(* Logix 5000 AddOnInstructionDefinition export Ed25519_VERIFY; software revision 30.00; part 2 of 7 *)

ADD_ON_INSTRUCTION POINT_ADD   (* revision 1.0 20170916, vendor Kenneth A. Fischer *)
// Point Add:
// p3 = p1 + p2
// Requires POINT UDT
// Revision note:
// Rev1.0: 20170916 - Initial Release
VAR_IN_OUT
   Temp_C1 : DINT[22]; {required}   // A
   Temp_C2 : DINT[22]; {required}   // B
   Temp_C3 : DINT[22]; {required}   // C
   Temp_C4 : DINT[22]; {required}   // D
   Temp_C5 : DINT[22]; {required}   // E
   Temp_C6 : DINT[22]; {required}   // F
   Temp_C7 : DINT[22]; {required}   // G
   Temp_C8 : DINT[22]; {required}   // H
   Temp_C9 : DINT[22]; {required}   // R
   Temp_C10 : DINT[22]; {required}   // S
   Temp_D : DINT[43]; {required}   // W
   Inp_P1 : POINT; {required}
   Inp_P2 : POINT; {required}
   Out_P3 : POINT; {required}
END_VAR
VAR
   B256_SUB : B256_SUB;
   B256_ADD : B256_ADD;
   B256_MUL : B256_MUL;
   B256_MUL2 : B256_MUL2;
END_VAR

ROUTINE Logic   (* ladder *)
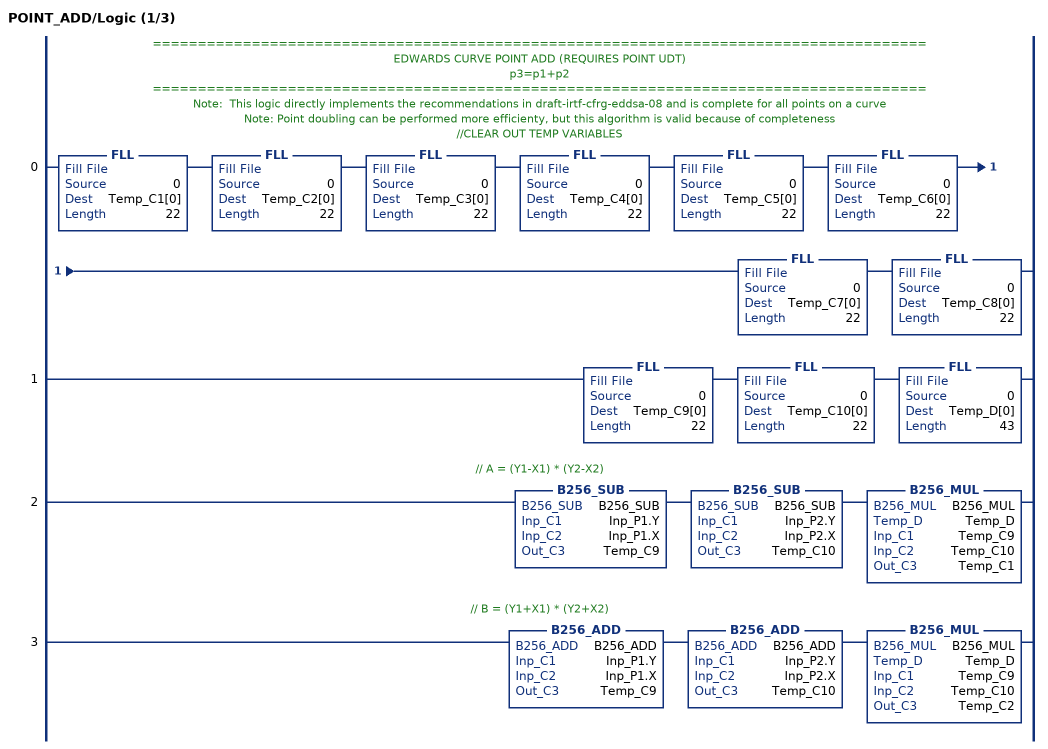
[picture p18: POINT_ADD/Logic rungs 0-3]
   // ======================================================================================
   // EDWARDS CURVE POINT ADD (REQUIRES POINT UDT)
   // p3=p1+p2
   // ======================================================================================
   // Note:  This logic directly implements the recommendations in draft-irtf-cfrg-eddsa-08 and is complete for all points on a curve
   // Note: Point doubling can be performed more efficienty, but this algorithm is valid because of completeness
   // //CLEAR OUT TEMP VARIABLES
   0: FLL(0,Temp_C1[0],22)FLL(0,Temp_C2[0],22)FLL(0,Temp_C3[0],22)FLL(0,Temp_C4[0],22)FLL(0,Temp_C5[0],22)FLL(0,Temp_C6[0],22)FLL(0,Temp_C7[0],22)FLL(0,Temp_C8[0],22);
   1: FLL(0,Temp_C9[0],22)FLL(0,Temp_C10[0],22)FLL(0,Temp_D[0],43);
   // // A = (Y1-X1) * (Y2-X2)
   2: B256_SUB(B256_SUB,Inp_P1.Y,Inp_P1.X,Temp_C9)B256_SUB(B256_SUB,Inp_P2.Y,Inp_P2.X,Temp_C10)B256_MUL(B256_MUL,Temp_D,Temp_C9,Temp_C10,Temp_C1);
   // // B = (Y1+X1) * (Y2+X2)
   3: B256_ADD(B256_ADD,Inp_P1.Y,Inp_P1.X,Temp_C9)B256_ADD(B256_ADD,Inp_P2.Y,Inp_P2.X,Temp_C10)B256_MUL(B256_MUL,Temp_D,Temp_C9,Temp_C10,Temp_C2);
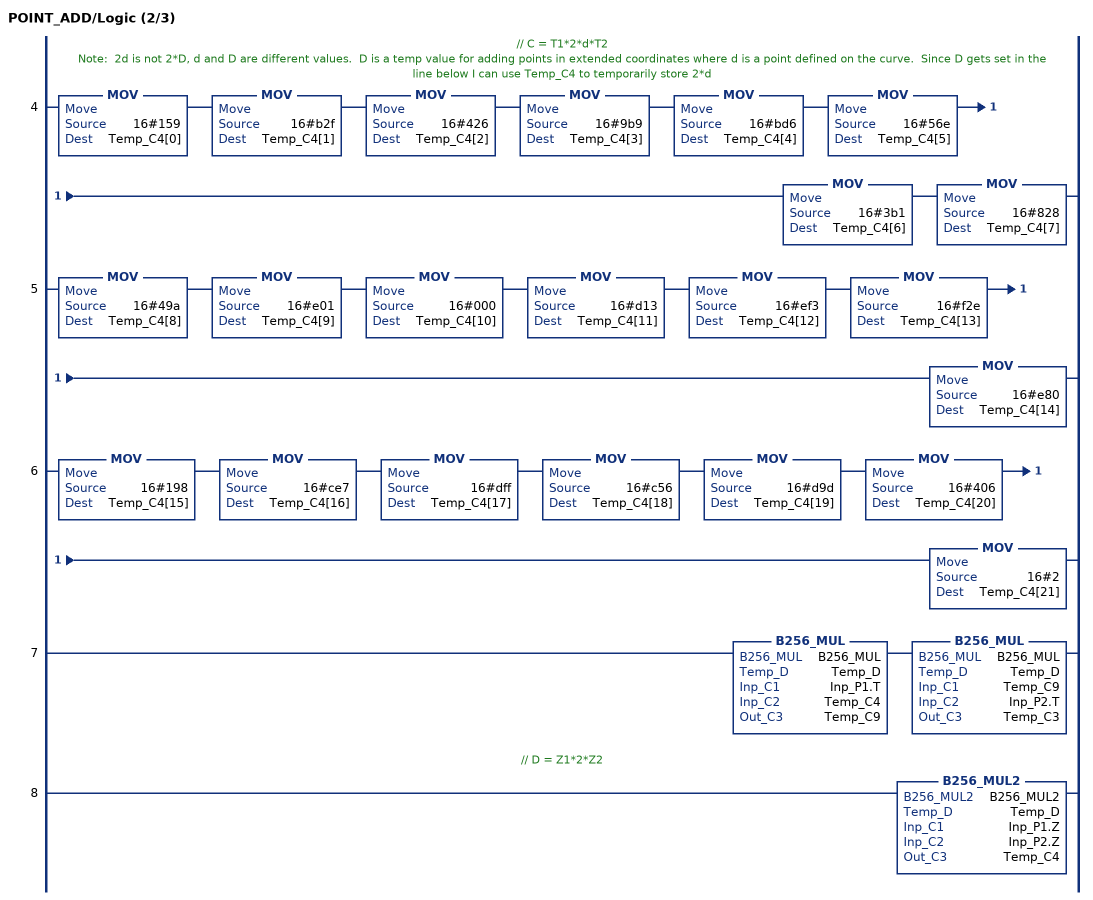
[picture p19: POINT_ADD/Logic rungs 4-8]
   // // C = T1*2*d*T2
   // Note:  2d is not 2*D, d and D are different values.  D is a temp value for adding points in extended coordinates where d is a point defined on the curve.  Since D gets set in the line below I can use Temp_C4 to temporarily store 2*d
   4: MOV(16#159,Temp_C4[0])MOV(16#b2f,Temp_C4[1])MOV(16#426,Temp_C4[2])MOV(16#9b9,Temp_C4[3])MOV(16#bd6,Temp_C4[4])MOV(16#56e,Temp_C4[5])MOV(16#3b1,Temp_C4[6])MOV(16#828,Temp_C4[7]);
   5: MOV(16#49a,Temp_C4[8])MOV(16#e01,Temp_C4[9])MOV(16#000,Temp_C4[10])MOV(16#d13,Temp_C4[11])MOV(16#ef3,Temp_C4[12])MOV(16#f2e,Temp_C4[13])MOV(16#e80,Temp_C4[14]);
   6: MOV(16#198,Temp_C4[15])MOV(16#ce7,Temp_C4[16])MOV(16#dff,Temp_C4[17])MOV(16#c56,Temp_C4[18])MOV(16#d9d,Temp_C4[19])MOV(16#406,Temp_C4[20])MOV(16#2,Temp_C4[21]);
   7: B256_MUL(B256_MUL,Temp_D,Inp_P1.T,Temp_C4,Temp_C9)B256_MUL(B256_MUL,Temp_D,Temp_C9,Inp_P2.T,Temp_C3);
   // // D = Z1*2*Z2
   8: B256_MUL2(B256_MUL2,Temp_D,Inp_P1.Z,Inp_P2.Z,Temp_C4);
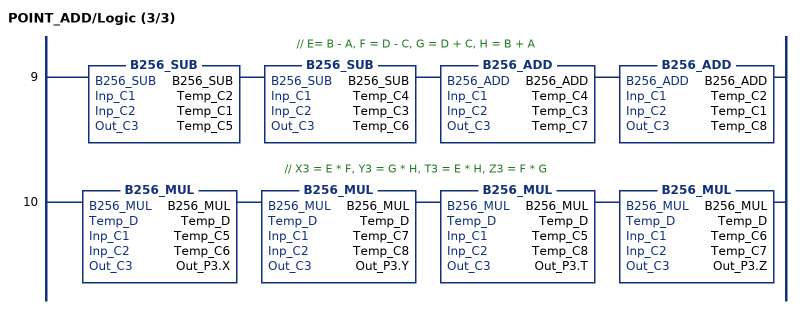
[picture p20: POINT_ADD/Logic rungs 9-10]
   // // E= B - A, F = D - C, G = D + C, H = B + A
   9: B256_SUB(B256_SUB,Temp_C2,Temp_C1,Temp_C5)B256_SUB(B256_SUB,Temp_C4,Temp_C3,Temp_C6)B256_ADD(B256_ADD,Temp_C4,Temp_C3,Temp_C7)B256_ADD(B256_ADD,Temp_C2,Temp_C1,Temp_C8);
   // // X3 = E * F, Y3 = G * H, T3 = E * H, Z3 = F * G
   10: B256_MUL(B256_MUL,Temp_D,Temp_C5,Temp_C6,Out_P3.X)B256_MUL(B256_MUL,Temp_D,Temp_C7,Temp_C8,Out_P3.Y)B256_MUL(B256_MUL,Temp_D,Temp_C5,Temp_C8,Out_P3.T)B256_MUL(B256_MUL,Temp_D,Temp_C6,Temp_C7,Out_P3.Z);
END_ROUTINE
END_ADD_ON_INSTRUCTION

ADD_ON_INSTRUCTION B256_SQU   (* revision 1.0 20170916, vendor Kenneth A. Fischer *)
// c2 = c1*c1 with reduction and mod
// uses about half the number of multiplies compared to B256_MOD
// Revision note:
// Rev1.0: 20170916 - Initial Release
VAR_IN_OUT
   Temp_D : DINT[43]; {required}
   Inp_C1 : DINT[22]; {required}
   Out_C2 : DINT[22]; {required}
END_VAR
VAR
   B256_NNRED : B256_NNRED;
   i : INT;
   j : INT;
   z : INT;
   mul_temp : DINT;
   B256_MOD : B256_MOD;
   B256_NRED : B256_NRED;
   t : DINT;
END_VAR

ROUTINE Logic   (* ladder *)
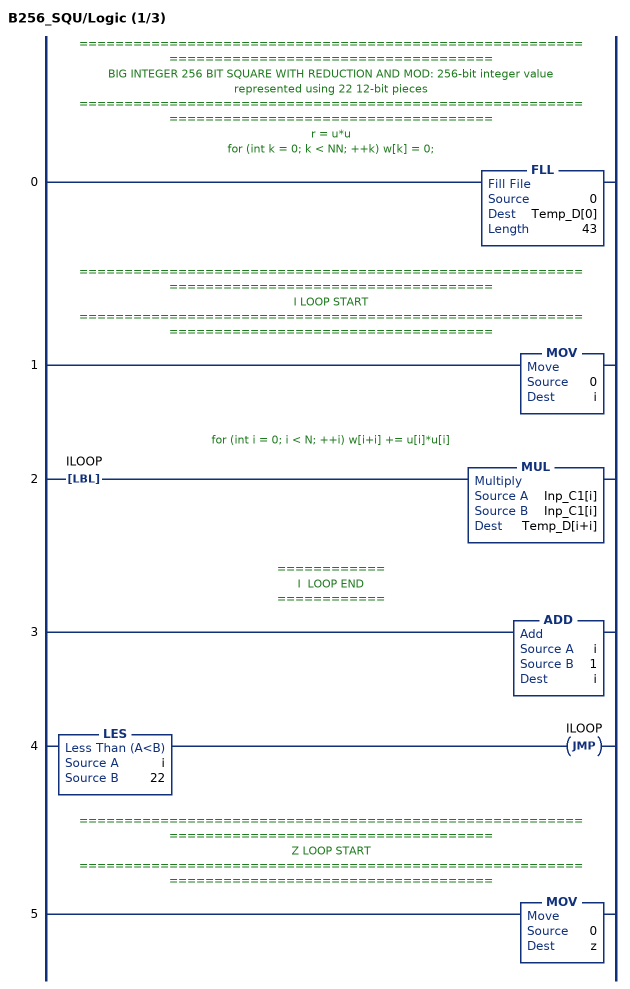
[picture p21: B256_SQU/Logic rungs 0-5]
   // ============================================================================================
   // BIG INTEGER 256 BIT SQUARE WITH REDUCTION AND MOD: 256-bit integer value represented using 22 12-bit pieces
   // ============================================================================================
   // r = u*u
   // for (int k = 0; k < NN; ++k) w[k] = 0;
   0: FLL(0,Temp_D[0],43);
   // ============================================================================================
   // I LOOP START
   // ============================================================================================
   1: MOV(0,i);
   // for (int i = 0; i < N; ++i) w[i+i] += u[i]*u[i]
   2: LBL(ILOOP)MUL(Inp_C1[i],Inp_C1[i],Temp_D[i+i]);
   // ============
   // I  LOOP END
   // ============
   3: ADD(i,1,i);
   4: LES(i,22)JMP(ILOOP);
   // ============================================================================================
   // Z LOOP START
   // ============================================================================================
   5: MOV(0,z);
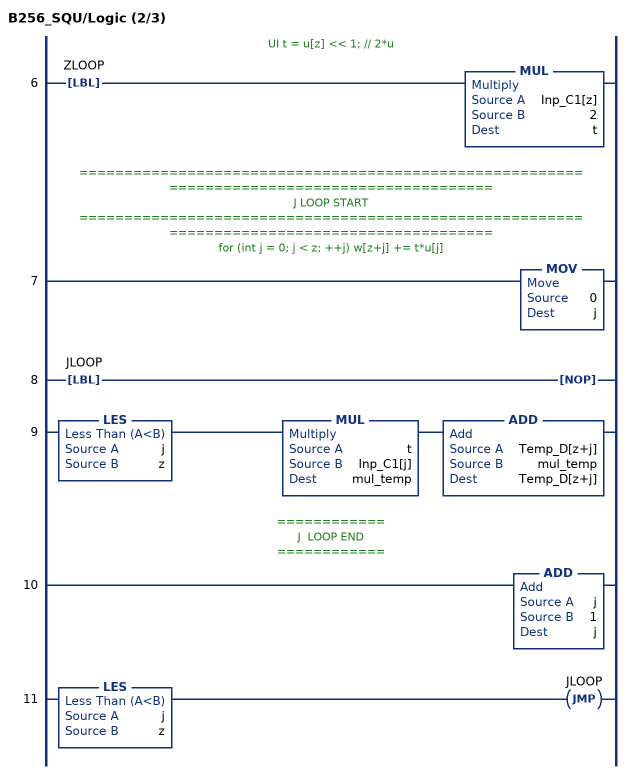
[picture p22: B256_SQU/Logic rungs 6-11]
   // UI t = u[z] << 1; // 2*u
   6: LBL(ZLOOP)MUL(Inp_C1[z],2,t);
   // ============================================================================================
   // J LOOP START
   // ============================================================================================
   // for (int j = 0; j < z; ++j) w[z+j] += t*u[j]
   7: MOV(0,j);
   8: LBL(JLOOP)NOP();
   9: LES(j,z)MUL(t,Inp_C1[j],mul_temp)ADD(Temp_D[z+j],mul_temp,Temp_D[z+j]);
   // ============
   // J  LOOP END
   // ============
   10: ADD(j,1,j);
   11: LES(j,z)JMP(JLOOP);
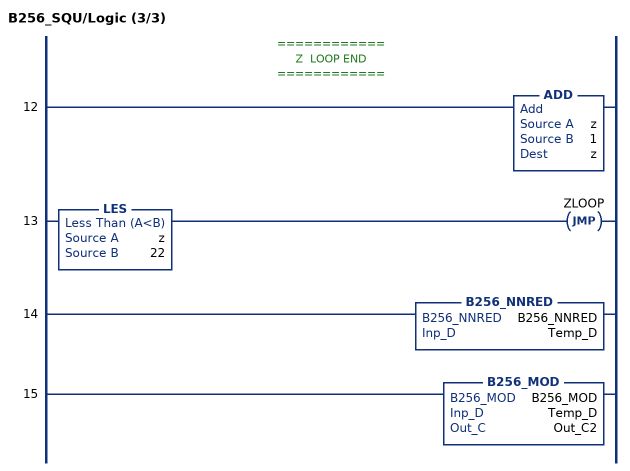
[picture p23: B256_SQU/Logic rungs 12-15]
   // ============
   // Z  LOOP END
   // ============
   12: ADD(z,1,z);
   13: LES(z,22)JMP(ZLOOP);
   14: B256_NNRED(B256_NNRED,Temp_D);
   15: B256_MOD(B256_MOD,Temp_D,Out_C2);
END_ROUTINE
END_ADD_ON_INSTRUCTION

ADD_ON_INSTRUCTION POINT_DBL   (* revision 1.0 20170916, vendor Kenneth A. Fischer *)
// Point Doubling:
// p3 = p1 + p1
// Requires POINT UDT
// Revision note:
// Rev1.0: 20170916 - Initial Release
VAR_IN_OUT
   Temp_C1 : DINT[22]; {required}   // A
   Temp_C2 : DINT[22]; {required}   // B
   Temp_C3 : DINT[22]; {required}   // C
   Temp_C4 : DINT[22]; {required}   // D
   Temp_C5 : DINT[22]; {required}   // F
   Temp_C6 : DINT[22]; {required}   // G
   Temp_C7 : DINT[22]; {required}   // H
   Temp_C8 : DINT[22]; {required}   // R
   Temp_C9 : DINT[22]; {required}   // S
   Temp_D : DINT[43]; {required}   // W
   Inp_P1 : POINT; {required}
   Out_P3 : POINT; {required}
END_VAR
VAR
   B256_ADD : B256_ADD;
   B256_MUL : B256_MUL;
   B256_SUB : B256_SUB;
   B256_MUL2 : B256_MUL2;
   B256_SQR : B256_SQU;
END_VAR

ROUTINE Logic   (* ladder *)
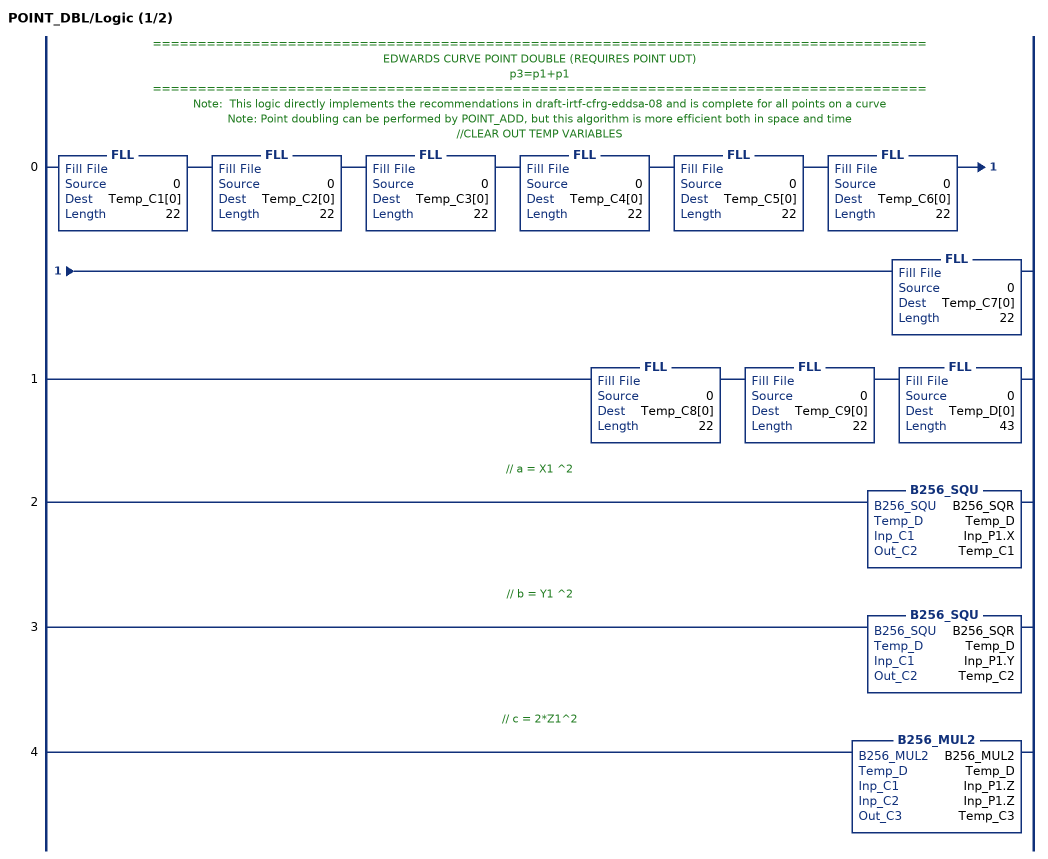
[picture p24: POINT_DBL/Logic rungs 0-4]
   // ======================================================================================
   // EDWARDS CURVE POINT DOUBLE (REQUIRES POINT UDT)
   // p3=p1+p1
   // ======================================================================================
   // Note:  This logic directly implements the recommendations in draft-irtf-cfrg-eddsa-08 and is complete for all points on a curve
   // Note: Point doubling can be performed by POINT_ADD, but this algorithm is more efficient both in space and time
   // //CLEAR OUT TEMP VARIABLES
   0: FLL(0,Temp_C1[0],22)FLL(0,Temp_C2[0],22)FLL(0,Temp_C3[0],22)FLL(0,Temp_C4[0],22)FLL(0,Temp_C5[0],22)FLL(0,Temp_C6[0],22)FLL(0,Temp_C7[0],22);
   1: FLL(0,Temp_C8[0],22)FLL(0,Temp_C9[0],22)FLL(0,Temp_D[0],43);
   // // a = X1 ^2
   2: B256_SQU(B256_SQR,Temp_D,Inp_P1.X,Temp_C1);
   // // b = Y1 ^2
   3: B256_SQU(B256_SQR,Temp_D,Inp_P1.Y,Temp_C2);
   // // c = 2*Z1^2
   4: B256_MUL2(B256_MUL2,Temp_D,Inp_P1.Z,Inp_P1.Z,Temp_C3);
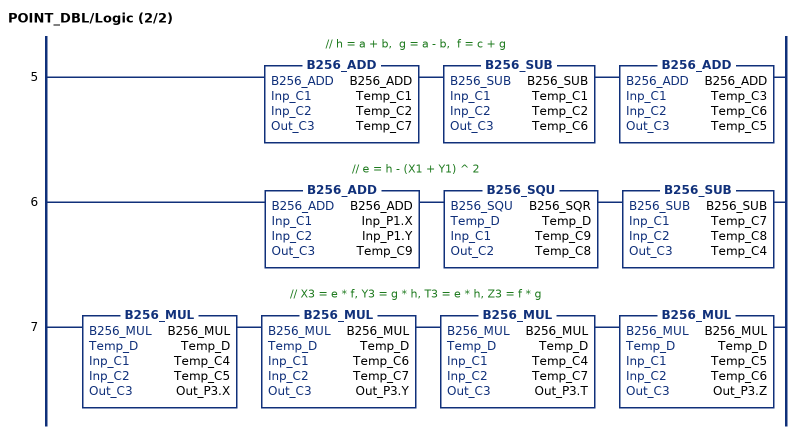
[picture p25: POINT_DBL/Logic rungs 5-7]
   // // h = a + b,  g = a - b,  f = c + g
   5: B256_ADD(B256_ADD,Temp_C1,Temp_C2,Temp_C7)B256_SUB(B256_SUB,Temp_C1,Temp_C2,Temp_C6)B256_ADD(B256_ADD,Temp_C3,Temp_C6,Temp_C5);
   // // e = h - (X1 + Y1) ^ 2
   6: B256_ADD(B256_ADD,Inp_P1.X,Inp_P1.Y,Temp_C9)B256_SQU(B256_SQR,Temp_D,Temp_C9,Temp_C8)B256_SUB(B256_SUB,Temp_C7,Temp_C8,Temp_C4);
   // // X3 = e * f, Y3 = g * h, T3 = e * h, Z3 = f * g
   7: B256_MUL(B256_MUL,Temp_D,Temp_C4,Temp_C5,Out_P3.X)B256_MUL(B256_MUL,Temp_D,Temp_C6,Temp_C7,Out_P3.Y)B256_MUL(B256_MUL,Temp_D,Temp_C4,Temp_C7,Out_P3.T)B256_MUL(B256_MUL,Temp_D,Temp_C5,Temp_C6,Out_P3.Z);
END_ROUTINE
END_ADD_ON_INSTRUCTION

ADD_ON_INSTRUCTION B256_ADJ   (* revision 1.0 20170916, vendor Kenneth A. Fischer *)
// if c >= m then subtract m
// Revision note:
// Rev1.0: 20170916 - Initial Release
VAR_IN_OUT
   Inp_C : DINT[22]; {required}
END_VAR
VAR
   i : INT;
   j : INT;
END_VAR

ROUTINE Logic   (* ladder *)
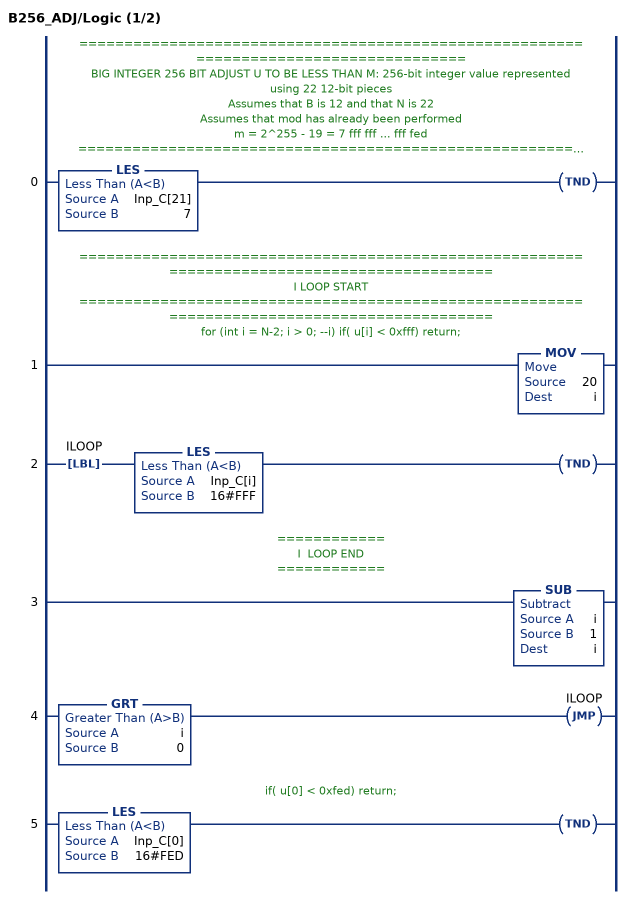
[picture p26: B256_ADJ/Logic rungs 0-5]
   // ======================================================================================
   // BIG INTEGER 256 BIT ADJUST U TO BE LESS THAN M: 256-bit integer value represented using 22 12-bit pieces
   // Assumes that B is 12 and that N is 22
   // Assumes that mod has already been performed
   // m = 2^255 - 19 = 7 fff fff ... fff fed
   // ======================================================================================
   // if (u[n-1] < 7) return;
   0: LES(Inp_C[21],7)TND();
   // ============================================================================================
   // I LOOP START
   // ============================================================================================
   // for (int i = N-2; i > 0; --i) if( u[i] < 0xfff) return;
   1: MOV(20,i);
   2: LBL(ILOOP)LES(Inp_C[i],16#FFF)TND();
   // ============
   // I  LOOP END
   // ============
   3: SUB(i,1,i);
   4: GRT(i,0)JMP(ILOOP);
   // if( u[0] < 0xfed) return;
   5: LES(Inp_C[0],16#FED)TND();
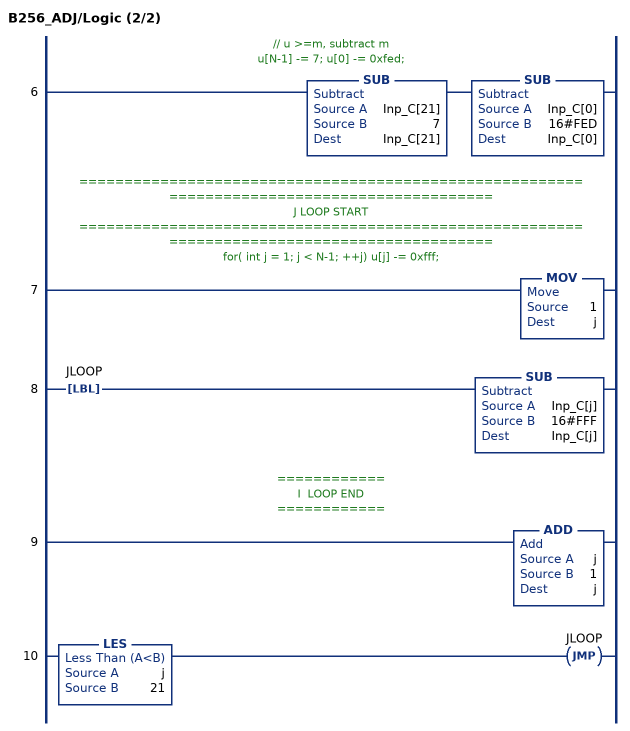
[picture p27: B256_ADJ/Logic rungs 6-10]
   // // u >=m, subtract m
   // u[N-1] -= 7; u[0] -= 0xfed;
   6: SUB(Inp_C[21],7,Inp_C[21])SUB(Inp_C[0],16#FED,Inp_C[0]);
   // ============================================================================================
   // J LOOP START
   // ============================================================================================
   // for( int j = 1; j < N-1; ++j) u[j] -= 0xfff;
   7: MOV(1,j);
   8: LBL(JLOOP)SUB(Inp_C[j],16#FFF,Inp_C[j]);
   // ============
   // I  LOOP END
   // ============
   9: ADD(j,1,j);
   10: LES(j,21)JMP(JLOOP);
END_ROUTINE
END_ADD_ON_INSTRUCTION

ADD_ON_INSTRUCTION POINT_MUL   (* revision 1.0 20170916, vendor Kenneth A. Fischer *)
// Point Multiplication:
// p3 = e*p1
// Requires POINT UDT
// Revision note:
// Rev1.0: 20170916 - Initial Release
VAR_IN_OUT
   Temp_C1 : DINT[22]; {required}
   Temp_C2 : DINT[22]; {required}
   Temp_C3 : DINT[22]; {required}
   Temp_C4 : DINT[22]; {required}   // a
   Temp_C5 : DINT[22]; {required}   // b
   Temp_C6 : DINT[22]; {required}   // c
   Temp_C7 : DINT[22]; {required}   // d
   Temp_C8 : DINT[22]; {required}   // e
   Temp_C9 : DINT[22]; {required}   // f
   Temp_C10 : DINT[22]; {required}   // g
   Temp_D : DINT[43]; {required}
   Temp_P1 : POINT; {required}
   Temp_P2 : POINT; {required}
   Inp_E : DINT[32]; {required}
   Inp_P : POINT; {required}
   Out_P : POINT; {required}
END_VAR
VAR_OUTPUT
   SEQCTRL_DN : BOOL; {access Read Only}   // Point Multiplication Complete
END_VAR
VAR_INPUT
   SEQCTRL_RESET : BOOL;   // Resets Point Multiplication if Toggled True
END_VAR
VAR_OUTPUT
   SEQCTRL_STEP : INT; {access Read Only}
END_VAR
VAR
   POINT_DBL : POINT_DBL;
   b : DINT;   // byte for processing each element in the exponent
   j : INT;
   SEQCTRL_DONE : INT;
   alpha : DINT;
   beta : DINT;
   POINT_ADD : POINT_ADD;
   D_SHR : D_SHR;
   B256_ADJ : B256_ADJ;
   SEQCTRL_CMD : INT;
   TEMP : INT;
   SEQCTRL_NEXT_STEP : INT;
   i : INT;
   SEQCTRL_CMD_TABLE : INT[70];
   i_LOOP_TEMPLATE : INT[33];
   j_LOOP_TEMPLATE : INT[4];
END_VAR

ROUTINE Logic   (* ladder *)
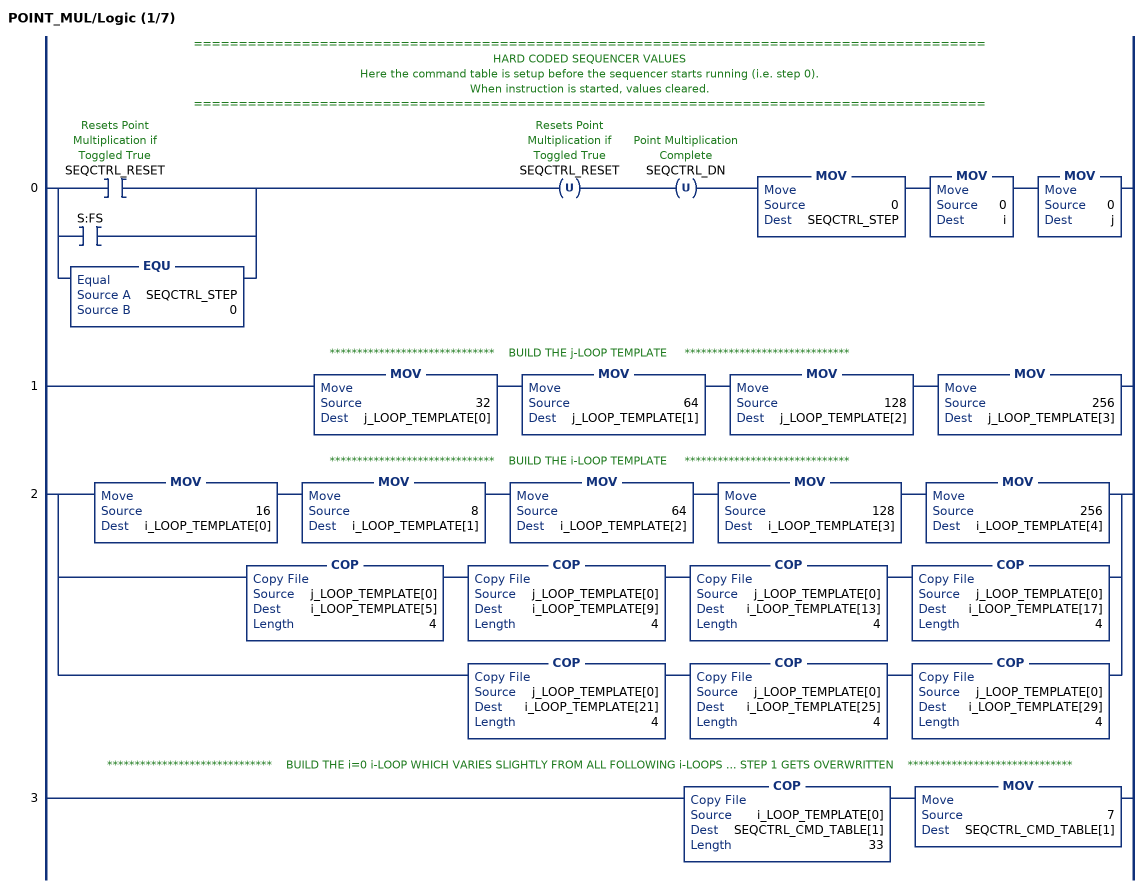
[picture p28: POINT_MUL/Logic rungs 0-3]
   // ========================================================================================
   // HARD CODED SEQUENCER VALUES
   // Here the command table is setup before the sequencer starts running (i.e. step 0).
   // When instruction is started, values cleared.
   // ========================================================================================
   0: [[XIC(SEQCTRL_RESET) ,XIC(S:FS) ] ,EQU(SEQCTRL_STEP,0) ]OTU(SEQCTRL_RESET)OTU(SEQCTRL_DN)MOV(0,SEQCTRL_STEP)MOV(0,i)MOV(0,j);
   // ******************************    BUILD THE j-LOOP TEMPLATE     ******************************
   1: MOV(32,j_LOOP_TEMPLATE[0])MOV(64,j_LOOP_TEMPLATE[1])MOV(128,j_LOOP_TEMPLATE[2])MOV(256,j_LOOP_TEMPLATE[3]);
   // ******************************    BUILD THE i-LOOP TEMPLATE     ******************************
   2: [MOV(16,i_LOOP_TEMPLATE[0]) MOV(8,i_LOOP_TEMPLATE[1]) MOV(64,i_LOOP_TEMPLATE[2]) MOV(128,i_LOOP_TEMPLATE[3]) MOV(256,i_LOOP_TEMPLATE[4]) ,COP(j_LOOP_TEMPLATE[0],i_LOOP_TEMPLATE[5],4) COP(j_LOOP_TEMPLATE[0],i_LOOP_TEMPLATE[9],4) COP(j_LOOP_TEMPLATE[0],i_LOOP_TEMPLATE[13],4) COP(j_LOOP_TEMPLATE[0],i_LOOP_TEMPLATE[17],4) ,COP(j_LOOP_TEMPLATE[0],i_LOOP_TEMPLATE[21],4) COP(j_LOOP_TEMPLATE[0],i_LOOP_TEMPLATE[25],4) COP(j_LOOP_TEMPLATE[0],i_LOOP_TEMPLATE[29],4) ];
   // ******************************    BUILD THE i=0 i-LOOP WHICH VARIES SLIGHTLY FROM ALL FOLLOWING i-LOOPS ... STEP 1 GETS OVERWRITTEN    ******************************
   3: COP(i_LOOP_TEMPLATE[0],SEQCTRL_CMD_TABLE[1],33)MOV(7,SEQCTRL_CMD_TABLE[1]);
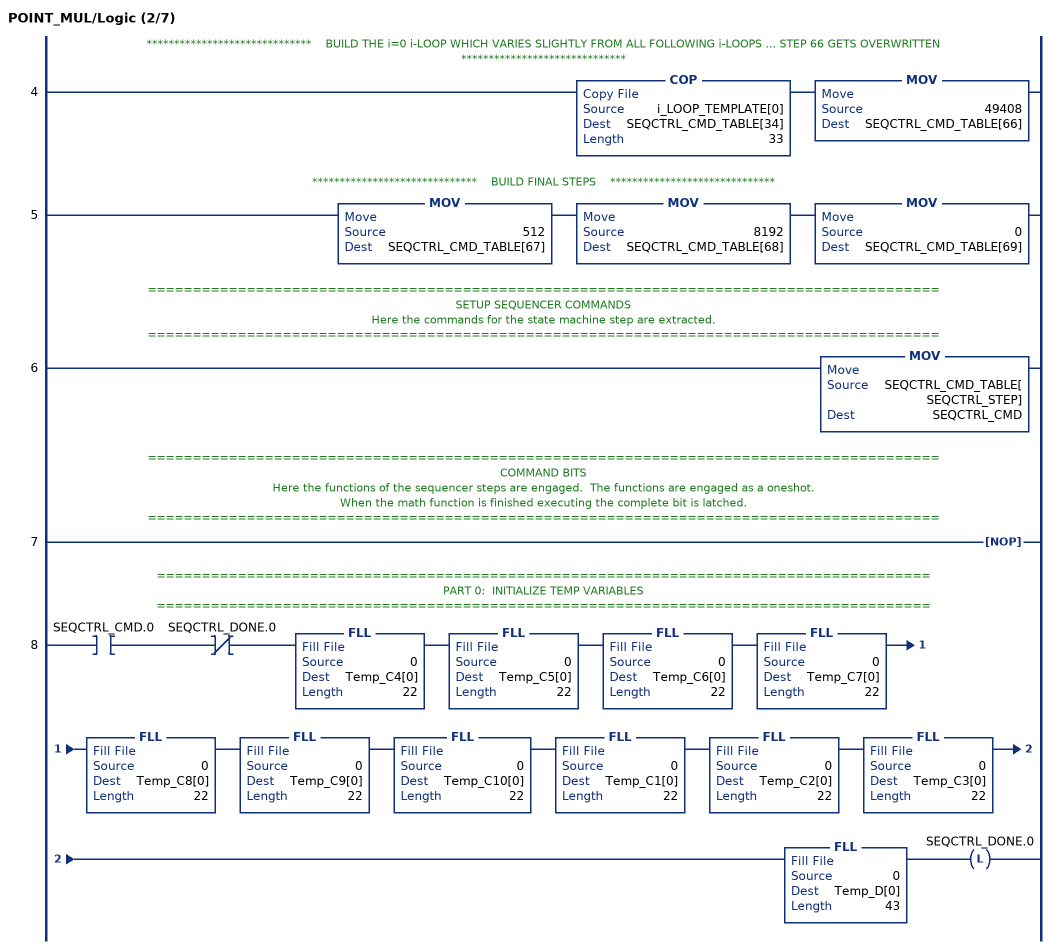
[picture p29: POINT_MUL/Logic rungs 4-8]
   // ******************************    BUILD THE i=0 i-LOOP WHICH VARIES SLIGHTLY FROM ALL FOLLOWING i-LOOPS ... STEP 66 GETS OVERWRITTEN    ******************************
   4: COP(i_LOOP_TEMPLATE[0],SEQCTRL_CMD_TABLE[34],33)MOV(49408,SEQCTRL_CMD_TABLE[66]);
   // ******************************    BUILD FINAL STEPS    ******************************
   5: MOV(512,SEQCTRL_CMD_TABLE[67])MOV(8192,SEQCTRL_CMD_TABLE[68])MOV(0,SEQCTRL_CMD_TABLE[69]);
   // ========================================================================================
   // SETUP SEQUENCER COMMANDS
   // Here the commands for the state machine step are extracted.
   // ========================================================================================
   6: MOV(SEQCTRL_CMD_TABLE[SEQCTRL_STEP],SEQCTRL_CMD);
   // ========================================================================================
   // COMMAND BITS
   // Here the functions of the sequencer steps are engaged.  The functions are engaged as a oneshot.
   // When the math function is finished executing the complete bit is latched.
   // ========================================================================================
   7: NOP();
   // ======================================================================================
   // PART 0:  INITIALIZE TEMP VARIABLES
   // ======================================================================================
   8: XIC(SEQCTRL_CMD.0)XIO(SEQCTRL_DONE.0)FLL(0,Temp_C4[0],22)FLL(0,Temp_C5[0],22)FLL(0,Temp_C6[0],22)FLL(0,Temp_C7[0],22)FLL(0,Temp_C8[0],22)FLL(0,Temp_C9[0],22)FLL(0,Temp_C10[0],22)FLL(0,Temp_C1[0],22)FLL(0,Temp_C2[0],22)FLL(0,Temp_C3[0],22)FLL(0,Temp_D[0],43)OTL(SEQCTRL_DONE.0);
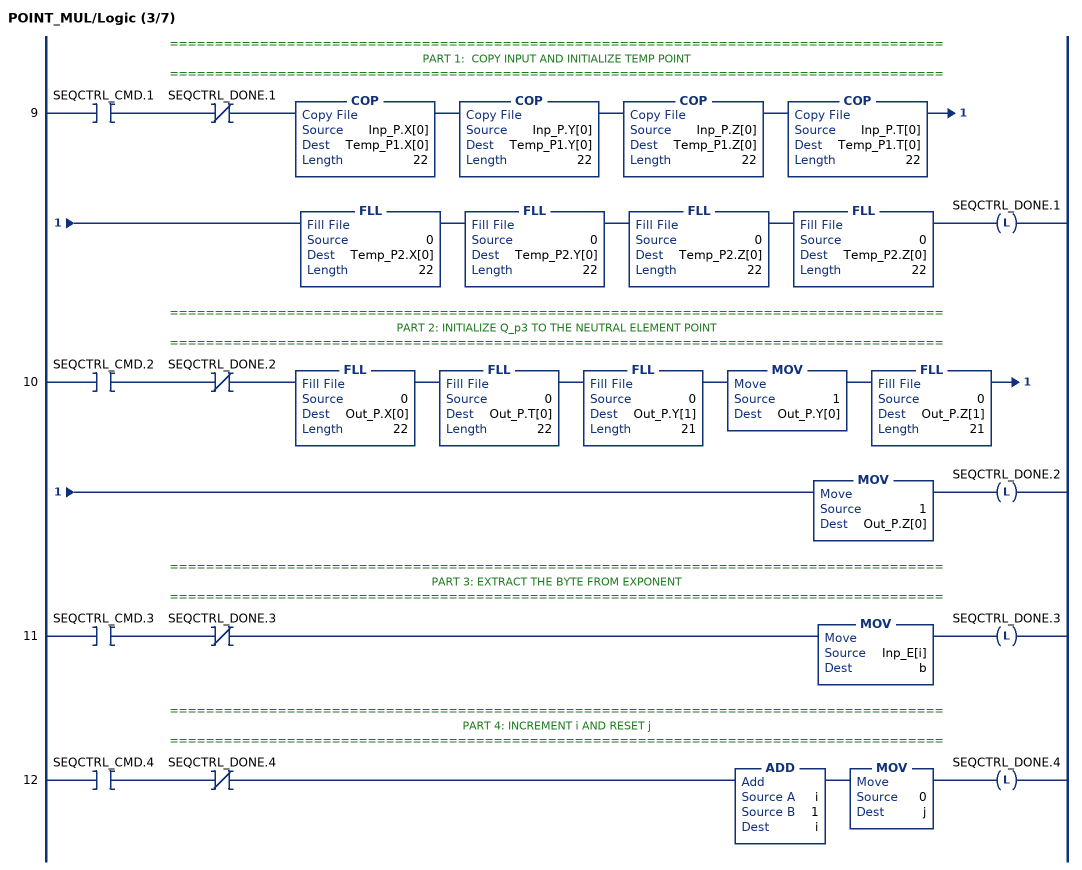
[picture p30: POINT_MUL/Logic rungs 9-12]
   // ======================================================================================
   // PART 1:  COPY INPUT AND INITIALIZE TEMP POINT
   // ======================================================================================
   9: XIC(SEQCTRL_CMD.1)XIO(SEQCTRL_DONE.1)COP(Inp_P.X[0],Temp_P1.X[0],22)COP(Inp_P.Y[0],Temp_P1.Y[0],22)COP(Inp_P.Z[0],Temp_P1.Z[0],22)COP(Inp_P.T[0],Temp_P1.T[0],22)FLL(0,Temp_P2.X[0],22)FLL(0,Temp_P2.Y[0],22)FLL(0,Temp_P2.Z[0],22)FLL(0,Temp_P2.Z[0],22)OTL(SEQCTRL_DONE.1);
   // ======================================================================================
   // PART 2: INITIALIZE Q_p3 TO THE NEUTRAL ELEMENT POINT
   // ======================================================================================
   10: XIC(SEQCTRL_CMD.2)XIO(SEQCTRL_DONE.2)FLL(0,Out_P.X[0],22)FLL(0,Out_P.T[0],22)FLL(0,Out_P.Y[1],21)MOV(1,Out_P.Y[0])FLL(0,Out_P.Z[1],21)MOV(1,Out_P.Z[0])OTL(SEQCTRL_DONE.2);
   // ======================================================================================
   // PART 3: EXTRACT THE BYTE FROM EXPONENT
   // ======================================================================================
   11: XIC(SEQCTRL_CMD.3)XIO(SEQCTRL_DONE.3)MOV(Inp_E[i],b)OTL(SEQCTRL_DONE.3);
   // ======================================================================================
   // PART 4: INCREMENT i AND RESET j
   // ======================================================================================
   12: XIC(SEQCTRL_CMD.4)XIO(SEQCTRL_DONE.4)ADD(i,1,i)MOV(0,j)OTL(SEQCTRL_DONE.4);
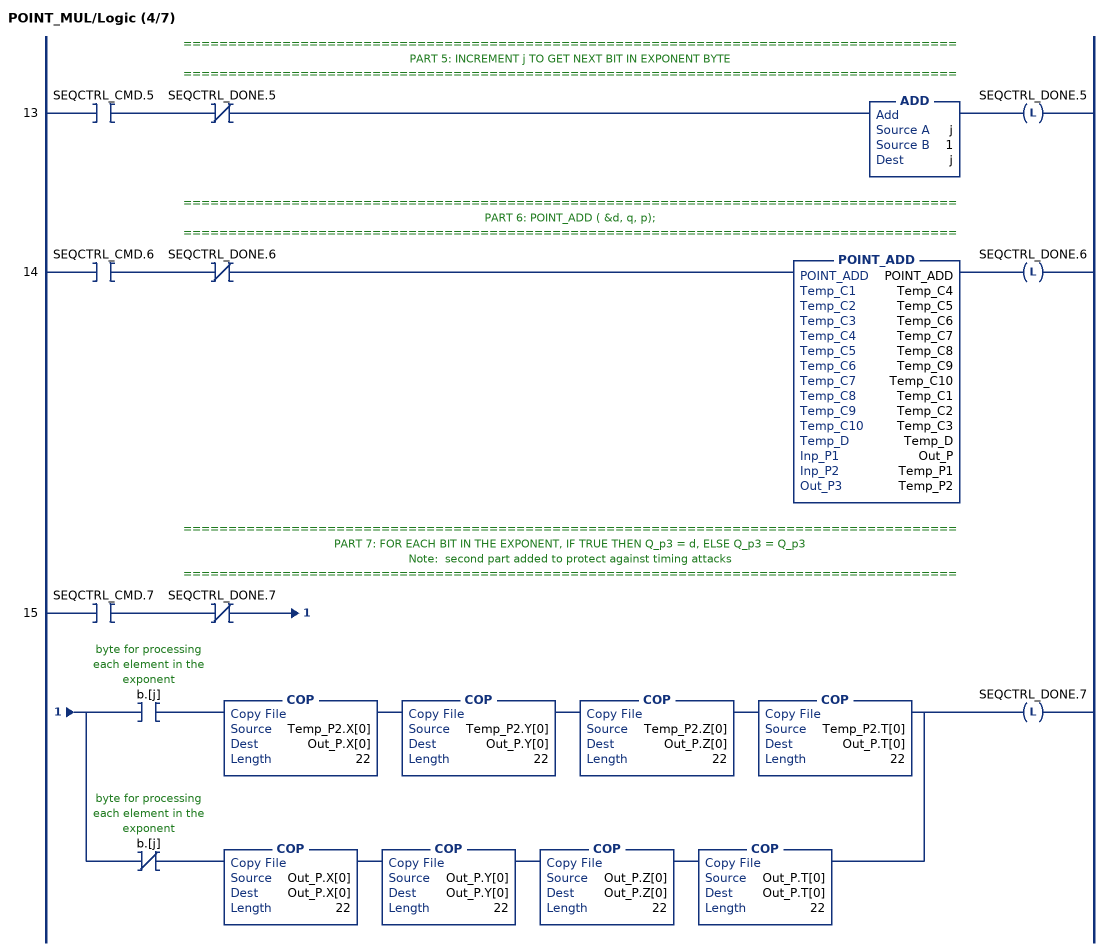
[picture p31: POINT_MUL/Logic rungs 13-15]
   // ======================================================================================
   // PART 5: INCREMENT j TO GET NEXT BIT IN EXPONENT BYTE
   // ======================================================================================
   13: XIC(SEQCTRL_CMD.5)XIO(SEQCTRL_DONE.5)ADD(j,1,j)OTL(SEQCTRL_DONE.5);
   // ======================================================================================
   // PART 6: POINT_ADD ( &d, q, p);
   // ======================================================================================
   14: XIC(SEQCTRL_CMD.6)XIO(SEQCTRL_DONE.6)POINT_ADD(POINT_ADD,Temp_C4,Temp_C5,Temp_C6,Temp_C7,Temp_C8,Temp_C9,Temp_C10,Temp_C1,Temp_C2,Temp_C3,Temp_D,Out_P,Temp_P1,Temp_P2)OTL(SEQCTRL_DONE.6);
   // ======================================================================================
   // PART 7: FOR EACH BIT IN THE EXPONENT, IF TRUE THEN Q_p3 = d, ELSE Q_p3 = Q_p3
   // Note:  second part added to protect against timing attacks
   // ======================================================================================
   15: XIC(SEQCTRL_CMD.7)XIO(SEQCTRL_DONE.7)[XIC(b.[j]) COP(Temp_P2.X[0],Out_P.X[0],22) COP(Temp_P2.Y[0],Out_P.Y[0],22) COP(Temp_P2.Z[0],Out_P.Z[0],22) COP(Temp_P2.T[0],Out_P.T[0],22) ,XIO(b.[j]) COP(Out_P.X[0],Out_P.X[0],22) COP(Out_P.Y[0],Out_P.Y[0],22) COP(Out_P.Z[0],Out_P.Z[0],22) COP(Out_P.T[0],Out_P.T[0],22) ]OTL(SEQCTRL_DONE.7);
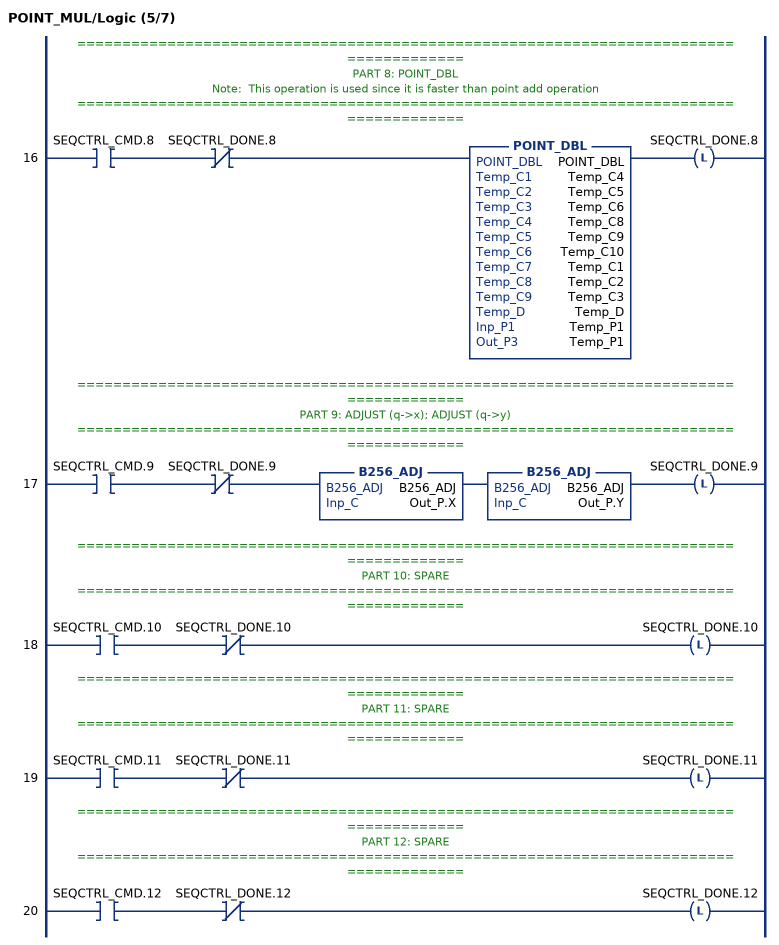
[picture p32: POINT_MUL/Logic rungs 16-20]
   // ======================================================================================
   // PART 8: POINT_DBL
   // Note:  This operation is used since it is faster than point add operation
   // ======================================================================================
   16: XIC(SEQCTRL_CMD.8)XIO(SEQCTRL_DONE.8)POINT_DBL(POINT_DBL,Temp_C4,Temp_C5,Temp_C6,Temp_C8,Temp_C9,Temp_C10,Temp_C1,Temp_C2,Temp_C3,Temp_D,Temp_P1,Temp_P1)OTL(SEQCTRL_DONE.8);
   // ======================================================================================
   // PART 9: ADJUST (q->x); ADJUST (q->y)
   // ======================================================================================
   17: XIC(SEQCTRL_CMD.9)XIO(SEQCTRL_DONE.9)B256_ADJ(B256_ADJ,Out_P.X)B256_ADJ(B256_ADJ,Out_P.Y)OTL(SEQCTRL_DONE.9);
   // ======================================================================================
   // PART 10: SPARE
   // ======================================================================================
   18: XIC(SEQCTRL_CMD.10)XIO(SEQCTRL_DONE.10)OTL(SEQCTRL_DONE.10);
   // ======================================================================================
   // PART 11: SPARE
   // ======================================================================================
   19: XIC(SEQCTRL_CMD.11)XIO(SEQCTRL_DONE.11)OTL(SEQCTRL_DONE.11);
   // ======================================================================================
   // PART 12: SPARE
   // ======================================================================================
   20: XIC(SEQCTRL_CMD.12)XIO(SEQCTRL_DONE.12)OTL(SEQCTRL_DONE.12);
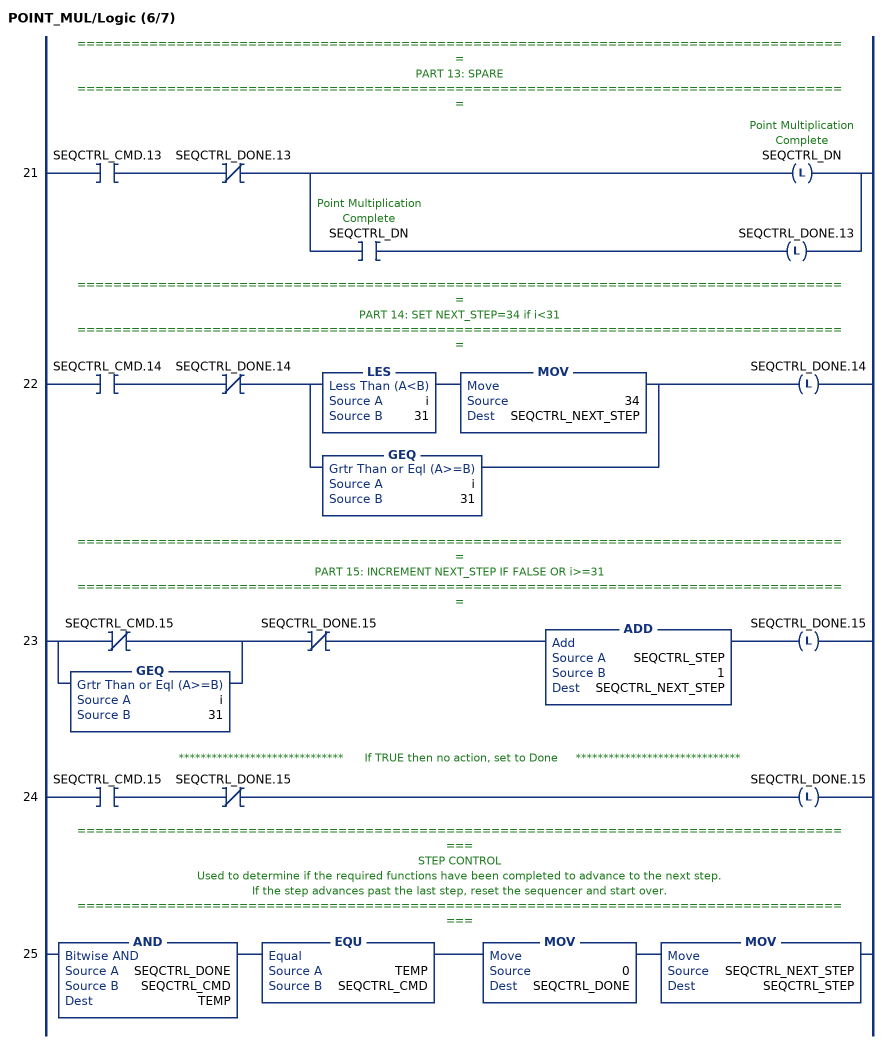
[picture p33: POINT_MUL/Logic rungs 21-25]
   // ======================================================================================
   // PART 13: SPARE
   // ======================================================================================
   21: XIC(SEQCTRL_CMD.13)XIO(SEQCTRL_DONE.13)[OTL(SEQCTRL_DN) ,XIC(SEQCTRL_DN) OTL(SEQCTRL_DONE.13) ];
   // ======================================================================================
   // PART 14: SET NEXT_STEP=34 if i<31
   // ======================================================================================
   22: XIC(SEQCTRL_CMD.14)XIO(SEQCTRL_DONE.14)[LES(i,31) MOV(34,SEQCTRL_NEXT_STEP) ,GEQ(i,31) ]OTL(SEQCTRL_DONE.14);
   // ======================================================================================
   // PART 15: INCREMENT NEXT_STEP IF FALSE OR i>=31
   // ======================================================================================
   23: [XIO(SEQCTRL_CMD.15) ,GEQ(i,31) ]XIO(SEQCTRL_DONE.15)ADD(SEQCTRL_STEP,1,SEQCTRL_NEXT_STEP)OTL(SEQCTRL_DONE.15);
   // ******************************      If TRUE then no action, set to Done     ******************************
   24: XIC(SEQCTRL_CMD.15)XIO(SEQCTRL_DONE.15)OTL(SEQCTRL_DONE.15);
   // ========================================================================================
   // STEP CONTROL
   // Used to determine if the required functions have been completed to advance to the next step.
   // If the step advances past the last step, reset the sequencer and start over.
   // ========================================================================================
   25: AND(SEQCTRL_DONE,SEQCTRL_CMD,TEMP)EQU(TEMP,SEQCTRL_CMD)MOV(0,SEQCTRL_DONE)MOV(SEQCTRL_NEXT_STEP,SEQCTRL_STEP);
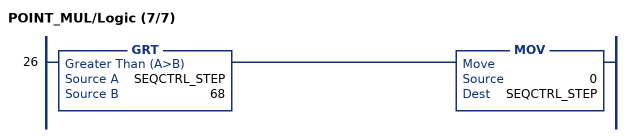
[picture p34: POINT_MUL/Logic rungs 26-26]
   26: GRT(SEQCTRL_STEP,68)MOV(0,SEQCTRL_STEP);
END_ROUTINE
END_ADD_ON_INSTRUCTION

ADD_ON_INSTRUCTION B256_CtoE   (* revision 1.0 20170916, vendor Kenneth A. Fischer *)
// Convert 256-bit value using 22 12-bit pieces into 256-bit value using 32 8-bit pieces
// Revision note:
// Rev1.0: 20170916 - Initial Release
VAR_IN_OUT
   Inp_C : DINT[22]; {required}
   Out_E : DINT[32]; {required}
END_VAR
VAR
   i : INT;
   j : INT;
   TEMP1 : DINT;
   TEMP2 : DINT;
   D_SHL : D_SHL;
   D_SHR : D_SHR;
END_VAR

ROUTINE Logic   (* ladder *)
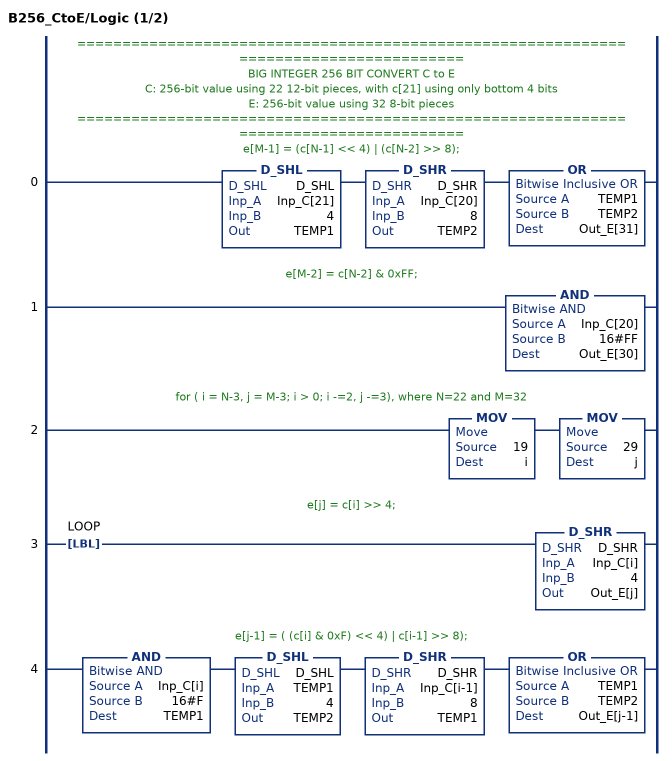
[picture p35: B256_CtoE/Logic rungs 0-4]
   // ======================================================================================
   // BIG INTEGER 256 BIT CONVERT C to E
   // C: 256-bit value using 22 12-bit pieces, with c[21] using only bottom 4 bits
   // E: 256-bit value using 32 8-bit pieces
   // ======================================================================================
   // e[M-1] = (c[N-1] << 4) | (c[N-2] >> 8);
   0: D_SHL(D_SHL,Inp_C[21],4,TEMP1)D_SHR(D_SHR,Inp_C[20],8,TEMP2)OR(TEMP1,TEMP2,Out_E[31]);
   // e[M-2] = c[N-2] & 0xFF;
   1: AND(Inp_C[20],16#FF,Out_E[30]);
   // for ( i = N-3, j = M-3; i > 0; i -=2, j -=3), where N=22 and M=32
   2: MOV(19,i)MOV(29,j);
   // e[j] = c[i] >> 4;
   3: LBL(LOOP)D_SHR(D_SHR,Inp_C[i],4,Out_E[j]);
   // e[j-1] = ( (c[i] & 0xF) << 4) | c[i-1] >> 8);
   4: AND(Inp_C[i],16#F,TEMP1)D_SHL(D_SHL,TEMP1,4,TEMP2)D_SHR(D_SHR,Inp_C[i-1],8,TEMP1)OR(TEMP1,TEMP2,Out_E[j-1]);
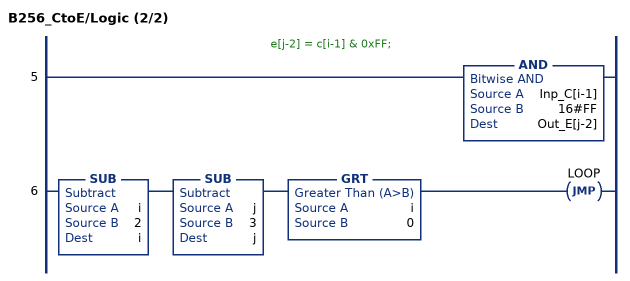
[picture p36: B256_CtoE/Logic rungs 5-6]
   // e[j-2] = c[i-1] & 0xFF;
   5: AND(Inp_C[i-1],16#FF,Out_E[j-2]);
   6: SUB(i,2,i)SUB(j,3,j)GRT(i,0)JMP(LOOP);
END_ROUTINE
END_ADD_ON_INSTRUCTION
(* Logix 5000 AddOnInstructionDefinition export Ed25519_VERIFY; software revision 30.00; part 4 of 7 *)

ADD_ON_INSTRUCTION B512_HtoD   (* revision 1.0 20170916, vendor Kenneth A. Fischer *)
// Takes a 512-bit hash value stored as 8 64-bit pieces and converts it to a 512-bit value stored as 42 12-bit pieces and 1 8-bit piece as the MSB
// Revision note:
// Rev1.0: 20170916 - Initial Release
VAR_IN_OUT
   Inp_H : LINT[8]; {required}
   Out_D : DINT[43]; {required}
END_VAR
VAR
   i : INT := 41;
   j : INT := 62;
   Wrk_InpL : DINT[16];
   D_SHR : D_SHR;
   TEMP1 : DINT;
   D_SHL : D_SHL;
   TEMP2 : DINT;
   EE : DINT[64];
END_VAR

ROUTINE Logic   (* ladder *)
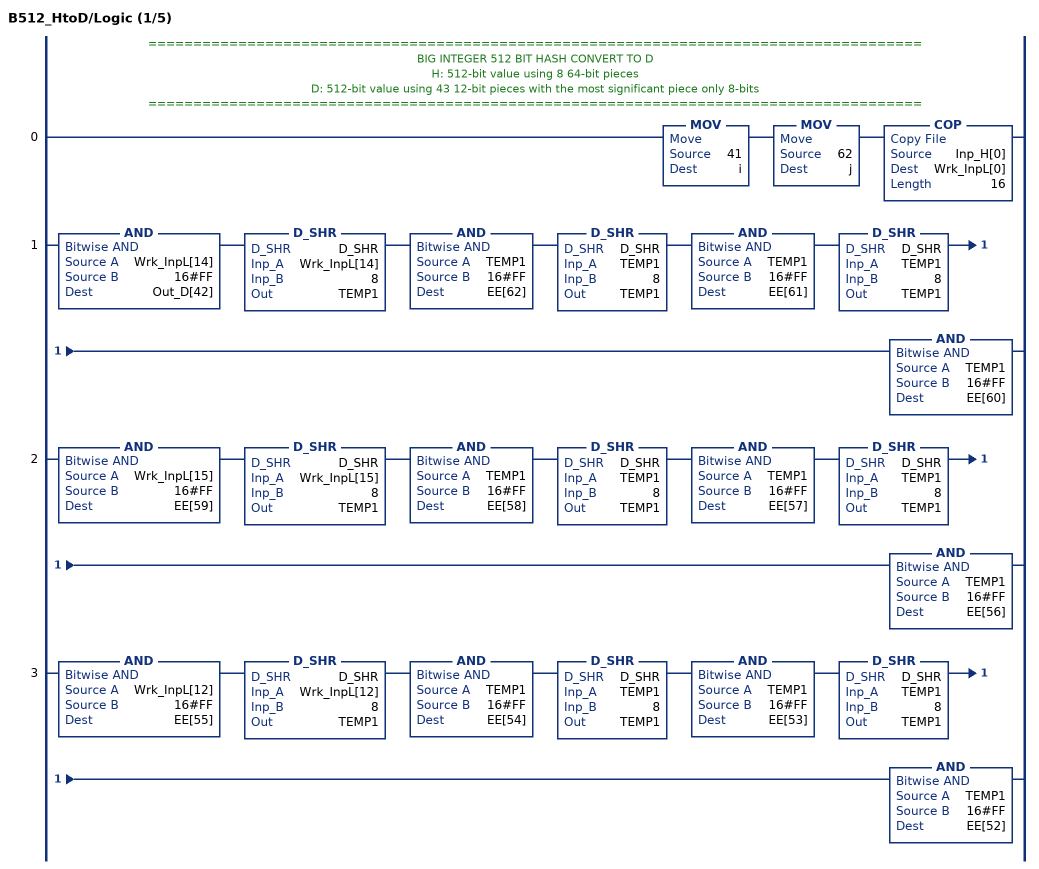
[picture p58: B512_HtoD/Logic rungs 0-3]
   // ======================================================================================
   // BIG INTEGER 512 BIT HASH CONVERT TO D
   // H: 512-bit value using 8 64-bit pieces
   // D: 512-bit value using 43 12-bit pieces with the most significant piece only 8-bits
   // ======================================================================================
   0: MOV(41,i)MOV(62,j)COP(Inp_H[0],Wrk_InpL[0],16);
   1: AND(Wrk_InpL[14],16#FF,Out_D[42])D_SHR(D_SHR,Wrk_InpL[14],8,TEMP1)AND(TEMP1,16#FF,EE[62])D_SHR(D_SHR,TEMP1,8,TEMP1)AND(TEMP1,16#FF,EE[61])D_SHR(D_SHR,TEMP1,8,TEMP1)AND(TEMP1,16#FF,EE[60]);
   2: AND(Wrk_InpL[15],16#FF,EE[59])D_SHR(D_SHR,Wrk_InpL[15],8,TEMP1)AND(TEMP1,16#FF,EE[58])D_SHR(D_SHR,TEMP1,8,TEMP1)AND(TEMP1,16#FF,EE[57])D_SHR(D_SHR,TEMP1,8,TEMP1)AND(TEMP1,16#FF,EE[56]);
   3: AND(Wrk_InpL[12],16#FF,EE[55])D_SHR(D_SHR,Wrk_InpL[12],8,TEMP1)AND(TEMP1,16#FF,EE[54])D_SHR(D_SHR,TEMP1,8,TEMP1)AND(TEMP1,16#FF,EE[53])D_SHR(D_SHR,TEMP1,8,TEMP1)AND(TEMP1,16#FF,EE[52]);
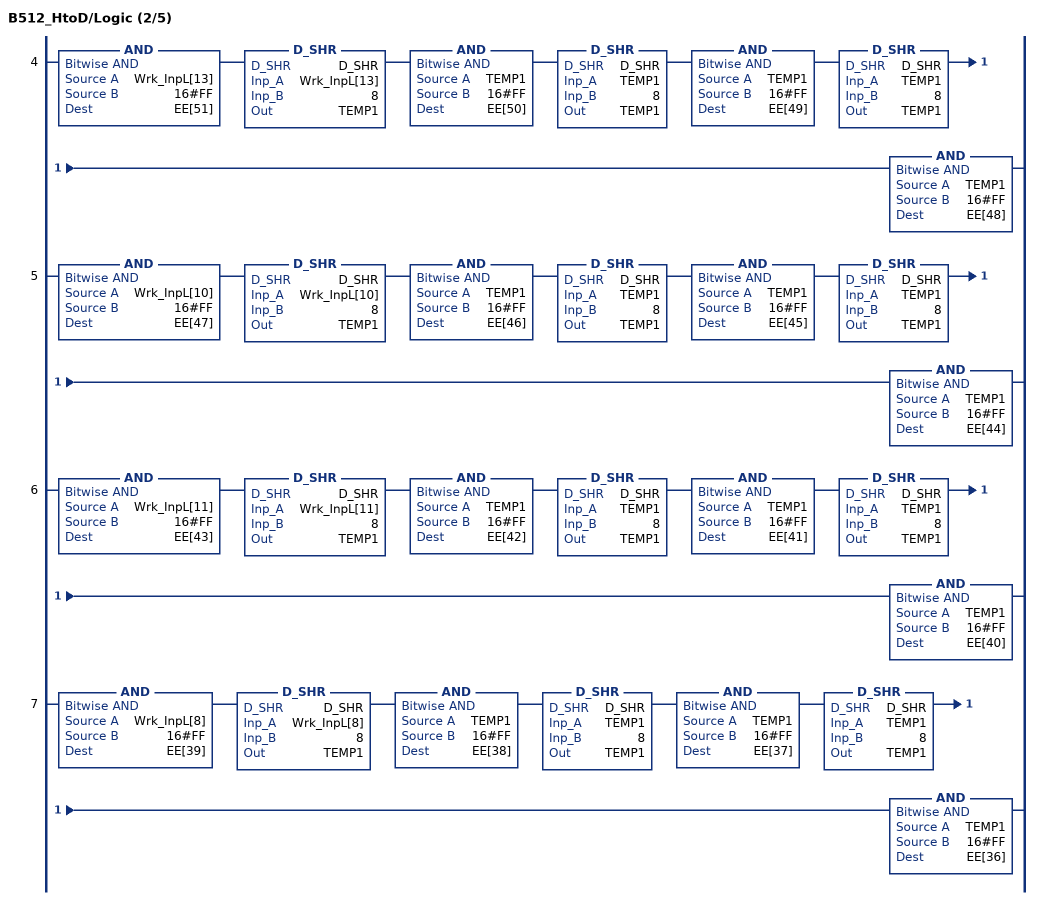
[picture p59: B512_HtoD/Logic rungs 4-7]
   4: AND(Wrk_InpL[13],16#FF,EE[51])D_SHR(D_SHR,Wrk_InpL[13],8,TEMP1)AND(TEMP1,16#FF,EE[50])D_SHR(D_SHR,TEMP1,8,TEMP1)AND(TEMP1,16#FF,EE[49])D_SHR(D_SHR,TEMP1,8,TEMP1)AND(TEMP1,16#FF,EE[48]);
   5: AND(Wrk_InpL[10],16#FF,EE[47])D_SHR(D_SHR,Wrk_InpL[10],8,TEMP1)AND(TEMP1,16#FF,EE[46])D_SHR(D_SHR,TEMP1,8,TEMP1)AND(TEMP1,16#FF,EE[45])D_SHR(D_SHR,TEMP1,8,TEMP1)AND(TEMP1,16#FF,EE[44]);
   6: AND(Wrk_InpL[11],16#FF,EE[43])D_SHR(D_SHR,Wrk_InpL[11],8,TEMP1)AND(TEMP1,16#FF,EE[42])D_SHR(D_SHR,TEMP1,8,TEMP1)AND(TEMP1,16#FF,EE[41])D_SHR(D_SHR,TEMP1,8,TEMP1)AND(TEMP1,16#FF,EE[40]);
   7: AND(Wrk_InpL[8],16#FF,EE[39])D_SHR(D_SHR,Wrk_InpL[8],8,TEMP1)AND(TEMP1,16#FF,EE[38])D_SHR(D_SHR,TEMP1,8,TEMP1)AND(TEMP1,16#FF,EE[37])D_SHR(D_SHR,TEMP1,8,TEMP1)AND(TEMP1,16#FF,EE[36]);
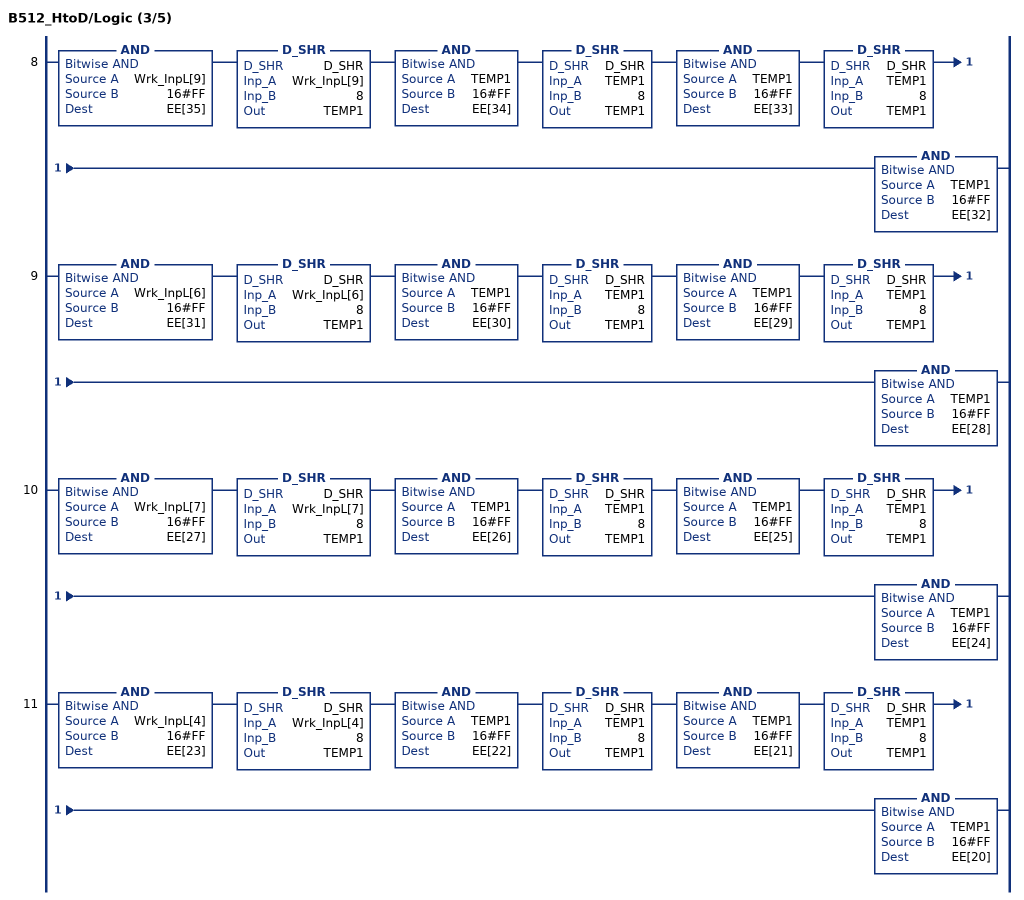
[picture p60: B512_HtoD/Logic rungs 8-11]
   8: AND(Wrk_InpL[9],16#FF,EE[35])D_SHR(D_SHR,Wrk_InpL[9],8,TEMP1)AND(TEMP1,16#FF,EE[34])D_SHR(D_SHR,TEMP1,8,TEMP1)AND(TEMP1,16#FF,EE[33])D_SHR(D_SHR,TEMP1,8,TEMP1)AND(TEMP1,16#FF,EE[32]);
   9: AND(Wrk_InpL[6],16#FF,EE[31])D_SHR(D_SHR,Wrk_InpL[6],8,TEMP1)AND(TEMP1,16#FF,EE[30])D_SHR(D_SHR,TEMP1,8,TEMP1)AND(TEMP1,16#FF,EE[29])D_SHR(D_SHR,TEMP1,8,TEMP1)AND(TEMP1,16#FF,EE[28]);
   10: AND(Wrk_InpL[7],16#FF,EE[27])D_SHR(D_SHR,Wrk_InpL[7],8,TEMP1)AND(TEMP1,16#FF,EE[26])D_SHR(D_SHR,TEMP1,8,TEMP1)AND(TEMP1,16#FF,EE[25])D_SHR(D_SHR,TEMP1,8,TEMP1)AND(TEMP1,16#FF,EE[24]);
   11: AND(Wrk_InpL[4],16#FF,EE[23])D_SHR(D_SHR,Wrk_InpL[4],8,TEMP1)AND(TEMP1,16#FF,EE[22])D_SHR(D_SHR,TEMP1,8,TEMP1)AND(TEMP1,16#FF,EE[21])D_SHR(D_SHR,TEMP1,8,TEMP1)AND(TEMP1,16#FF,EE[20]);
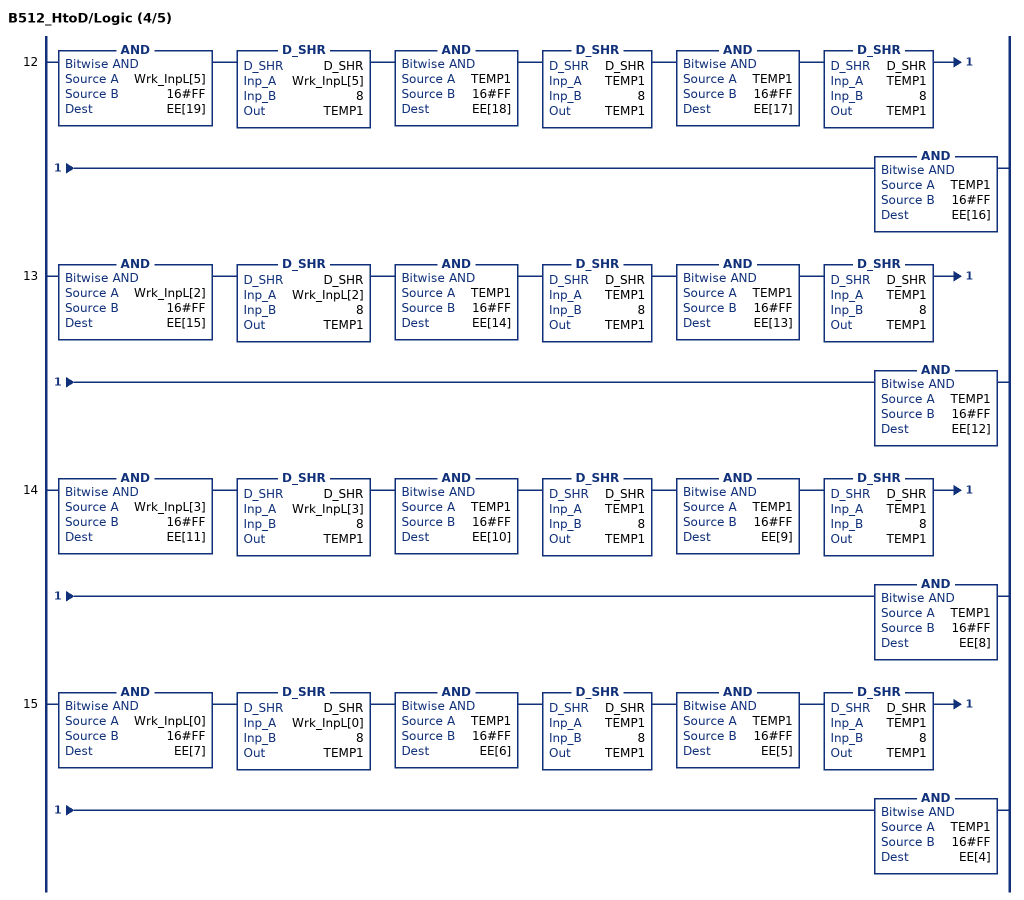
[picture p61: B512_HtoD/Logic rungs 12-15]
   12: AND(Wrk_InpL[5],16#FF,EE[19])D_SHR(D_SHR,Wrk_InpL[5],8,TEMP1)AND(TEMP1,16#FF,EE[18])D_SHR(D_SHR,TEMP1,8,TEMP1)AND(TEMP1,16#FF,EE[17])D_SHR(D_SHR,TEMP1,8,TEMP1)AND(TEMP1,16#FF,EE[16]);
   13: AND(Wrk_InpL[2],16#FF,EE[15])D_SHR(D_SHR,Wrk_InpL[2],8,TEMP1)AND(TEMP1,16#FF,EE[14])D_SHR(D_SHR,TEMP1,8,TEMP1)AND(TEMP1,16#FF,EE[13])D_SHR(D_SHR,TEMP1,8,TEMP1)AND(TEMP1,16#FF,EE[12]);
   14: AND(Wrk_InpL[3],16#FF,EE[11])D_SHR(D_SHR,Wrk_InpL[3],8,TEMP1)AND(TEMP1,16#FF,EE[10])D_SHR(D_SHR,TEMP1,8,TEMP1)AND(TEMP1,16#FF,EE[9])D_SHR(D_SHR,TEMP1,8,TEMP1)AND(TEMP1,16#FF,EE[8]);
   15: AND(Wrk_InpL[0],16#FF,EE[7])D_SHR(D_SHR,Wrk_InpL[0],8,TEMP1)AND(TEMP1,16#FF,EE[6])D_SHR(D_SHR,TEMP1,8,TEMP1)AND(TEMP1,16#FF,EE[5])D_SHR(D_SHR,TEMP1,8,TEMP1)AND(TEMP1,16#FF,EE[4]);
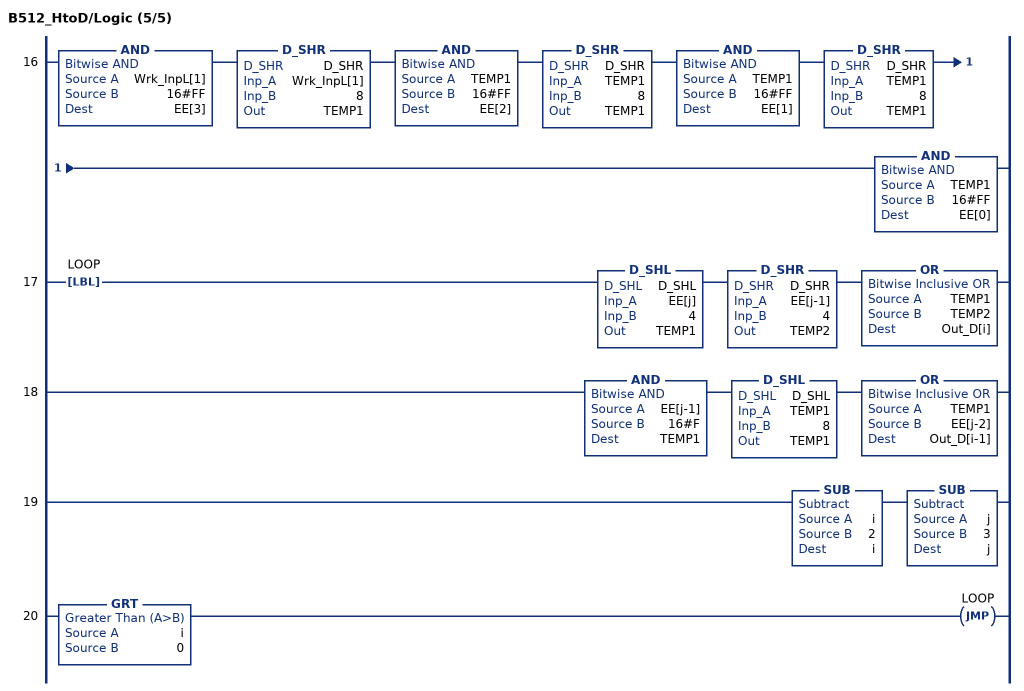
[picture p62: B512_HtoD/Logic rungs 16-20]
   16: AND(Wrk_InpL[1],16#FF,EE[3])D_SHR(D_SHR,Wrk_InpL[1],8,TEMP1)AND(TEMP1,16#FF,EE[2])D_SHR(D_SHR,TEMP1,8,TEMP1)AND(TEMP1,16#FF,EE[1])D_SHR(D_SHR,TEMP1,8,TEMP1)AND(TEMP1,16#FF,EE[0]);
   17: LBL(LOOP)D_SHL(D_SHL,EE[j],4,TEMP1)D_SHR(D_SHR,EE[j-1],4,TEMP2)OR(TEMP1,TEMP2,Out_D[i]);
   18: AND(EE[j-1],16#F,TEMP1)D_SHL(D_SHL,TEMP1,8,TEMP1)OR(TEMP1,EE[j-2],Out_D[i-1]);
   19: SUB(i,2,i)SUB(j,3,j);
   20: GRT(i,0)JMP(LOOP);
END_ROUTINE
END_ADD_ON_INSTRUCTION

ADD_ON_INSTRUCTION L_ADD   (* revision 1.0 00 Release, vendor Rockwell Automation *)
// Add (64-bit)
// Revision note:
// Initial Release
// Help:
// Adds two LINT (signed 64-bit) values and returns a LINT (signed 64-bit) sum.
// Also provides math status bits for Carry, Negative, Overflow and Zero result
// (equivalent to built-in S:C, S:N, S:V, S:Z).
VAR_IN_OUT
   Inp_A : LINT; {required}   // First Addend, 64-bit Integer
   Inp_B : LINT; {required}   // Second Addend, 64-bit Integer
   Out : LINT; {required}   // Sum, 64-bit Integer
END_VAR
VAR_OUTPUT
   Sts_C : BOOL; {access Read Only, visible}   // Carry result
   Sts_N : BOOL; {access Read Only, visible}   // Negative result
   Sts_V : BOOL; {access Read Only, visible}   // Overflow result
   Sts_Z : BOOL; {access Read Only, visible}   // Zero result
END_VAR
VAR
   Wrk_Sum : DINT[3];   // 20- and 24-bit fields of Out (sum)
   Wrk_B : DINT[3];   // 20- and 24-bit fields of Inp_B
   Wrk_A : DINT[3];   // 20- and 24-bit fields of Inp_A
   Wrk_Out : DINT[2];   // Output as two 32-bit DINTs
   Wrk_InpB : DINT[2];   // Input B as two 32-bit DINTs
   Wrk_InpA : DINT[2];   // Input A as two 32-bit DINTs
END_VAR

ROUTINE Logic   (* ladder *)
// Do 64-bit addition
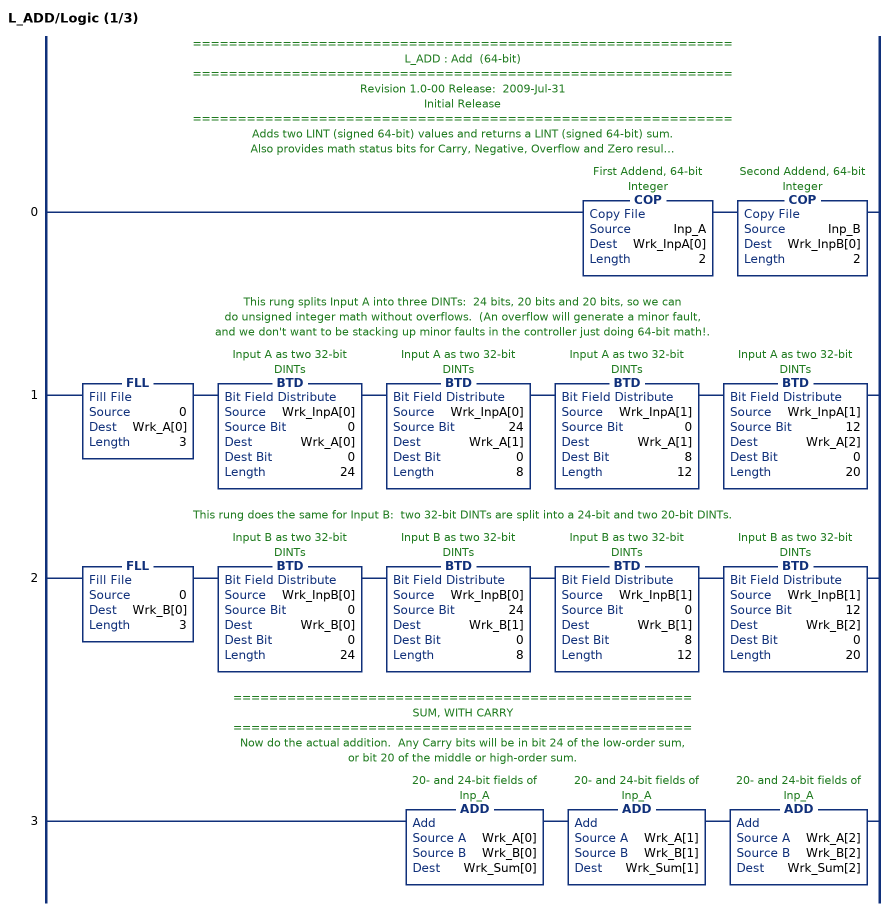
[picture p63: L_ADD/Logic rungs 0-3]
   // ============================================================
   // L_ADD : Add  (64-bit)
   // ============================================================
   // Revision 1.0-00 Release:  2009-Jul-31
   // Initial Release
   // ============================================================
   // Adds two LINT (signed 64-bit) values and returns a LINT (signed 64-bit) sum.
   // Also provides math status bits for Carry, Negative, Overflow and Zero result
   // (equivalent to built-in S:C, S:N, S:V, S:Z).
   // This instruction breaks the LINT addends into three DINTs
   // (24 bits, 20 bits and 20 bits) to do the math in order to
   // avoid generating a Controller MINOR FAULT on overflow.
   // (Sample code provided in RSLogix 5000 Online Help is much
   // smaller and faster, but causes numerous Minor Faults on
   // Overflows -- S:V -- on the low-order sum!  The controller must
   // take time to log the minor faults, and many users do not want to see
   // Minor Faults on normal math operations.  See the RSLogix 5000
   // Help Topic "Arithmetic Status Flags" for more information.)
   // ===================================================
   // CONVERT LINTs TO DINTs
   // ===================================================
   // These COPies take the input LINTs and break them into pairs of DINTs so we can do math on them.
   // Logix V17 has a LINT data type, but math instructions (and AOI Input and Output Parameters) don't support LINT.
   0: COP(Inp_A,Wrk_InpA[0],2)COP(Inp_B,Wrk_InpB[0],2);
   // This rung splits Input A into three DINTs:  24 bits, 20 bits and 20 bits, so we can
   // do unsigned integer math without overflows.  (An overflow will generate a minor fault,
   // and we don't want to be stacking up minor faults in the controller just doing 64-bit math!.
   1: FLL(0,Wrk_A[0],3)BTD(Wrk_InpA[0],0,Wrk_A[0],0,24)BTD(Wrk_InpA[0],24,Wrk_A[1],0,8)BTD(Wrk_InpA[1],0,Wrk_A[1],8,12)BTD(Wrk_InpA[1],12,Wrk_A[2],0,20);
   // This rung does the same for Input B:  two 32-bit DINTs are split into a 24-bit and two 20-bit DINTs.
   2: FLL(0,Wrk_B[0],3)BTD(Wrk_InpB[0],0,Wrk_B[0],0,24)BTD(Wrk_InpB[0],24,Wrk_B[1],0,8)BTD(Wrk_InpB[1],0,Wrk_B[1],8,12)BTD(Wrk_InpB[1],12,Wrk_B[2],0,20);
   // ===================================================
   // SUM, WITH CARRY
   // ===================================================
   // Now do the actual addition.  Any Carry bits will be in bit 24 of the low-order sum,
   // or bit 20 of the middle or high-order sum.
   3: ADD(Wrk_A[0],Wrk_B[0],Wrk_Sum[0])ADD(Wrk_A[1],Wrk_B[1],Wrk_Sum[1])ADD(Wrk_A[2],Wrk_B[2],Wrk_Sum[2]);
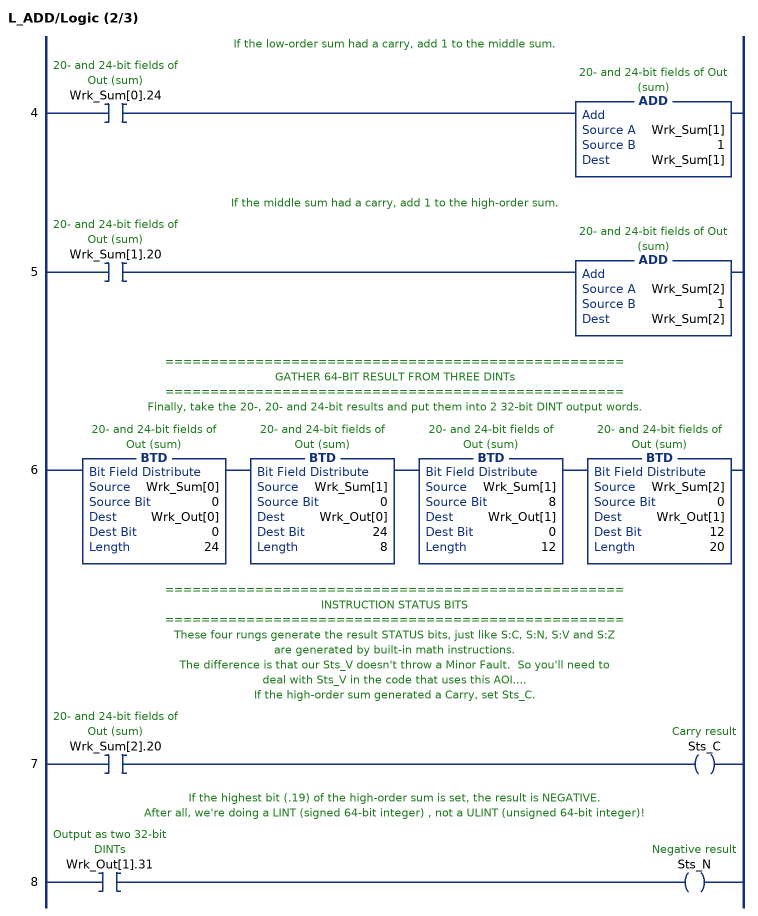
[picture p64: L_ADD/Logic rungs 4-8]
   // If the low-order sum had a carry, add 1 to the middle sum.
   4: XIC(Wrk_Sum[0].24)ADD(Wrk_Sum[1],1,Wrk_Sum[1]);
   // If the middle sum had a carry, add 1 to the high-order sum.
   5: XIC(Wrk_Sum[1].20)ADD(Wrk_Sum[2],1,Wrk_Sum[2]);
   // ===================================================
   // GATHER 64-BIT RESULT FROM THREE DINTs
   // ===================================================
   // Finally, take the 20-, 20- and 24-bit results and put them into 2 32-bit DINT output words.
   6: BTD(Wrk_Sum[0],0,Wrk_Out[0],0,24)BTD(Wrk_Sum[1],0,Wrk_Out[0],24,8)BTD(Wrk_Sum[1],8,Wrk_Out[1],0,12)BTD(Wrk_Sum[2],0,Wrk_Out[1],12,20);
   // ===================================================
   // INSTRUCTION STATUS BITS
   // ===================================================
   // These four rungs generate the result STATUS bits, just like S:C, S:N, S:V and S:Z
   // are generated by built-in math instructions.
   // The difference is that our Sts_V doesn't throw a Minor Fault.  So you'll need to
   // deal with Sts_V in the code that uses this AOI....
   // If the high-order sum generated a Carry, set Sts_C.
   7: XIC(Wrk_Sum[2].20)OTE(Sts_C);
   // If the highest bit (.19) of the high-order sum is set, the result is NEGATIVE.
   // After all, we're doing a LINT (signed 64-bit integer) , not a ULINT (unsigned 64-bit integer)!
   8: XIC(Wrk_Out[1].31)OTE(Sts_N);
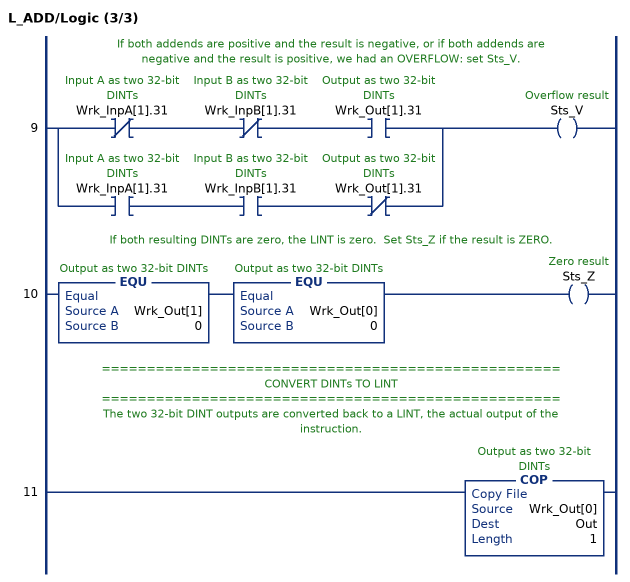
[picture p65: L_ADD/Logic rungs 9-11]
   // If both addends are positive and the result is negative, or if both addends are
   // negative and the result is positive, we had an OVERFLOW: set Sts_V.
   9: [XIO(Wrk_InpA[1].31) XIO(Wrk_InpB[1].31) XIC(Wrk_Out[1].31) ,XIC(Wrk_InpA[1].31) XIC(Wrk_InpB[1].31) XIO(Wrk_Out[1].31) ]OTE(Sts_V);
   // If both resulting DINTs are zero, the LINT is zero.  Set Sts_Z if the result is ZERO.
   10: EQU(Wrk_Out[1],0)EQU(Wrk_Out[0],0)OTE(Sts_Z);
   // ===================================================
   // CONVERT DINTs TO LINT
   // ===================================================
   // The two 32-bit DINT outputs are converted back to a LINT, the actual output of the instruction.
   11: COP(Wrk_Out[0],Out,1);
END_ROUTINE
END_ADD_ON_INSTRUCTION

ADD_ON_INSTRUCTION L_AND   (* revision 1.0 00 Release, vendor Rockwell Automation *)
// Bitwise AND (64-bit)
// Revision note:
// Initial Release
// Help:
// This instruction returns the bitwise Logical AND (output bit true if both corresponding
// input bits true) of two input 64-bit integers (LINTs), into an output 64-bit integer.
VAR_IN_OUT
   Inp_A : LINT; {required}   // Input A
   Inp_B : LINT; {required}   // Input B
   Out : LINT; {required}   // Output = Input A & Input B
END_VAR
VAR
   Wrk_Out : DINT[2];   // Output as two 32-bit DINTs
   Wrk_InpB : DINT[2];   // Input B as two 32-bit DINTs
   Wrk_InpA : DINT[2];   // Input A as two 32-bit DINTs
END_VAR

ROUTINE Logic   (* ladder *)
// Perform 64-bit bitwise logical AND
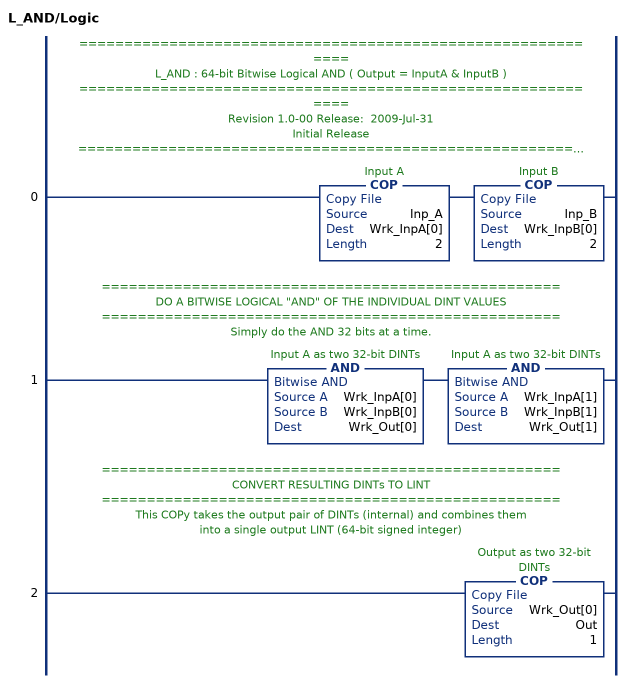
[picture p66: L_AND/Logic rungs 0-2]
   // ============================================================
   // L_AND : 64-bit Bitwise Logical AND ( Output = InputA & InputB )
   // ============================================================
   // Revision 1.0-00 Release:  2009-Jul-31
   // Initial Release
   // ============================================================
   // Returns the bitwise Logical AND of the input 64-bit integer (LINT) values.
   // This rung breaks each LINT input into two DINTs
   // (32-bit signed each) to do the logical AND function.
   // ===================================================
   // CONVERT LINTs TO DINTs
   // ===================================================
   // These COPies take the input LINT values and break them into a pair of DINTs each.
   0: COP(Inp_A,Wrk_InpA[0],2)COP(Inp_B,Wrk_InpB[0],2);
   // ===================================================
   // DO A BITWISE LOGICAL "AND" OF THE INDIVIDUAL DINT VALUES
   // ===================================================
   // Simply do the AND 32 bits at a time.
   1: AND(Wrk_InpA[0],Wrk_InpB[0],Wrk_Out[0])AND(Wrk_InpA[1],Wrk_InpB[1],Wrk_Out[1]);
   // ===================================================
   // CONVERT RESULTING DINTs TO LINT
   // ===================================================
   // This COPy takes the output pair of DINTs (internal) and combines them
   // into a single output LINT (64-bit signed integer)
   2: COP(Wrk_Out[0],Out,1);
END_ROUTINE
END_ADD_ON_INSTRUCTION

ADD_ON_INSTRUCTION L_NOT   (* revision 1.0 00 Release, vendor Rockwell Automation *)
// Bitwise NOT (64-bit)
// Revision note:
// Initial Release
// Help:
// This instruction returns the bitwise Logical NOT (inverse or 1's complement)
// of an input 64-bit integer (LINT) value.  (It flips all the bits.)
VAR_IN_OUT
   Inp : LINT; {required}   // Input
   Out : LINT; {required}   // Output = - Input
END_VAR
VAR
   Wrk : DINT[2];   // 32-bit portions of Input
END_VAR

ROUTINE Logic   (* ladder *)
// Perform a bitwise logical NOT (invert)
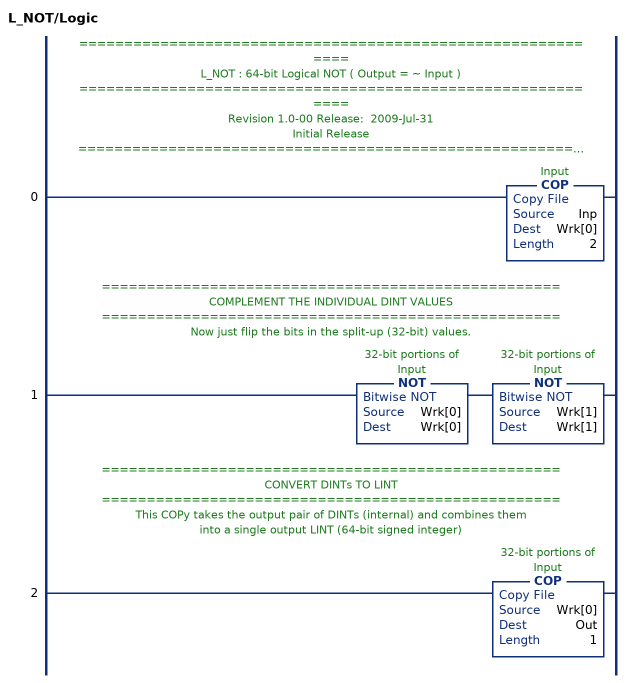
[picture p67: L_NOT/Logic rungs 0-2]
   // ============================================================
   // L_NOT : 64-bit Logical NOT ( Output = ~ Input )
   // ============================================================
   // Revision 1.0-00 Release:  2009-Jul-31
   // Initial Release
   // ============================================================
   // Returns the Logical NOT (1's complement, all bits flipped)
   // of the input 64-bit integer (LINT) value.
   // This instruction breaks the LINT input into two DINTs
   // (32-bit signed each) to do the inverting.
   // ===================================================
   // CONVERT LINT TO DINTs
   // ===================================================
   // This COPy takes the input LINT and breaks it into a pair of DINTs.
   0: COP(Inp,Wrk[0],2);
   // ===================================================
   // COMPLEMENT THE INDIVIDUAL DINT VALUES
   // ===================================================
   // Now just flip the bits in the split-up (32-bit) values.
   1: NOT(Wrk[0],Wrk[0])NOT(Wrk[1],Wrk[1]);
   // ===================================================
   // CONVERT DINTs TO LINT
   // ===================================================
   // This COPy takes the output pair of DINTs (internal) and combines them
   // into a single output LINT (64-bit signed integer)
   2: COP(Wrk[0],Out,1);
END_ROUTINE
END_ADD_ON_INSTRUCTION

ADD_ON_INSTRUCTION L_ROTR   (* revision 1.0, vendor Ken Fischer, NSWC PL, C512 *)
// LINT circular right shift (rotation) of the 64-bit argument Inp_A by Inp_B bits
// Revision note:
// Initial Release
VAR_IN_OUT
   Inp_A : LINT; {required}   // 64-bit Integer to be right circular rotated
END_VAR
VAR_INPUT
   Inp_B : INT; {required}   // Number of Inp_A bit rotations
END_VAR
VAR_IN_OUT
   Out : LINT; {required}   // Result
END_VAR
VAR
   Wrk_InpA : DINT[2];   // Input A as two 32-bit DINTs
   BSR_Cntrl : CONTROL := (LEN := 64);
   Source_Bit : BOOL;
   ONS : BOOL;
END_VAR

ROUTINE Logic   (* ladder *)
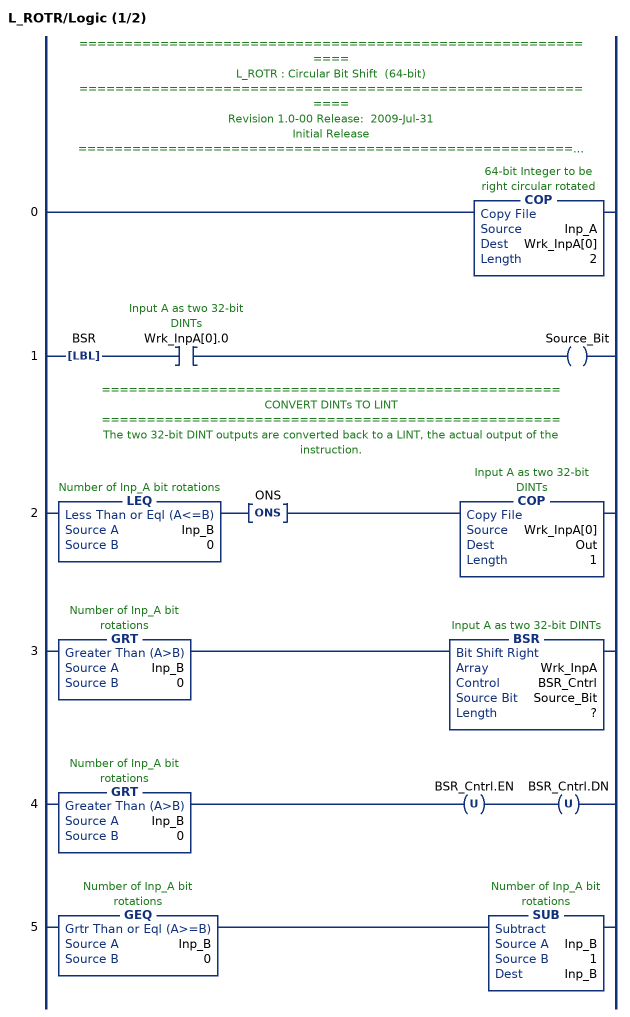
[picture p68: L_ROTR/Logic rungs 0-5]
   // ============================================================
   // L_ROTR : Circular Bit Shift  (64-bit)
   // ============================================================
   // Revision 1.0-00 Release:  2009-Jul-31
   // Initial Release
   // ============================================================
   // Performs a circular right shift rotation of the 64-bit argument Inp_A by the
   // number of bits defined in the 16-bit argument Inp_B.
   // ===================================================
   // CONVERT LINTs TO DINTs
   // ===================================================
   // These COPies take the input LINTs and break them into pairs of DINTs so we can do math on them.
   // Logix V17 has a LINT data type, but math instructions (and AOI Input and Output Parameters) don't support LINT.
   0: COP(Inp_A,Wrk_InpA[0],2);
   1: LBL(BSR)XIC(Wrk_InpA[0].0)OTE(Source_Bit);
   // ===================================================
   // CONVERT DINTs TO LINT
   // ===================================================
   // The two 32-bit DINT outputs are converted back to a LINT, the actual output of the instruction.
   2: LEQ(Inp_B,0)ONS(ONS)COP(Wrk_InpA[0],Out,1);
   3: GRT(Inp_B,0)BSR(Wrk_InpA,BSR_Cntrl,Source_Bit,?);
   4: GRT(Inp_B,0)OTU(BSR_Cntrl.EN)OTU(BSR_Cntrl.DN);
   5: GEQ(Inp_B,0)SUB(Inp_B,1,Inp_B);
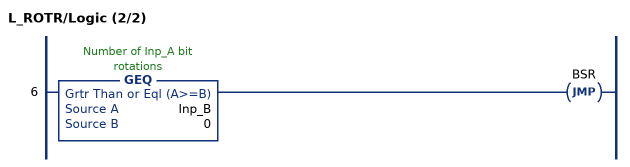
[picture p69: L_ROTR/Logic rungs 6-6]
   6: GEQ(Inp_B,0)JMP(BSR);
END_ROUTINE
END_ADD_ON_INSTRUCTION

ADD_ON_INSTRUCTION L_SHR   (* revision 1.0, vendor Ken Fischer, NSWCPD, C512 *)
// LINT bit shift right of the 64-bit argument Inp_A by Inp_B bits with paddding by zeros on the right
// Revision note:
// Rev1.0: TBD - Initial Release
VAR_IN_OUT
   Inp_A : LINT; {required}   // 64-bit Integer to be right circular rotated
END_VAR
VAR_INPUT
   Inp_B : INT; {required}   // Number of bits to shift
END_VAR
VAR_IN_OUT
   Out : LINT; {required}   // Result
END_VAR
VAR
   BSR_Cntrl : CONTROL := (LEN := 64);
   ONS : BOOL;
   Source_Bit : BOOL;
   Wrk_InpA : DINT[2];   // Input A as two 32-bit DINTs
END_VAR

ROUTINE Logic   (* ladder *)
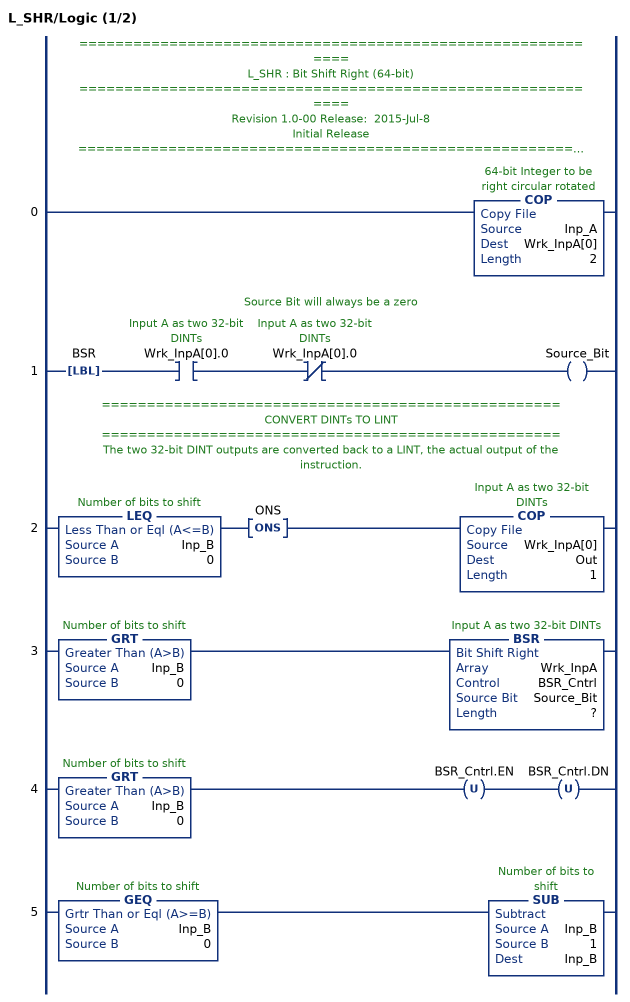
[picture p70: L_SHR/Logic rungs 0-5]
   // ============================================================
   // L_SHR : Bit Shift Right (64-bit)
   // ============================================================
   // Revision 1.0-00 Release:  2015-Jul-8
   // Initial Release
   // ============================================================
   // Performs a right bit shift of the 64-bit argument Inp_A by the
   // number of bits defined in the 16-bit argument Inp_B, with padding by zeros.
   // ===================================================
   // CONVERT LINTs TO DINTs
   // ===================================================
   // These COPies take the input LINTs and break them into pairs of DINTs so we can do math on them.
   // Logix V17 has a LINT data type, but math instructions (and AOI Input and Output Parameters) don't support LINT.
   0: COP(Inp_A,Wrk_InpA[0],2);
   // Source Bit will always be a zero
   1: LBL(BSR)XIC(Wrk_InpA[0].0)XIO(Wrk_InpA[0].0)OTE(Source_Bit);
   // ===================================================
   // CONVERT DINTs TO LINT
   // ===================================================
   // The two 32-bit DINT outputs are converted back to a LINT, the actual output of the instruction.
   2: LEQ(Inp_B,0)ONS(ONS)COP(Wrk_InpA[0],Out,1);
   3: GRT(Inp_B,0)BSR(Wrk_InpA,BSR_Cntrl,Source_Bit,?);
   4: GRT(Inp_B,0)OTU(BSR_Cntrl.EN)OTU(BSR_Cntrl.DN);
   5: GEQ(Inp_B,0)SUB(Inp_B,1,Inp_B);
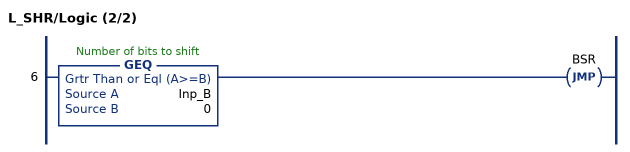
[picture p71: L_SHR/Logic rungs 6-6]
   6: GEQ(Inp_B,0)JMP(BSR);
END_ROUTINE
END_ADD_ON_INSTRUCTION

ADD_ON_INSTRUCTION L_XOR   (* revision 1.0 00 Release, vendor Rockwell Automation *)
// Bitwise XOR (64-bit)
// Revision note:
// Initial Release
// Help:
// This instruction returns the bitwise Logical XOR (exclusive OR, output
// bit true if either but NOT both of the corresponding input bits are true)
// of two input 64-bit integers (LINTs), into an output 64-bit integer.
VAR_IN_OUT
   Inp_A : LINT; {required}   // Input A
   Inp_B : LINT; {required}   // Input B
   Out : LINT; {required}   // Output = Input A | Input B
END_VAR
VAR
   Wrk_Out : DINT[2];   // Output as two 32-bit DINTs
   Wrk_InpB : DINT[2];   // Input B as two 32-bit DINTs
   Wrk_InpA : DINT[2];   // Input A as two 32-bit DINTs
END_VAR

ROUTINE Logic   (* ladder *)
// Perform bitwise logical XOR
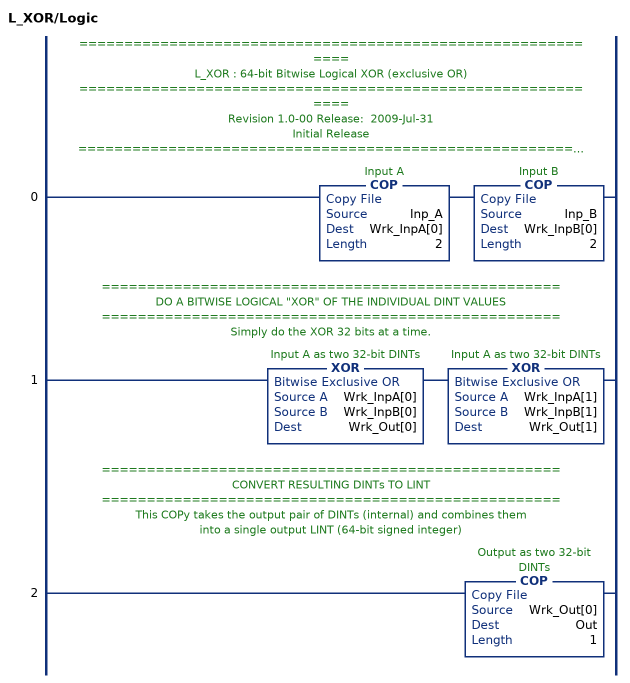
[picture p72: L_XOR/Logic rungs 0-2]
   // ============================================================
   // L_XOR : 64-bit Bitwise Logical XOR (exclusive OR)
   // ============================================================
   // Revision 1.0-00 Release:  2009-Jul-31
   // Initial Release
   // ============================================================
   // Returns the bitwise Logical XOR of the input 64-bit integer (LINT) values.
   // This rung breaks each LINT input into two DINTs
   // (32-bit signed each) to do the logical XOR function.
   // ===================================================
   // CONVERT LINTs TO DINTs
   // ===================================================
   // These COPies take the input LINT values and break them into a pair of DINTs each.
   0: COP(Inp_A,Wrk_InpA[0],2)COP(Inp_B,Wrk_InpB[0],2);
   // ===================================================
   // DO A BITWISE LOGICAL "XOR" OF THE INDIVIDUAL DINT VALUES
   // ===================================================
   // Simply do the XOR 32 bits at a time.
   1: XOR(Wrk_InpA[0],Wrk_InpB[0],Wrk_Out[0])XOR(Wrk_InpA[1],Wrk_InpB[1],Wrk_Out[1]);
   // ===================================================
   // CONVERT RESULTING DINTs TO LINT
   // ===================================================
   // This COPy takes the output pair of DINTs (internal) and combines them
   // into a single output LINT (64-bit signed integer)
   2: COP(Wrk_Out[0],Out,1);
END_ROUTINE
END_ADD_ON_INSTRUCTION

ADD_ON_INSTRUCTION SHA512_SEQ   (* revision 1.0 20170916, vendor Kenneth A. Fischer *)
// Generates SHA 512 hash of data.
// Revision note:
// Rev1.0: 20170916 - Initial Release
VAR_IN_OUT
   Inp_MSG : LINT[1600]; {required}
END_VAR
VAR_INPUT
   Inp_LEN : DINT; {required}   // LENGTH INPUT OF MSG IN NUMBER OF LINTS
END_VAR
VAR_IN_OUT
   Out_HASH : LINT[8]; {required}
        [0]   // HashBuffer_A
        [1]   // HashBuffer_B
        [2]   // HashBuffer_C
        [3]   // HashBuffer_D
        [4]   // HashBuffer_E
        [5]   // HashBuffer_F
        [6]   // HashBuffer_G
        [7]   // HashBuffer_H
END_VAR
VAR_OUTPUT
   SEQCTRL_DN : BOOL; {access Read Only}   // Complete
END_VAR
VAR_INPUT
   SEQCTRL_RESET : BOOL;   // Resets Point Multiplication if Toggled True
END_VAR
VAR_OUTPUT
   SEQCTRL_STEP : INT; {access Read Only}
END_VAR
VAR
   SEQCTRL_CMD : DINT;
   SEQCTRL_CMD_TABLE : DINT[100];
   SEQCTRL_DONE : DINT;
   SEQCTRL_NEXT_STEP : INT;
   i : INT;
   ALWAYS_OFF : BOOL;
   CondFunc : LINT;
   CondFunc_tmp : LINT[3];
   HashBuffer_A : LINT;
   HashBuffer_B : LINT;
   HashBuffer_C : LINT;
   HashBuffer_D : LINT;
   HashBuffer_E : LINT;
   HashBuffer_F : LINT;
   HashBuffer_G : LINT;
   HashBuffer_H : LINT;
   HashBufferInput_A : LINT;
   HashBufferInput_B : LINT;
   HashBufferInput_C : LINT;
   HashBufferInput_D : LINT;
   HashBufferInput_E : LINT;
   HashBufferInput_F : LINT;
   HashBufferInput_G : LINT;
   HashBufferInput_H : LINT;
   M : INT;   // MESSAGE INCREMENTS
   t : INT;
   K : LINT[85];
   L_ADD : L_ADD;
   L_ADD1 : L_ADD;
   L_AND : L_AND;
   L_NOT : L_NOT;
   L_ROTR : L_ROTR;
   L_SHR : L_SHR;
   L_XOR : L_XOR;
   LENGTH_BITS : DINT;   // LENGTH OF MSG IN BITS
   LENGTH_MODULO : DINT;
   MajFunc : LINT;
   NUM_PADDING_BITS : DINT;   // NUMBER OF BITS NEEDED FOR PADDING
   NUM_PADDING_LINTS : DINT;   // NUMBER OF LINTS NEEDED FOR PADDING
   PADDING_COUNTER : DINT;
   Sigma0 : LINT;
   Sigma1 : LINT;
   SigmaA : LINT;
   SigmaE : LINT;
   x : INT;
   j : INT;
   T1 : LINT;
   T2 : LINT;
   tmp : LINT[20];
   tmp1 : DINT;
   tmp2 : DINT;
   TOTAL_MSG_LENGTH_MINUS_16 : DINT;
   W : LINT[85];   // MESSAGE SCHEDULE
   Wrk : DINT[2];
   TEMP : DINT;
END_VAR

ROUTINE Logic   (* ladder *)
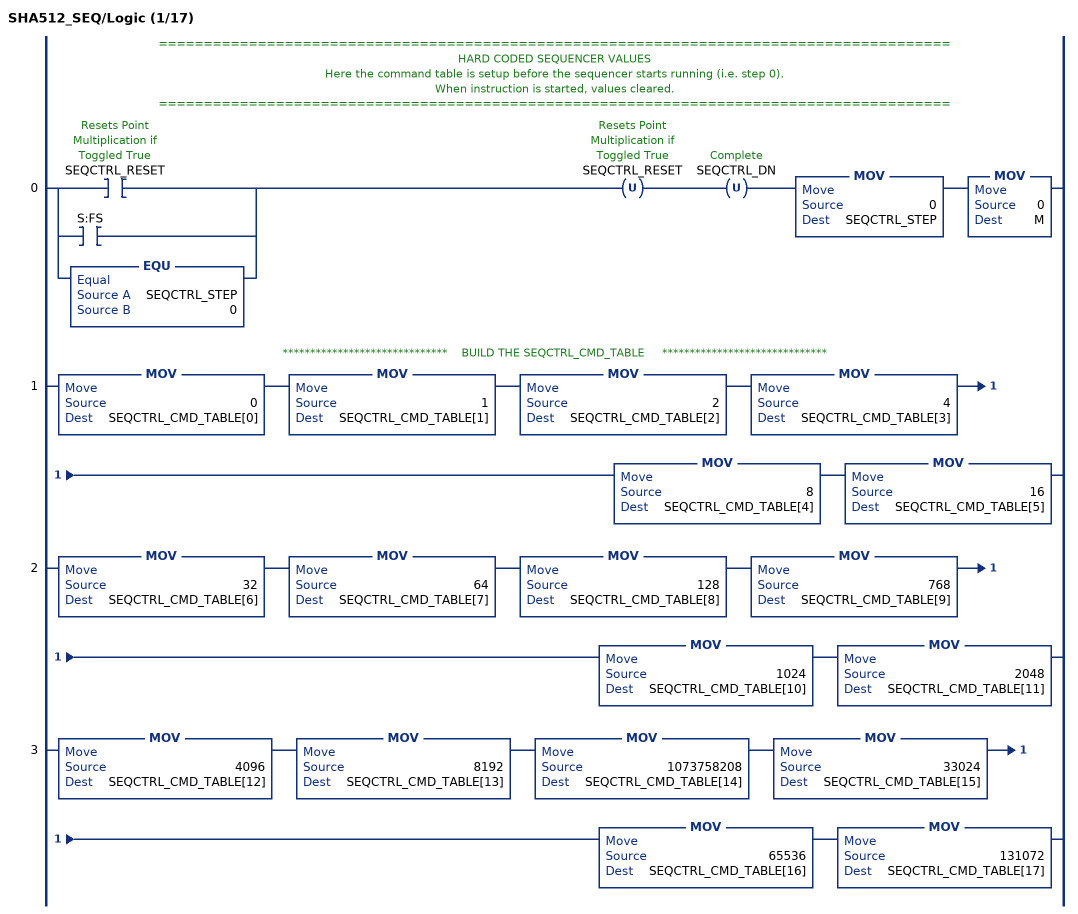
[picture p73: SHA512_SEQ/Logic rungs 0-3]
   // ========================================================================================
   // HARD CODED SEQUENCER VALUES
   // Here the command table is setup before the sequencer starts running (i.e. step 0).
   // When instruction is started, values cleared.
   // ========================================================================================
   0: [[XIC(SEQCTRL_RESET) ,XIC(S:FS) ] ,EQU(SEQCTRL_STEP,0) ]OTU(SEQCTRL_RESET)OTU(SEQCTRL_DN)MOV(0,SEQCTRL_STEP)MOV(0,M);
   // ******************************    BUILD THE SEQCTRL_CMD_TABLE     ******************************
   1: MOV(0,SEQCTRL_CMD_TABLE[0])MOV(1,SEQCTRL_CMD_TABLE[1])MOV(2,SEQCTRL_CMD_TABLE[2])MOV(4,SEQCTRL_CMD_TABLE[3])MOV(8,SEQCTRL_CMD_TABLE[4])MOV(16,SEQCTRL_CMD_TABLE[5]);
   2: MOV(32,SEQCTRL_CMD_TABLE[6])MOV(64,SEQCTRL_CMD_TABLE[7])MOV(128,SEQCTRL_CMD_TABLE[8])MOV(768,SEQCTRL_CMD_TABLE[9])MOV(1024,SEQCTRL_CMD_TABLE[10])MOV(2048,SEQCTRL_CMD_TABLE[11]);
   3: MOV(4096,SEQCTRL_CMD_TABLE[12])MOV(8192,SEQCTRL_CMD_TABLE[13])MOV(1073758208,SEQCTRL_CMD_TABLE[14])MOV(33024,SEQCTRL_CMD_TABLE[15])MOV(65536,SEQCTRL_CMD_TABLE[16])MOV(131072,SEQCTRL_CMD_TABLE[17]);
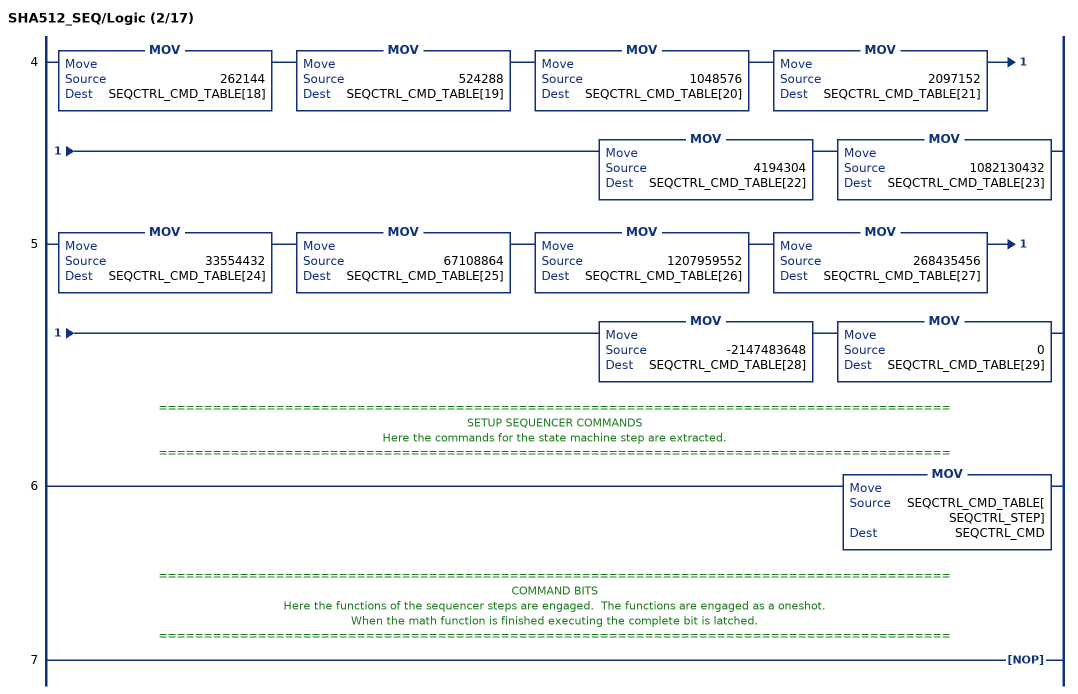
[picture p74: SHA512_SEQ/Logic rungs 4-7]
   4: MOV(262144,SEQCTRL_CMD_TABLE[18])MOV(524288,SEQCTRL_CMD_TABLE[19])MOV(1048576,SEQCTRL_CMD_TABLE[20])MOV(2097152,SEQCTRL_CMD_TABLE[21])MOV(4194304,SEQCTRL_CMD_TABLE[22])MOV(1082130432,SEQCTRL_CMD_TABLE[23]);
   5: MOV(33554432,SEQCTRL_CMD_TABLE[24])MOV(67108864,SEQCTRL_CMD_TABLE[25])MOV(1207959552,SEQCTRL_CMD_TABLE[26])MOV(268435456,SEQCTRL_CMD_TABLE[27])MOV(-2147483648,SEQCTRL_CMD_TABLE[28])MOV(0,SEQCTRL_CMD_TABLE[29]);
   // ========================================================================================
   // SETUP SEQUENCER COMMANDS
   // Here the commands for the state machine step are extracted.
   // ========================================================================================
   6: MOV(SEQCTRL_CMD_TABLE[SEQCTRL_STEP],SEQCTRL_CMD);
   // ========================================================================================
   // COMMAND BITS
   // Here the functions of the sequencer steps are engaged.  The functions are engaged as a oneshot.
   // When the math function is finished executing the complete bit is latched.
   // ========================================================================================
   7: NOP();
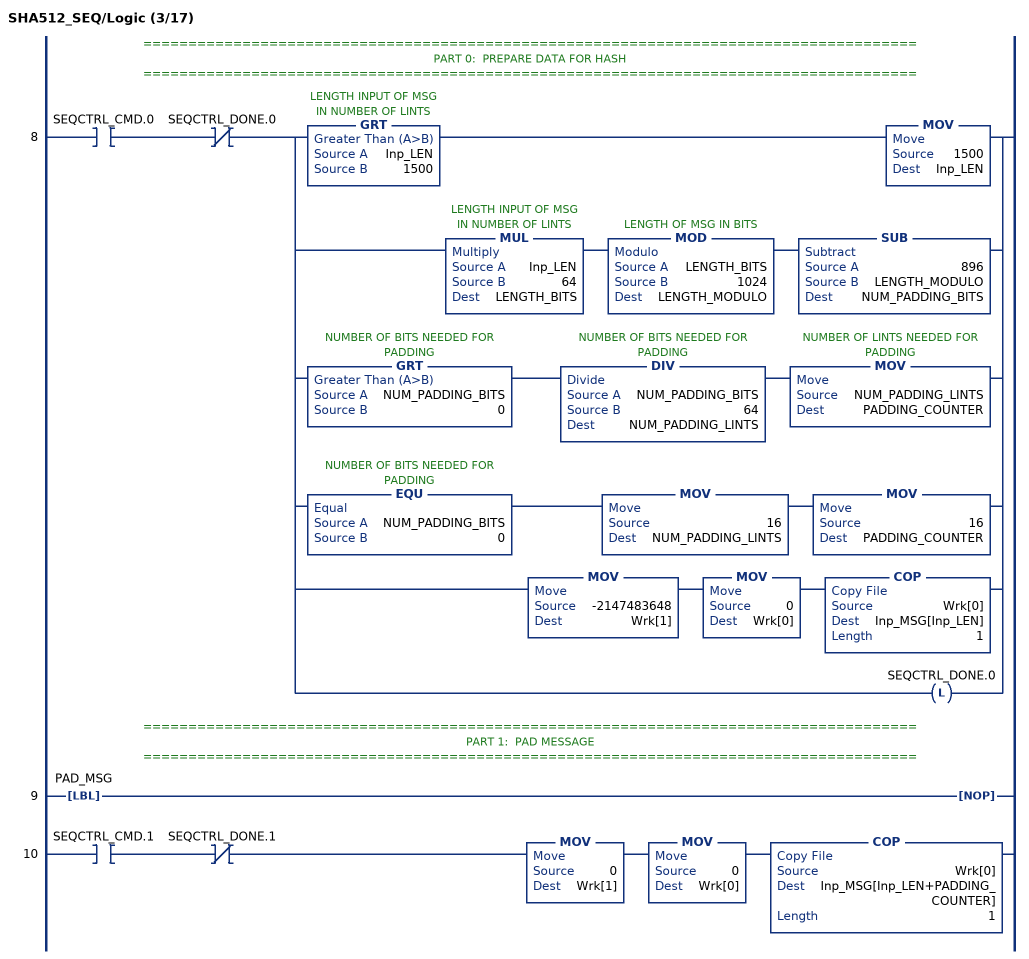
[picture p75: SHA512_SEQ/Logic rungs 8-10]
   // ======================================================================================
   // PART 0:  PREPARE DATA FOR HASH
   // ======================================================================================
   8: XIC(SEQCTRL_CMD.0)XIO(SEQCTRL_DONE.0)[GRT(Inp_LEN,1500) MOV(1500,Inp_LEN) ,MUL(Inp_LEN,64,LENGTH_BITS) MOD(LENGTH_BITS,1024,LENGTH_MODULO) SUB(896,LENGTH_MODULO,NUM_PADDING_BITS) ,GRT(NUM_PADDING_BITS,0) DIV(NUM_PADDING_BITS,64,NUM_PADDING_LINTS) MOV(NUM_PADDING_LINTS,PADDING_COUNTER) ,EQU(NUM_PADDING_BITS,0) MOV(16,NUM_PADDING_LINTS) MOV(16,PADDING_COUNTER) ,MOV(-2147483648,Wrk[1]) MOV(0,Wrk[0]) COP(Wrk[0],Inp_MSG[Inp_LEN],1) ,OTL(SEQCTRL_DONE.0) ];
   // ======================================================================================
   // PART 1:  PAD MESSAGE
   // ======================================================================================
   9: LBL(PAD_MSG)NOP();
   10: XIC(SEQCTRL_CMD.1)XIO(SEQCTRL_DONE.1)MOV(0,Wrk[1])MOV(0,Wrk[0])COP(Wrk[0],Inp_MSG[Inp_LEN+PADDING_COUNTER],1);
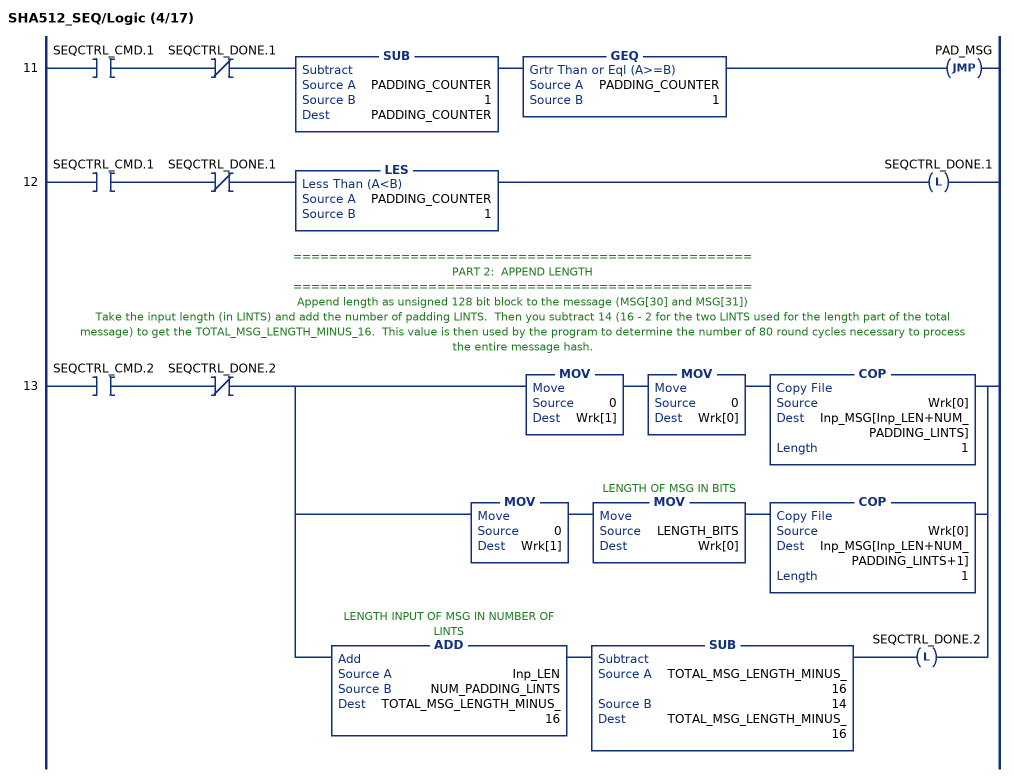
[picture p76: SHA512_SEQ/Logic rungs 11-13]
   11: XIC(SEQCTRL_CMD.1)XIO(SEQCTRL_DONE.1)SUB(PADDING_COUNTER,1,PADDING_COUNTER)GEQ(PADDING_COUNTER,1)JMP(PAD_MSG);
   12: XIC(SEQCTRL_CMD.1)XIO(SEQCTRL_DONE.1)LES(PADDING_COUNTER,1)OTL(SEQCTRL_DONE.1);
   // ===================================================
   // PART 2:  APPEND LENGTH
   // ===================================================
   // Append length as unsigned 128 bit block to the message (MSG[30] and MSG[31])
   // Take the input length (in LINTS) and add the number of padding LINTS.  Then you subtract 14 (16 - 2 for the two LINTS used for the length part of the total message) to get the TOTAL_MSG_LENGTH_MINUS_16.  This value is then used by the program to determine the number of 80 round cycles necessary to process the entire message hash.
   13: XIC(SEQCTRL_CMD.2)XIO(SEQCTRL_DONE.2)[MOV(0,Wrk[1]) MOV(0,Wrk[0]) COP(Wrk[0],Inp_MSG[Inp_LEN+NUM_PADDING_LINTS],1) ,MOV(0,Wrk[1]) MOV(LENGTH_BITS,Wrk[0]) COP(Wrk[0],Inp_MSG[Inp_LEN+NUM_PADDING_LINTS+1],1) ,ADD(Inp_LEN,NUM_PADDING_LINTS,TOTAL_MSG_LENGTH_MINUS_16) SUB(TOTAL_MSG_LENGTH_MINUS_16,14,TOTAL_MSG_LENGTH_MINUS_16) OTL(SEQCTRL_DONE.2) ];
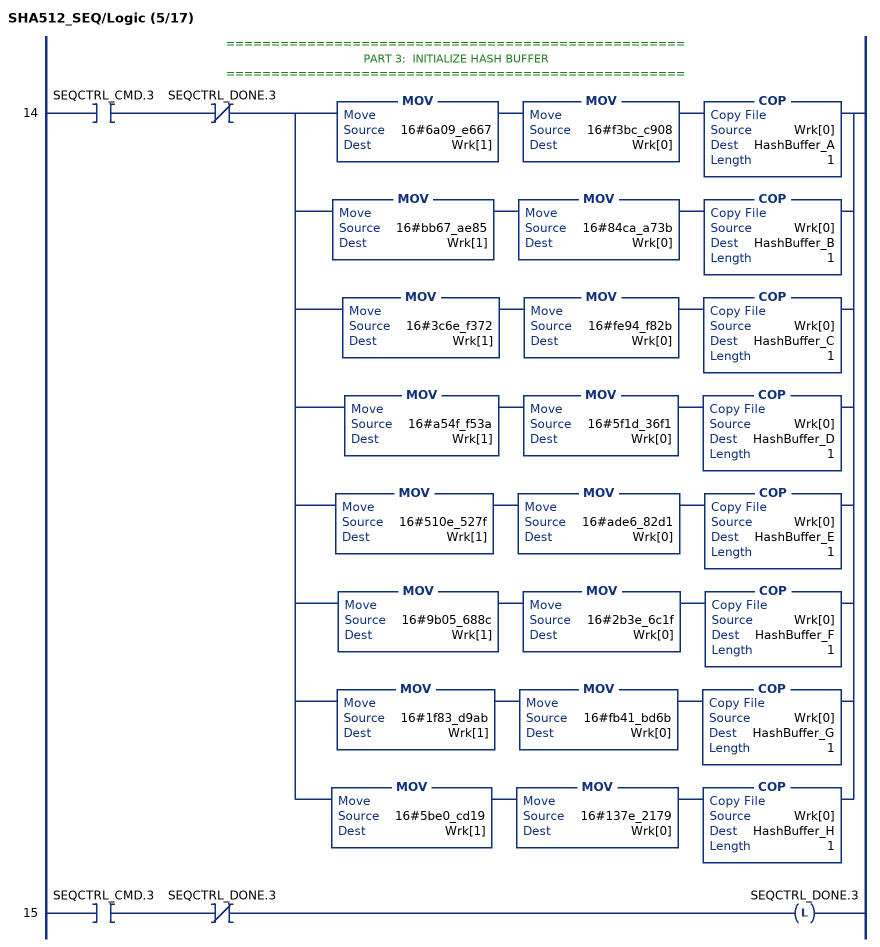
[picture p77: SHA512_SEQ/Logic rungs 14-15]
   // ===================================================
   // PART 3:  INITIALIZE HASH BUFFER
   // ===================================================
   14: XIC(SEQCTRL_CMD.3)XIO(SEQCTRL_DONE.3)[MOV(16#6a09_e667,Wrk[1]) MOV(16#f3bc_c908,Wrk[0]) COP(Wrk[0],HashBuffer_A,1) ,MOV(16#bb67_ae85,Wrk[1]) MOV(16#84ca_a73b,Wrk[0]) COP(Wrk[0],HashBuffer_B,1) ,MOV(16#3c6e_f372,Wrk[1]) MOV(16#fe94_f82b,Wrk[0]) COP(Wrk[0],HashBuffer_C,1) ,MOV(16#a54f_f53a,Wrk[1]) MOV(16#5f1d_36f1,Wrk[0]) COP(Wrk[0],HashBuffer_D,1) ,MOV(16#510e_527f,Wrk[1]) MOV(16#ade6_82d1,Wrk[0]) COP(Wrk[0],HashBuffer_E,1) ,MOV(16#9b05_688c,Wrk[1]) MOV(16#2b3e_6c1f,Wrk[0]) COP(Wrk[0],HashBuffer_F,1) ,MOV(16#1f83_d9ab,Wrk[1]) MOV(16#fb41_bd6b,Wrk[0]) COP(Wrk[0],HashBuffer_G,1) ,MOV(16#5be0_cd19,Wrk[1]) MOV(16#137e_2179,Wrk[0]) COP(Wrk[0],HashBuffer_H,1) ];
   15: XIC(SEQCTRL_CMD.3)XIO(SEQCTRL_DONE.3)OTL(SEQCTRL_DONE.3);
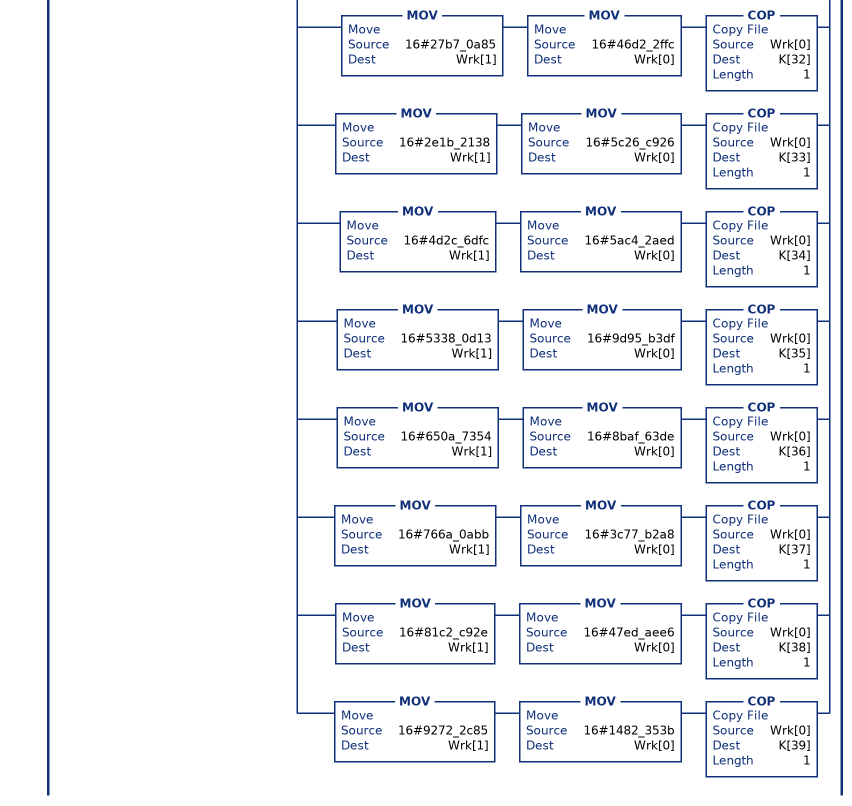
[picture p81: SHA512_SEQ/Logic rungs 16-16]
   // ===================================================
   // PART 4:  INITIALIZE K CONSTANTS - PART 1
   // ===================================================
   16: XIC(SEQCTRL_CMD.4)XIO(SEQCTRL_DONE.4)[MOV(16#428a_2f98,Wrk[1]) MOV(16#d728_ae22,Wrk[0]) COP(Wrk[0],K[0],1) ,MOV(16#7137_4491,Wrk[1]) MOV(16#23ef_65cd,Wrk[0]) COP(Wrk[0],K[1],1) ,MOV(16#b5c0_fbcf,Wrk[1]) MOV(16#ec4d_3b2f,Wrk[0]) COP(Wrk[0],K[2],1) ,MOV(16#e9b5_dba5,Wrk[1]) MOV(16#8189_dbbc,Wrk[0]) COP(Wrk[0],K[3],1) ,MOV(16#3956_c25b,Wrk[1]) MOV(16#f348_b538,Wrk[0]) COP(Wrk[0],K[4],1) ,MOV(16#59f1_11f1,Wrk[1]) MOV(16#b605_d019,Wrk[0]) COP(Wrk[0],K[5],1) ,MOV(16#923f_82a4,Wrk[1]) MOV(16#af19_4f9b,Wrk[0]) COP(Wrk[0],K[6],1) ,MOV(16#ab1c_5ed5,Wrk[1]) MOV(16#da6d_8118,Wrk[0]) COP(Wrk[0],K[7],1) ,MOV(16#d807_aa98,Wrk[1]) MOV(16#a303_0242,Wrk[0]) COP(Wrk[0],K[8],1) ,MOV(16#1283_5b01,Wrk[1]) MOV(16#4570_6fbe,Wrk[0]) COP(Wrk[0],K[9],1) ,MOV(16#2431_85be,Wrk[1]) MOV(16#4ee4_b28c,Wrk[0]) COP(Wrk[0],K[10],1) ,MOV(16#550c_7dc3,Wrk[1]) MOV(16#d5ff_b4e2,Wrk[0]) COP(Wrk[0],K[11],1) ,MOV(16#72be_5d74,Wrk[1]) MOV(16#f27b_896f,Wrk[0]) COP(Wrk[0],K[12],1) ,MOV(16#80de_b1fe,Wrk[1]) MOV(16#3b16_96b1,Wrk[0]) COP(Wrk[0],K[13],1) ,MOV(16#9bdc_06a7,Wrk[1]) MOV(16#25c7_1235,Wrk[0]) COP(Wrk[0],K[14],1) ,MOV(16#c19b_f174,Wrk[1]) MOV(16#cf69_2694,Wrk[0]) COP(Wrk[0],K[15],1) ,MOV(16#e49b_69c1,Wrk[1]) MOV(16#9ef1_4ad2,Wrk[0]) COP(Wrk[0],K[16],1) ,MOV(16#efbe_4786,Wrk[1]) MOV(16#384f_25e3,Wrk[0]) COP(Wrk[0],K[17],1) ,MOV(16#0fc1_9dc6,Wrk[1]) MOV(16#8b8c_d5b5,Wrk[0]) COP(Wrk[0],K[18],1) ,MOV(16#240c_a1cc,Wrk[1]) MOV(16#77ac_9c65,Wrk[0]) COP(Wrk[0],K[19],1) ,MOV(16#2de9_2c6f,Wrk[1]) MOV(16#592b_0275,Wrk[0]) COP(Wrk[0],K[20],1) ,MOV(16#4a74_84aa,Wrk[1]) MOV(16#6ea6_e483,Wrk[0]) COP(Wrk[0],K[21],1) ,MOV(16#5cb0_a9dc,Wrk[1]) MOV(16#bd41_fbd4,Wrk[0]) COP(Wrk[0],K[22],1) ,MOV(16#76f9_88da,Wrk[1]) MOV(16#8311_53b5,Wrk[0]) COP(Wrk[0],K[23],1) ,MOV(16#983e_5152,Wrk[1]) MOV(16#ee66_dfab,Wrk[0]) COP(Wrk[0],K[24],1) ,MOV(16#a831_c66d,Wrk[1]) MOV(16#2db4_3210,Wrk[0]) COP(Wrk[0],K[25],1) ,MOV(16#b003_27c8,Wrk[1]) MOV(16#98fb_213f,Wrk[0]) COP(Wrk[0],K[26],1) ,MOV(16#bf59_7fc7,Wrk[1]) MOV(16#beef_0ee4,Wrk[0]) COP(Wrk[0],K[27],1) ,MOV(16#c6e0_0bf3,Wrk[1]) MOV(16#3da8_8fc2,Wrk[0]) COP(Wrk[0],K[28],1) ,MOV(16#d5a7_9147,Wrk[1]) MOV(16#930a_a725,Wrk[0]) COP(Wrk[0],K[29],1) ,MOV(16#06ca_6351,Wrk[1]) MOV(16#e003_826f,Wrk[0]) COP(Wrk[0],K[30],1) ,MOV(16#1429_2967,Wrk[1]) MOV(16#0a0e_6e70,Wrk[0]) COP(Wrk[0],K[31],1) ,MOV(16#27b7_0a85,Wrk[1]) MOV(16#46d2_2ffc,Wrk[0]) COP(Wrk[0],K[32],1) ,MOV(16#2e1b_2138,Wrk[1]) MOV(16#5c26_c926,Wrk[0]) COP(Wrk[0],K[33],1) ,MOV(16#4d2c_6dfc,Wrk[1]) MOV(16#5ac4_2aed,Wrk[0]) COP(Wrk[0],K[34],1) ,MOV(16#5338_0d13,Wrk[1]) MOV(16#9d95_b3df,Wrk[0]) COP(Wrk[0],K[35],1) ,MOV(16#650a_7354,Wrk[1]) MOV(16#8baf_63de,Wrk[0]) COP(Wrk[0],K[36],1) ,MOV(16#766a_0abb,Wrk[1]) MOV(16#3c77_b2a8,Wrk[0]) COP(Wrk[0],K[37],1) ,MOV(16#81c2_c92e,Wrk[1]) MOV(16#47ed_aee6,Wrk[0]) COP(Wrk[0],K[38],1) ,MOV(16#9272_2c85,Wrk[1]) MOV(16#1482_353b,Wrk[0]) COP(Wrk[0],K[39],1) ];
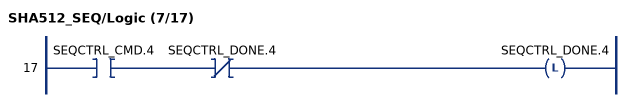
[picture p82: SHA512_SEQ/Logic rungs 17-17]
   17: XIC(SEQCTRL_CMD.4)XIO(SEQCTRL_DONE.4)OTL(SEQCTRL_DONE.4);
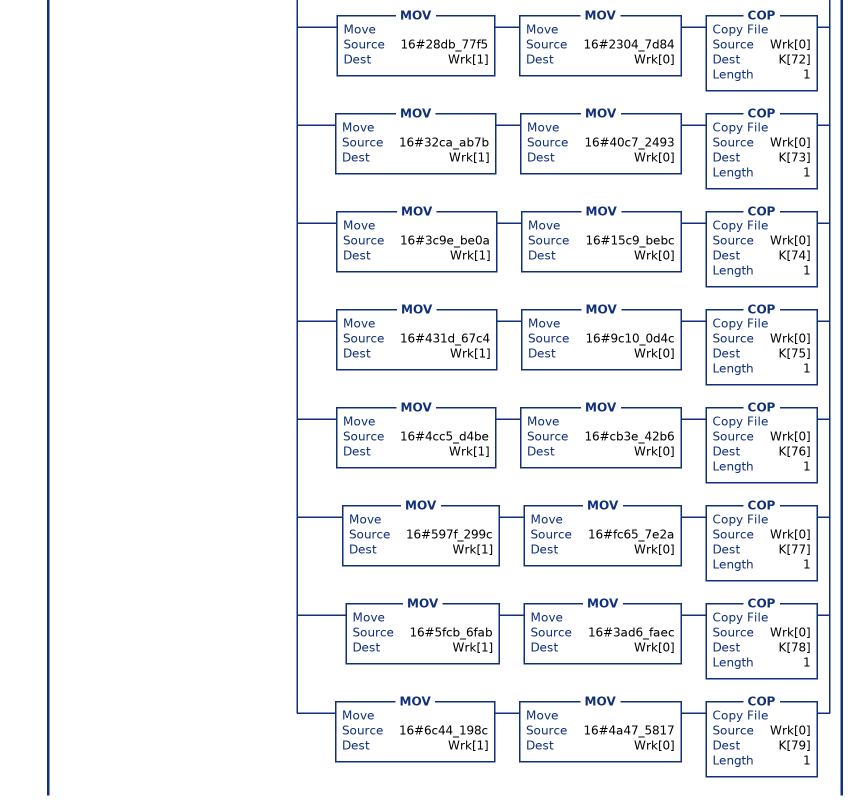
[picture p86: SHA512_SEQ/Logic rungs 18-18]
   // ===================================================
   // PART 5:  INITIALIZE K CONSTANTS - PART 2
   // ===================================================
   18: XIC(SEQCTRL_CMD.5)XIO(SEQCTRL_DONE.5)[MOV(16#a2bf_e8a1,Wrk[1]) MOV(16#4cf1_0364,Wrk[0]) COP(Wrk[0],K[40],1) ,MOV(16#a81a_664b,Wrk[1]) MOV(16#bc42_3001,Wrk[0]) COP(Wrk[0],K[41],1) ,MOV(16#c24b_8b70,Wrk[1]) MOV(16#d0f8_9791,Wrk[0]) COP(Wrk[0],K[42],1) ,MOV(16#c76c_51a3,Wrk[1]) MOV(16#0654_be30,Wrk[0]) COP(Wrk[0],K[43],1) ,MOV(16#d192_e819,Wrk[1]) MOV(16#d6ef_5218,Wrk[0]) COP(Wrk[0],K[44],1) ,MOV(16#d699_0624,Wrk[1]) MOV(16#5565_a910,Wrk[0]) COP(Wrk[0],K[45],1) ,MOV(16#f40e_3585,Wrk[1]) MOV(16#5771_202a,Wrk[0]) COP(Wrk[0],K[46],1) ,MOV(16#106a_a070,Wrk[1]) MOV(16#32bb_d1b8,Wrk[0]) COP(Wrk[0],K[47],1) ,MOV(16#19a4_c116,Wrk[1]) MOV(16#b8d2_d0c8,Wrk[0]) COP(Wrk[0],K[48],1) ,MOV(16#1e37_6c08,Wrk[1]) MOV(16#5141_ab53,Wrk[0]) COP(Wrk[0],K[49],1) ,MOV(16#2748_774c,Wrk[1]) MOV(16#df8e_eb99,Wrk[0]) COP(Wrk[0],K[50],1) ,MOV(16#34b0_bcb5,Wrk[1]) MOV(16#e19b_48a8,Wrk[0]) COP(Wrk[0],K[51],1) ,MOV(16#391c_0cb3,Wrk[1]) MOV(16#c5c9_5a63,Wrk[0]) COP(Wrk[0],K[52],1) ,MOV(16#4ed8_aa4a,Wrk[1]) MOV(16#e341_8acb,Wrk[0]) COP(Wrk[0],K[53],1) ,MOV(16#5b9c_ca4f,Wrk[1]) MOV(16#7763_e373,Wrk[0]) COP(Wrk[0],K[54],1) ,MOV(16#682e_6ff3,Wrk[1]) MOV(16#d6b2_b8a3,Wrk[0]) COP(Wrk[0],K[55],1) ,MOV(16#748f_82ee,Wrk[1]) MOV(16#5def_b2fc,Wrk[0]) COP(Wrk[0],K[56],1) ,MOV(16#78a5_636f,Wrk[1]) MOV(16#4317_2f60,Wrk[0]) COP(Wrk[0],K[57],1) ,MOV(16#84c8_7814,Wrk[1]) MOV(16#a1f0_ab72,Wrk[0]) COP(Wrk[0],K[58],1) ,MOV(16#8cc7_0208,Wrk[1]) MOV(16#1a64_39ec,Wrk[0]) COP(Wrk[0],K[59],1) ,MOV(16#90be_fffa,Wrk[1]) MOV(16#2363_1e28,Wrk[0]) COP(Wrk[0],K[60],1) ,MOV(16#a450_6ceb,Wrk[1]) MOV(16#de82_bde9,Wrk[0]) COP(Wrk[0],K[61],1) ,MOV(16#bef9_a3f7,Wrk[1]) MOV(16#b2c6_7915,Wrk[0]) COP(Wrk[0],K[62],1) ,MOV(16#c671_78f2,Wrk[1]) MOV(16#e372_532b,Wrk[0]) COP(Wrk[0],K[63],1) ,MOV(16#ca27_3ece,Wrk[1]) MOV(16#ea26_619c,Wrk[0]) COP(Wrk[0],K[64],1) ,MOV(16#d186_b8c7,Wrk[1]) MOV(16#21c0_c207,Wrk[0]) COP(Wrk[0],K[65],1) ,MOV(16#eada_7dd6,Wrk[1]) MOV(16#cde0_eb1e,Wrk[0]) COP(Wrk[0],K[66],1) ,MOV(16#f57d_4f7f,Wrk[1]) MOV(16#ee6e_d178,Wrk[0]) COP(Wrk[0],K[67],1) ,MOV(16#06f0_67aa,Wrk[1]) MOV(16#7217_6fba,Wrk[0]) COP(Wrk[0],K[68],1) ,MOV(16#0a63_7dc5,Wrk[1]) MOV(16#a2c8_98a6,Wrk[0]) COP(Wrk[0],K[69],1) ,MOV(16#113f_9804,Wrk[1]) MOV(16#bef9_0dae,Wrk[0]) COP(Wrk[0],K[70],1) ,MOV(16#1b71_0b35,Wrk[1]) MOV(16#131c_471b,Wrk[0]) COP(Wrk[0],K[71],1) ,MOV(16#28db_77f5,Wrk[1]) MOV(16#2304_7d84,Wrk[0]) COP(Wrk[0],K[72],1) ,MOV(16#32ca_ab7b,Wrk[1]) MOV(16#40c7_2493,Wrk[0]) COP(Wrk[0],K[73],1) ,MOV(16#3c9e_be0a,Wrk[1]) MOV(16#15c9_bebc,Wrk[0]) COP(Wrk[0],K[74],1) ,MOV(16#431d_67c4,Wrk[1]) MOV(16#9c10_0d4c,Wrk[0]) COP(Wrk[0],K[75],1) ,MOV(16#4cc5_d4be,Wrk[1]) MOV(16#cb3e_42b6,Wrk[0]) COP(Wrk[0],K[76],1) ,MOV(16#597f_299c,Wrk[1]) MOV(16#fc65_7e2a,Wrk[0]) COP(Wrk[0],K[77],1) ,MOV(16#5fcb_6fab,Wrk[1]) MOV(16#3ad6_faec,Wrk[0]) COP(Wrk[0],K[78],1) ,MOV(16#6c44_198c,Wrk[1]) MOV(16#4a47_5817,Wrk[0]) COP(Wrk[0],K[79],1) ];
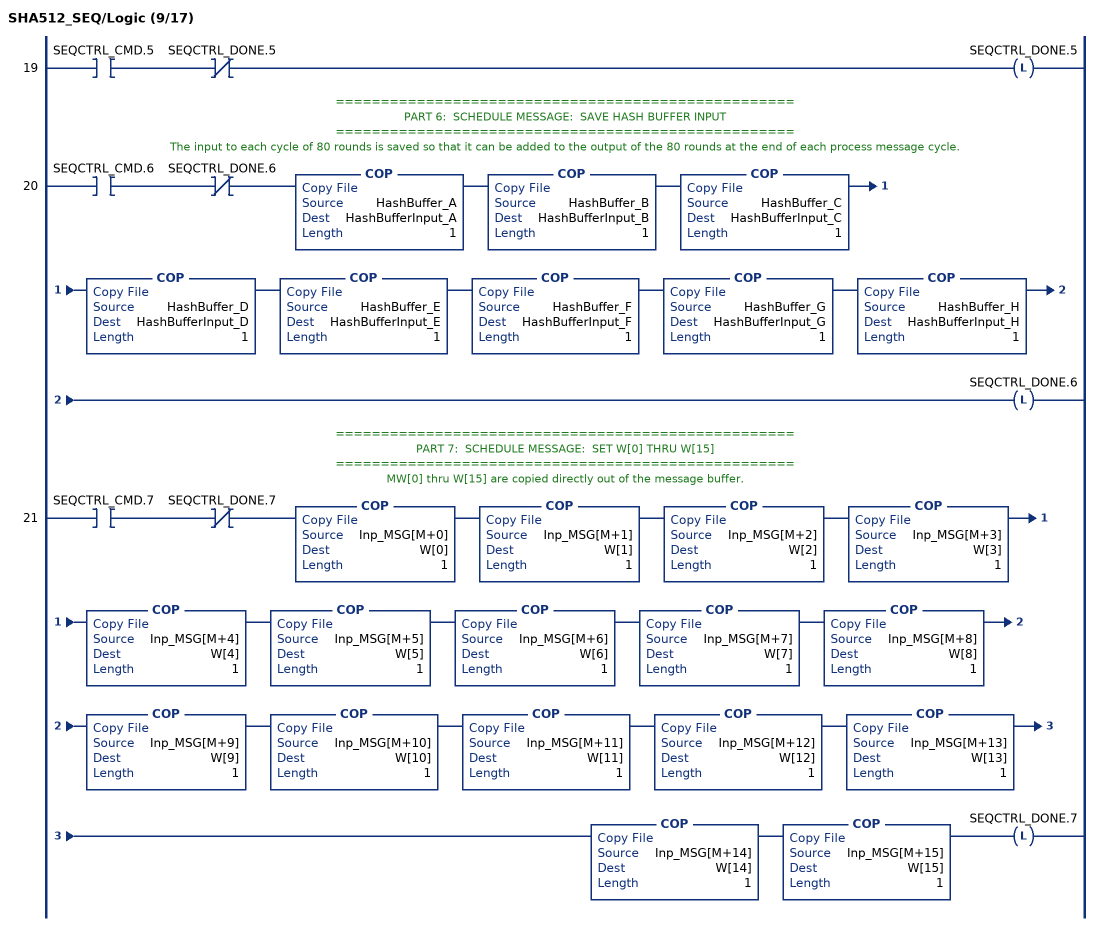
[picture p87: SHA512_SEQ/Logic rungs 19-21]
   19: XIC(SEQCTRL_CMD.5)XIO(SEQCTRL_DONE.5)OTL(SEQCTRL_DONE.5);
   // ===================================================
   // PART 6:  SCHEDULE MESSAGE:  SAVE HASH BUFFER INPUT
   // ===================================================
   // The input to each cycle of 80 rounds is saved so that it can be added to the output of the 80 rounds at the end of each process message cycle.
   20: XIC(SEQCTRL_CMD.6)XIO(SEQCTRL_DONE.6)COP(HashBuffer_A,HashBufferInput_A,1)COP(HashBuffer_B,HashBufferInput_B,1)COP(HashBuffer_C,HashBufferInput_C,1)COP(HashBuffer_D,HashBufferInput_D,1)COP(HashBuffer_E,HashBufferInput_E,1)COP(HashBuffer_F,HashBufferInput_F,1)COP(HashBuffer_G,HashBufferInput_G,1)COP(HashBuffer_H,HashBufferInput_H,1)OTL(SEQCTRL_DONE.6);
   // ===================================================
   // PART 7:  SCHEDULE MESSAGE:  SET W[0] THRU W[15]
   // ===================================================
   // MW[0] thru W[15] are copied directly out of the message buffer.
   21: XIC(SEQCTRL_CMD.7)XIO(SEQCTRL_DONE.7)COP(Inp_MSG[M+0],W[0],1)COP(Inp_MSG[M+1],W[1],1)COP(Inp_MSG[M+2],W[2],1)COP(Inp_MSG[M+3],W[3],1)COP(Inp_MSG[M+4],W[4],1)COP(Inp_MSG[M+5],W[5],1)COP(Inp_MSG[M+6],W[6],1)COP(Inp_MSG[M+7],W[7],1)COP(Inp_MSG[M+8],W[8],1)COP(Inp_MSG[M+9],W[9],1)COP(Inp_MSG[M+10],W[10],1)COP(Inp_MSG[M+11],W[11],1)COP(Inp_MSG[M+12],W[12],1)COP(Inp_MSG[M+13],W[13],1)COP(Inp_MSG[M+14],W[14],1)COP(Inp_MSG[M+15],W[15],1)OTL(SEQCTRL_DONE.7);
(* Logix 5000 AddOnInstructionDefinition export Ed25519_VERIFY; software revision 30.00; part 5 of 7 *)
(* tags used below, declared in another part *)
   Out_HASH : LINT[8];
   CondFunc : LINT;
   CondFunc_tmp : LINT[3];
   HashBuffer_A : LINT;
   HashBuffer_B : LINT;
   HashBuffer_C : LINT;
   HashBuffer_D : LINT;
   HashBuffer_E : LINT;
   HashBuffer_F : LINT;
   HashBuffer_G : LINT;
   HashBuffer_H : LINT;
   HashBufferInput_A : LINT;
   HashBufferInput_B : LINT;
   HashBufferInput_C : LINT;
   HashBufferInput_D : LINT;
   HashBufferInput_E : LINT;
   HashBufferInput_F : LINT;
   HashBufferInput_G : LINT;
   HashBufferInput_H : LINT;
   M : INT;   // MESSAGE INCREMENTS
   t : INT;
   L_ADD : L_ADD;
   L_AND : L_AND;
   L_NOT : L_NOT;
   L_ROTR : L_ROTR;
   L_SHR : L_SHR;
   L_XOR : L_XOR;
   MajFunc : LINT;
   Sigma0 : LINT;
   Sigma1 : LINT;
   SigmaA : LINT;
   SigmaE : LINT;
   x : INT;
   T1 : LINT;
   T2 : LINT;
   tmp : LINT[20];
   TOTAL_MSG_LENGTH_MINUS_16 : DINT;
   W : LINT[85];   // MESSAGE SCHEDULE
   Wrk : DINT[2];
(* SHA512_SEQ, continued *)

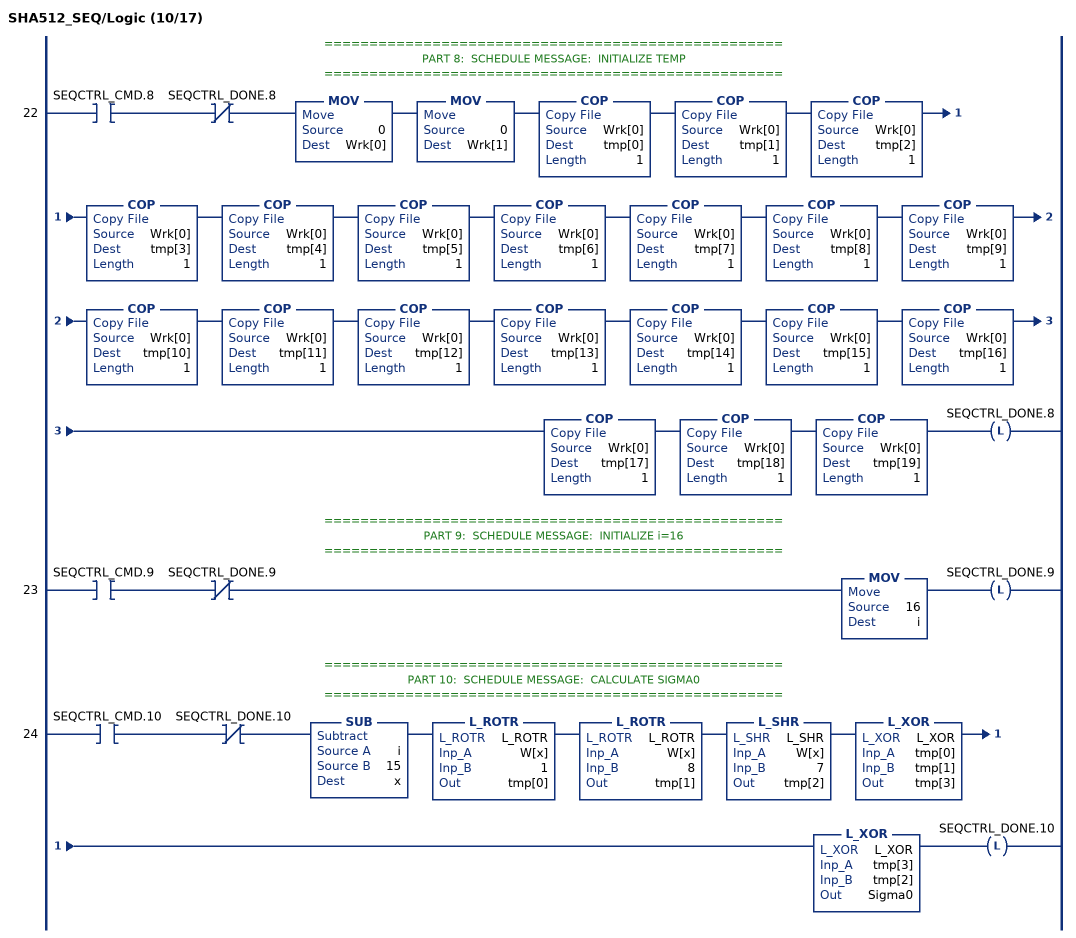
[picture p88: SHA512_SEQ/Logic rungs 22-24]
   // ===================================================
   // PART 8:  SCHEDULE MESSAGE:  INITIALIZE TEMP
   // ===================================================
   22: XIC(SEQCTRL_CMD.8)XIO(SEQCTRL_DONE.8)MOV(0,Wrk[0])MOV(0,Wrk[1])COP(Wrk[0],tmp[0],1)COP(Wrk[0],tmp[1],1)COP(Wrk[0],tmp[2],1)COP(Wrk[0],tmp[3],1)COP(Wrk[0],tmp[4],1)COP(Wrk[0],tmp[5],1)COP(Wrk[0],tmp[6],1)COP(Wrk[0],tmp[7],1)COP(Wrk[0],tmp[8],1)COP(Wrk[0],tmp[9],1)COP(Wrk[0],tmp[10],1)COP(Wrk[0],tmp[11],1)COP(Wrk[0],tmp[12],1)COP(Wrk[0],tmp[13],1)COP(Wrk[0],tmp[14],1)COP(Wrk[0],tmp[15],1)COP(Wrk[0],tmp[16],1)COP(Wrk[0],tmp[17],1)COP(Wrk[0],tmp[18],1)COP(Wrk[0],tmp[19],1)OTL(SEQCTRL_DONE.8);
   // ===================================================
   // PART 9:  SCHEDULE MESSAGE:  INITIALIZE i=16
   // ===================================================
   23: XIC(SEQCTRL_CMD.9)XIO(SEQCTRL_DONE.9)MOV(16,i)OTL(SEQCTRL_DONE.9);
   // ===================================================
   // PART 10:  SCHEDULE MESSAGE:  CALCULATE SIGMA0
   // ===================================================
   24: XIC(SEQCTRL_CMD.10)XIO(SEQCTRL_DONE.10)SUB(i,15,x)L_ROTR(L_ROTR,W[x],1,tmp[0])L_ROTR(L_ROTR,W[x],8,tmp[1])L_SHR(L_SHR,W[x],7,tmp[2])L_XOR(L_XOR,tmp[0],tmp[1],tmp[3])L_XOR(L_XOR,tmp[3],tmp[2],Sigma0)OTL(SEQCTRL_DONE.10);
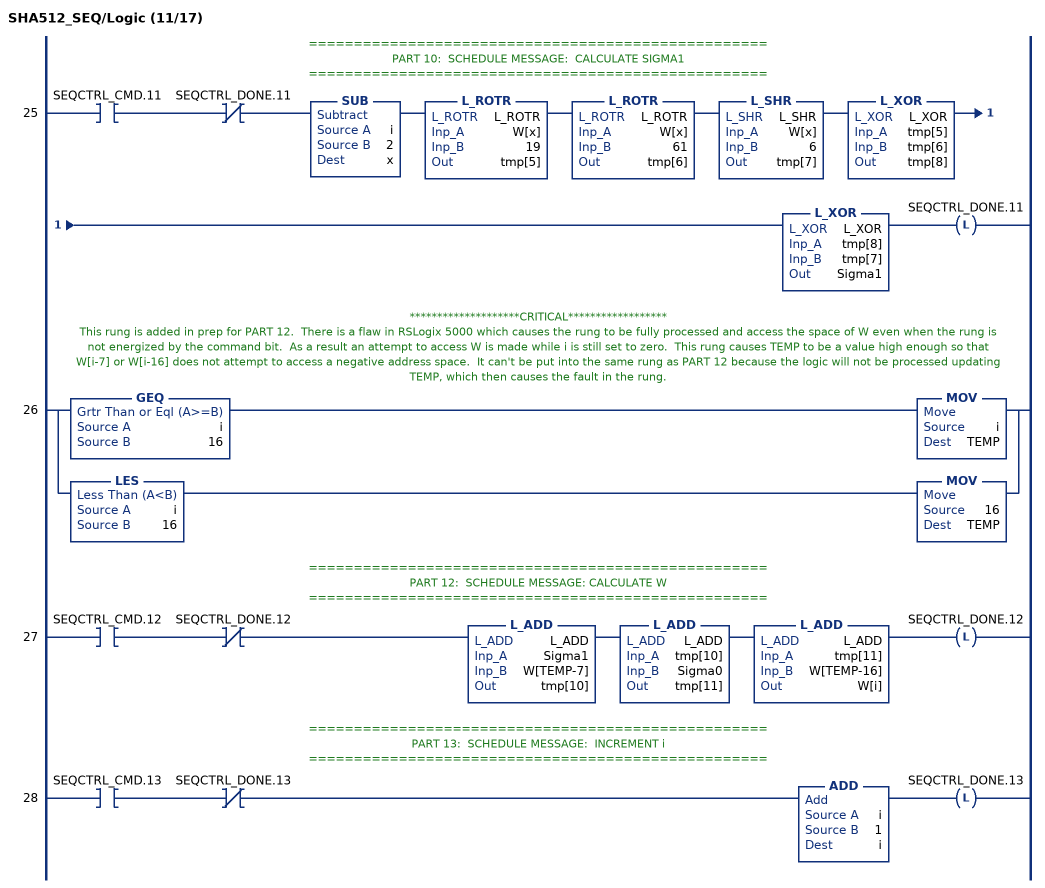
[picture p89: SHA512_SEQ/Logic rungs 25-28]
   // ===================================================
   // PART 10:  SCHEDULE MESSAGE:  CALCULATE SIGMA1
   // ===================================================
   25: XIC(SEQCTRL_CMD.11)XIO(SEQCTRL_DONE.11)SUB(i,2,x)L_ROTR(L_ROTR,W[x],19,tmp[5])L_ROTR(L_ROTR,W[x],61,tmp[6])L_SHR(L_SHR,W[x],6,tmp[7])L_XOR(L_XOR,tmp[5],tmp[6],tmp[8])L_XOR(L_XOR,tmp[8],tmp[7],Sigma1)OTL(SEQCTRL_DONE.11);
   // ********************CRITICAL******************
   // This rung is added in prep for PART 12.  There is a flaw in RSLogix 5000 which causes the rung to be fully processed and access the space of W even when the rung is not energized by the command bit.  As a result an attempt to access W is made while i is still set to zero.  This rung causes TEMP to be a value high enough so that W[i-7] or W[i-16] does not attempt to access a negative address space.  It can't be put into the same rung as PART 12 because the logic will not be processed updating TEMP, which then causes the fault in the rung.
   26: [GEQ(i,16) MOV(i,TEMP) ,LES(i,16) MOV(16,TEMP) ];
   // ===================================================
   // PART 12:  SCHEDULE MESSAGE: CALCULATE W
   // ===================================================
   27: XIC(SEQCTRL_CMD.12)XIO(SEQCTRL_DONE.12)L_ADD(L_ADD,Sigma1,W[TEMP-7],tmp[10])L_ADD(L_ADD,tmp[10],Sigma0,tmp[11])L_ADD(L_ADD,tmp[11],W[TEMP-16],W[i])OTL(SEQCTRL_DONE.12);
   // ===================================================
   // PART 13:  SCHEDULE MESSAGE:  INCREMENT i
   // ===================================================
   28: XIC(SEQCTRL_CMD.13)XIO(SEQCTRL_DONE.13)ADD(i,1,i)OTL(SEQCTRL_DONE.13);
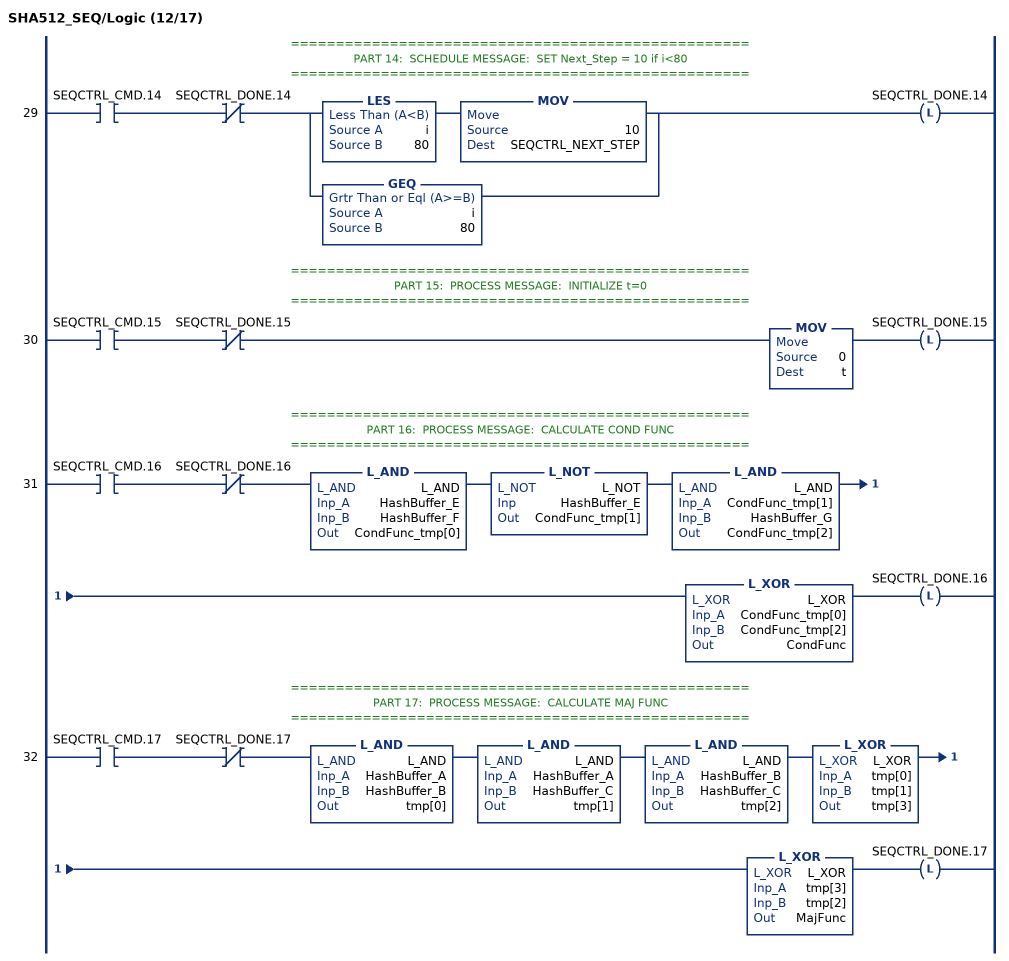
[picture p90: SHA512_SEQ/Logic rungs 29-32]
   // ===================================================
   // PART 14:  SCHEDULE MESSAGE:  SET Next_Step = 10 if i<80
   // ===================================================
   29: XIC(SEQCTRL_CMD.14)XIO(SEQCTRL_DONE.14)[LES(i,80) MOV(10,SEQCTRL_NEXT_STEP) ,GEQ(i,80) ]OTL(SEQCTRL_DONE.14);
   // ===================================================
   // PART 15:  PROCESS MESSAGE:  INITIALIZE t=0
   // ===================================================
   30: XIC(SEQCTRL_CMD.15)XIO(SEQCTRL_DONE.15)MOV(0,t)OTL(SEQCTRL_DONE.15);
   // ===================================================
   // PART 16:  PROCESS MESSAGE:  CALCULATE COND FUNC
   // ===================================================
   31: XIC(SEQCTRL_CMD.16)XIO(SEQCTRL_DONE.16)L_AND(L_AND,HashBuffer_E,HashBuffer_F,CondFunc_tmp[0])L_NOT(L_NOT,HashBuffer_E,CondFunc_tmp[1])L_AND(L_AND,CondFunc_tmp[1],HashBuffer_G,CondFunc_tmp[2])L_XOR(L_XOR,CondFunc_tmp[0],CondFunc_tmp[2],CondFunc)OTL(SEQCTRL_DONE.16);
   // ===================================================
   // PART 17:  PROCESS MESSAGE:  CALCULATE MAJ FUNC
   // ===================================================
   32: XIC(SEQCTRL_CMD.17)XIO(SEQCTRL_DONE.17)L_AND(L_AND,HashBuffer_A,HashBuffer_B,tmp[0])L_AND(L_AND,HashBuffer_A,HashBuffer_C,tmp[1])L_AND(L_AND,HashBuffer_B,HashBuffer_C,tmp[2])L_XOR(L_XOR,tmp[0],tmp[1],tmp[3])L_XOR(L_XOR,tmp[3],tmp[2],MajFunc)OTL(SEQCTRL_DONE.17);
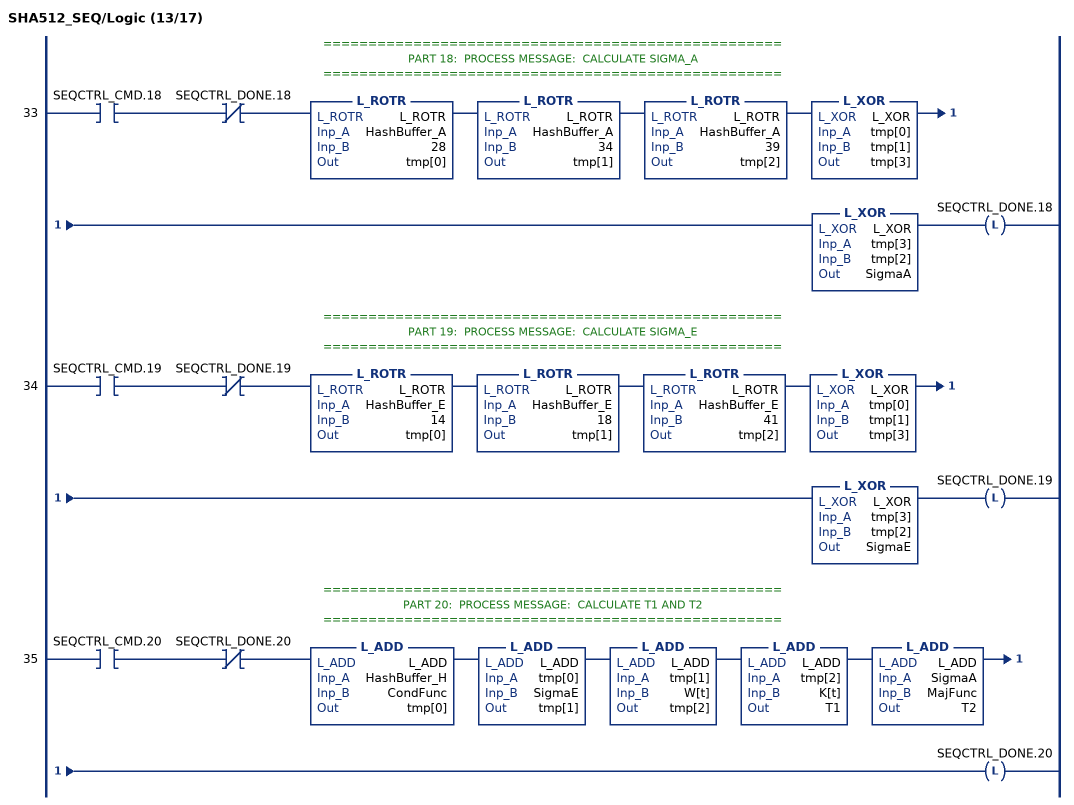
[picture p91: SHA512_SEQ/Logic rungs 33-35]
   // ===================================================
   // PART 18:  PROCESS MESSAGE:  CALCULATE SIGMA_A
   // ===================================================
   33: XIC(SEQCTRL_CMD.18)XIO(SEQCTRL_DONE.18)L_ROTR(L_ROTR,HashBuffer_A,28,tmp[0])L_ROTR(L_ROTR,HashBuffer_A,34,tmp[1])L_ROTR(L_ROTR,HashBuffer_A,39,tmp[2])L_XOR(L_XOR,tmp[0],tmp[1],tmp[3])L_XOR(L_XOR,tmp[3],tmp[2],SigmaA)OTL(SEQCTRL_DONE.18);
   // ===================================================
   // PART 19:  PROCESS MESSAGE:  CALCULATE SIGMA_E
   // ===================================================
   34: XIC(SEQCTRL_CMD.19)XIO(SEQCTRL_DONE.19)L_ROTR(L_ROTR,HashBuffer_E,14,tmp[0])L_ROTR(L_ROTR,HashBuffer_E,18,tmp[1])L_ROTR(L_ROTR,HashBuffer_E,41,tmp[2])L_XOR(L_XOR,tmp[0],tmp[1],tmp[3])L_XOR(L_XOR,tmp[3],tmp[2],SigmaE)OTL(SEQCTRL_DONE.19);
   // ===================================================
   // PART 20:  PROCESS MESSAGE:  CALCULATE T1 AND T2
   // ===================================================
   35: XIC(SEQCTRL_CMD.20)XIO(SEQCTRL_DONE.20)L_ADD(L_ADD,HashBuffer_H,CondFunc,tmp[0])L_ADD(L_ADD,tmp[0],SigmaE,tmp[1])L_ADD(L_ADD,tmp[1],W[t],tmp[2])L_ADD(L_ADD,tmp[2],K[t],T1)L_ADD(L_ADD,SigmaA,MajFunc,T2)OTL(SEQCTRL_DONE.20);
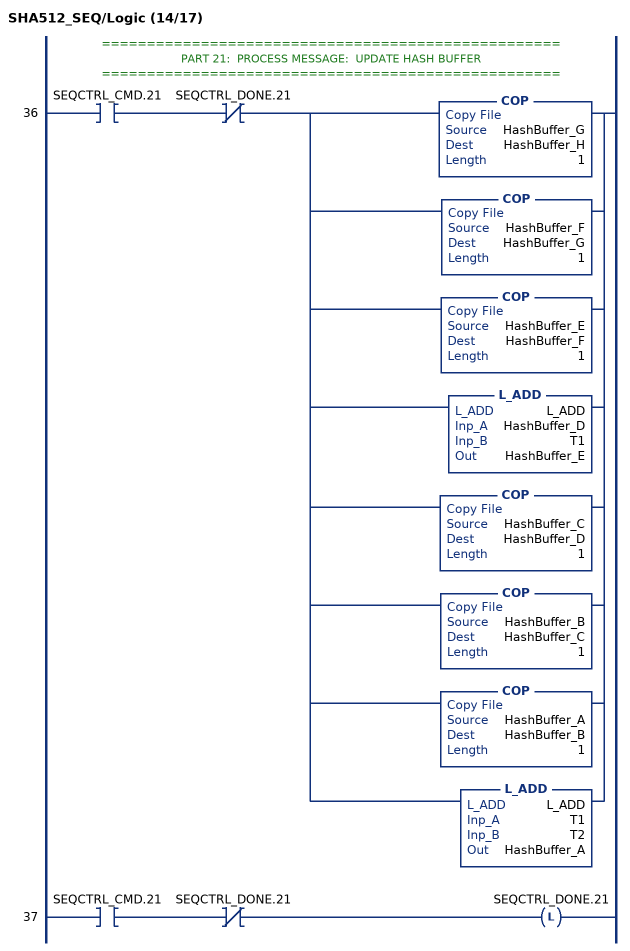
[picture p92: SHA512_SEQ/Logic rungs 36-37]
   // ===================================================
   // PART 21:  PROCESS MESSAGE:  UPDATE HASH BUFFER
   // ===================================================
   36: XIC(SEQCTRL_CMD.21)XIO(SEQCTRL_DONE.21)[COP(HashBuffer_G,HashBuffer_H,1) ,COP(HashBuffer_F,HashBuffer_G,1) ,COP(HashBuffer_E,HashBuffer_F,1) ,L_ADD(L_ADD,HashBuffer_D,T1,HashBuffer_E) ,COP(HashBuffer_C,HashBuffer_D,1) ,COP(HashBuffer_B,HashBuffer_C,1) ,COP(HashBuffer_A,HashBuffer_B,1) ,L_ADD(L_ADD,T1,T2,HashBuffer_A) ];
   37: XIC(SEQCTRL_CMD.21)XIO(SEQCTRL_DONE.21)OTL(SEQCTRL_DONE.21);
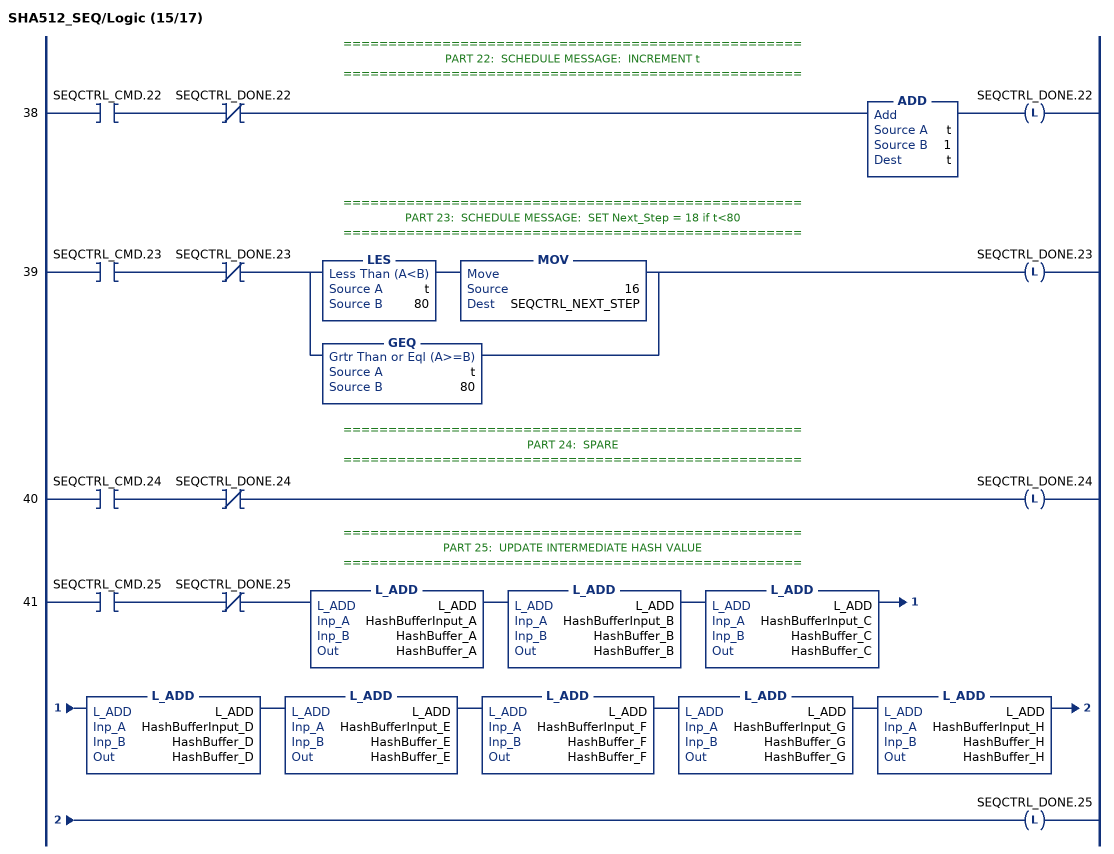
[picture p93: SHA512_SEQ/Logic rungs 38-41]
   // ===================================================
   // PART 22:  SCHEDULE MESSAGE:  INCREMENT t
   // ===================================================
   38: XIC(SEQCTRL_CMD.22)XIO(SEQCTRL_DONE.22)ADD(t,1,t)OTL(SEQCTRL_DONE.22);
   // ===================================================
   // PART 23:  SCHEDULE MESSAGE:  SET Next_Step = 18 if t<80
   // ===================================================
   39: XIC(SEQCTRL_CMD.23)XIO(SEQCTRL_DONE.23)[LES(t,80) MOV(16,SEQCTRL_NEXT_STEP) ,GEQ(t,80) ]OTL(SEQCTRL_DONE.23);
   // ===================================================
   // PART 24:  SPARE
   // ===================================================
   40: XIC(SEQCTRL_CMD.24)XIO(SEQCTRL_DONE.24)OTL(SEQCTRL_DONE.24);
   // ===================================================
   // PART 25:  UPDATE INTERMEDIATE HASH VALUE
   // ===================================================
   41: XIC(SEQCTRL_CMD.25)XIO(SEQCTRL_DONE.25)L_ADD(L_ADD,HashBufferInput_A,HashBuffer_A,HashBuffer_A)L_ADD(L_ADD,HashBufferInput_B,HashBuffer_B,HashBuffer_B)L_ADD(L_ADD,HashBufferInput_C,HashBuffer_C,HashBuffer_C)L_ADD(L_ADD,HashBufferInput_D,HashBuffer_D,HashBuffer_D)L_ADD(L_ADD,HashBufferInput_E,HashBuffer_E,HashBuffer_E)L_ADD(L_ADD,HashBufferInput_F,HashBuffer_F,HashBuffer_F)L_ADD(L_ADD,HashBufferInput_G,HashBuffer_G,HashBuffer_G)L_ADD(L_ADD,HashBufferInput_H,HashBuffer_H,HashBuffer_H)OTL(SEQCTRL_DONE.25);
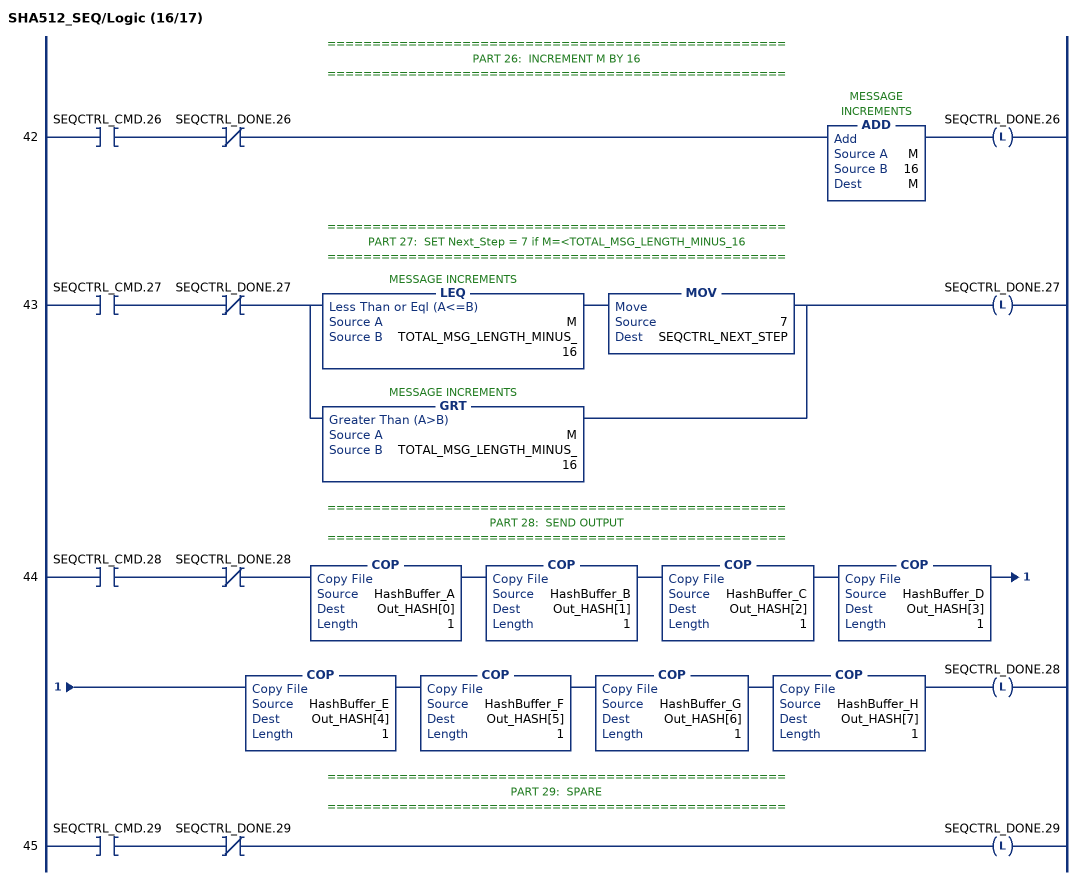
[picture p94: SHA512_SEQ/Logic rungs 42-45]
   // ===================================================
   // PART 26:  INCREMENT M BY 16
   // ===================================================
   42: XIC(SEQCTRL_CMD.26)XIO(SEQCTRL_DONE.26)ADD(M,16,M)OTL(SEQCTRL_DONE.26);
   // ===================================================
   // PART 27:  SET Next_Step = 7 if M=<TOTAL_MSG_LENGTH_MINUS_16
   // ===================================================
   43: XIC(SEQCTRL_CMD.27)XIO(SEQCTRL_DONE.27)[LEQ(M,TOTAL_MSG_LENGTH_MINUS_16) MOV(7,SEQCTRL_NEXT_STEP) ,GRT(M,TOTAL_MSG_LENGTH_MINUS_16) ]OTL(SEQCTRL_DONE.27);
   // ===================================================
   // PART 28:  SEND OUTPUT
   // ===================================================
   44: XIC(SEQCTRL_CMD.28)XIO(SEQCTRL_DONE.28)COP(HashBuffer_A,Out_HASH[0],1)COP(HashBuffer_B,Out_HASH[1],1)COP(HashBuffer_C,Out_HASH[2],1)COP(HashBuffer_D,Out_HASH[3],1)COP(HashBuffer_E,Out_HASH[4],1)COP(HashBuffer_F,Out_HASH[5],1)COP(HashBuffer_G,Out_HASH[6],1)COP(HashBuffer_H,Out_HASH[7],1)OTL(SEQCTRL_DONE.28);
   // ===================================================
   // PART 29:  SPARE
   // ===================================================
   45: XIC(SEQCTRL_CMD.29)XIO(SEQCTRL_DONE.29)OTL(SEQCTRL_DONE.29);
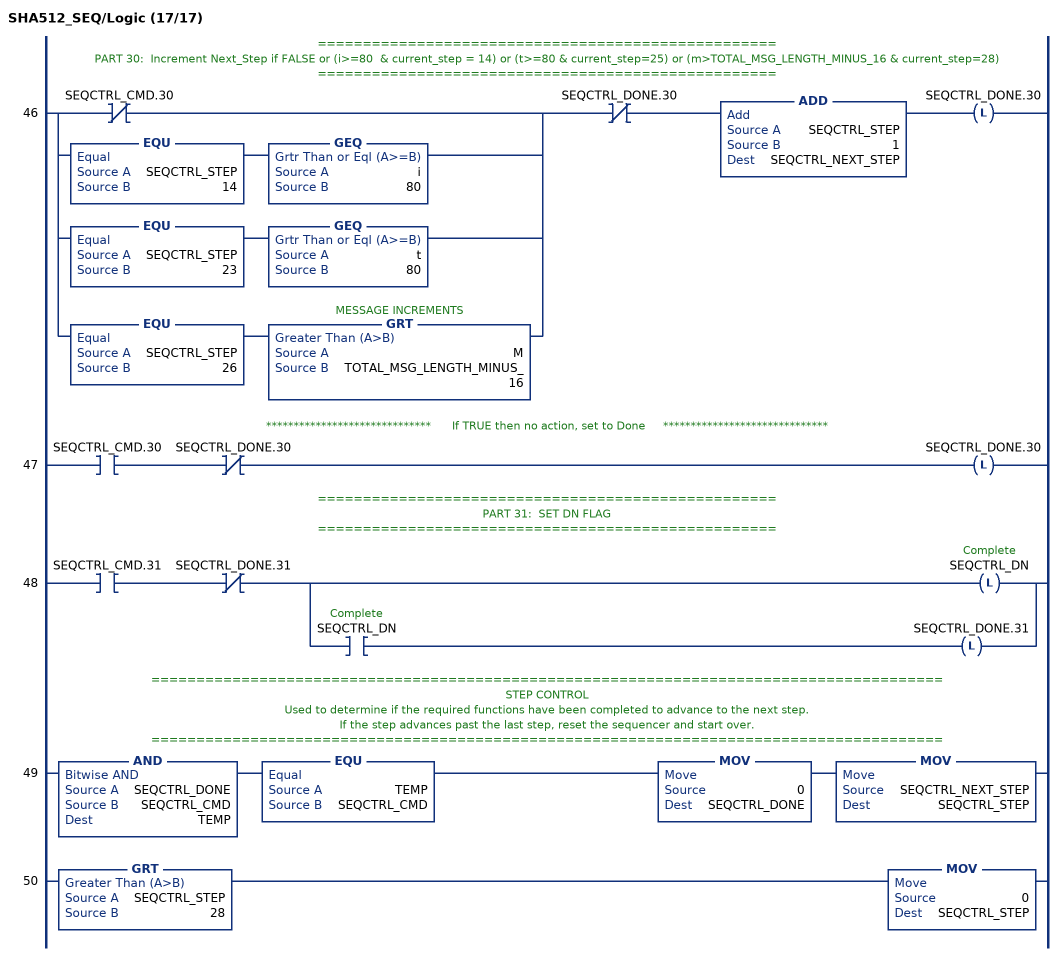
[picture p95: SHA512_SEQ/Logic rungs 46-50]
   // ===================================================
   // PART 30:  Increment Next_Step if FALSE or (i>=80  & current_step = 14) or (t>=80 & current_step=25) or (m>TOTAL_MSG_LENGTH_MINUS_16 & current_step=28)
   // ===================================================
   46: [XIO(SEQCTRL_CMD.30) ,EQU(SEQCTRL_STEP,14) GEQ(i,80) ,EQU(SEQCTRL_STEP,23) GEQ(t,80) ,EQU(SEQCTRL_STEP,26) GRT(M,TOTAL_MSG_LENGTH_MINUS_16) ]XIO(SEQCTRL_DONE.30)ADD(SEQCTRL_STEP,1,SEQCTRL_NEXT_STEP)OTL(SEQCTRL_DONE.30);
   // ******************************      If TRUE then no action, set to Done     ******************************
   47: XIC(SEQCTRL_CMD.30)XIO(SEQCTRL_DONE.30)OTL(SEQCTRL_DONE.30);
   // ===================================================
   // PART 31:  SET DN FLAG
   // ===================================================
   48: XIC(SEQCTRL_CMD.31)XIO(SEQCTRL_DONE.31)[OTL(SEQCTRL_DN) ,XIC(SEQCTRL_DN) OTL(SEQCTRL_DONE.31) ];
   // ========================================================================================
   // STEP CONTROL
   // Used to determine if the required functions have been completed to advance to the next step.
   // If the step advances past the last step, reset the sequencer and start over.
   // ========================================================================================
   49: AND(SEQCTRL_DONE,SEQCTRL_CMD,TEMP)EQU(TEMP,SEQCTRL_CMD)MOV(0,SEQCTRL_DONE)MOV(SEQCTRL_NEXT_STEP,SEQCTRL_STEP);
   50: GRT(SEQCTRL_STEP,28)MOV(0,SEQCTRL_STEP);
END_ROUTINE
END_ADD_ON_INSTRUCTION

ADD_ON_INSTRUCTION B256_COMPARE   (* revision 1.0 20170916, vendor Kenneth A. Fischer *)
// Determines if C1<C2, C1=C2, or C1>C2
// Revision note:
// Rev1.0: 20170916 - Initial Release
VAR_IN_OUT
   Inp_C1 : DINT[22]; {required}
   Inp_C2 : DINT[22]; {required}
END_VAR
VAR_OUTPUT
   EQUAL : BOOL; {access Read Only}
   GREATER : BOOL; {access Read Only}
   LESS : BOOL; {access Read Only}
END_VAR
VAR
   C3 : DINT;
   i : DINT;
END_VAR

ROUTINE Logic   (* ladder *)
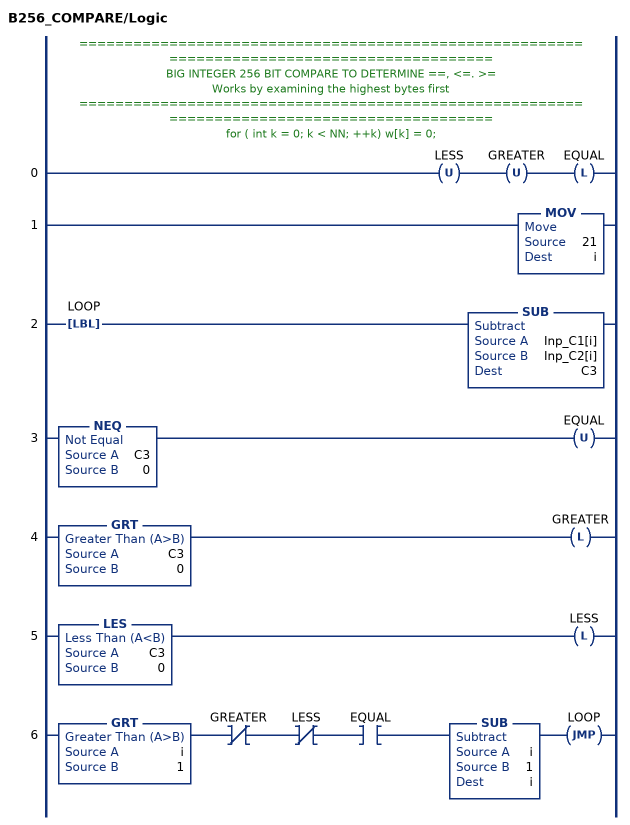
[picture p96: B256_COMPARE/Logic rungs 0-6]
   // ============================================================================================
   // BIG INTEGER 256 BIT COMPARE TO DETERMINE ==, <=. >=
   // Works by examining the highest bytes first
   // ============================================================================================
   // for ( int k = 0; k < NN; ++k) w[k] = 0;
   0: OTU(LESS)OTU(GREATER)OTL(EQUAL);
   1: MOV(21,i);
   2: LBL(LOOP)SUB(Inp_C1[i],Inp_C2[i],C3);
   3: NEQ(C3,0)OTU(EQUAL);
   4: GRT(C3,0)OTL(GREATER);
   5: LES(C3,0)OTL(LESS);
   6: GRT(i,1)XIO(GREATER)XIO(LESS)XIC(EQUAL)SUB(i,1,i)JMP(LOOP);
END_ROUTINE
END_ADD_ON_INSTRUCTION

ADD_ON_INSTRUCTION B256_StoC_LE   (* revision 1.0 20170916, vendor Kenneth A. Fischer *)
// Convert 256-bit value using 64 hex string characters into 256-bit value using 22 12-bit pieces
// Little Endian
// Revision note:
// Rev1.0: 20170916 - Initial Release
VAR_IN_OUT
   Temp_E : DINT[32]; {required}
   Inp_S : STRING; {required}
   Out_C : DINT[22]; {required}
END_VAR
VAR
   byte : DINT[3];
   D_SHL : D_SHL;
   i : INT;
   j : INT;
   k : DINT;
   temp : DINT;
   B256_CtoE : B256_CtoE;
   E : DINT[32];
   B256_EtoC : B256_EtoC;
END_VAR

ROUTINE Logic   (* ladder *)
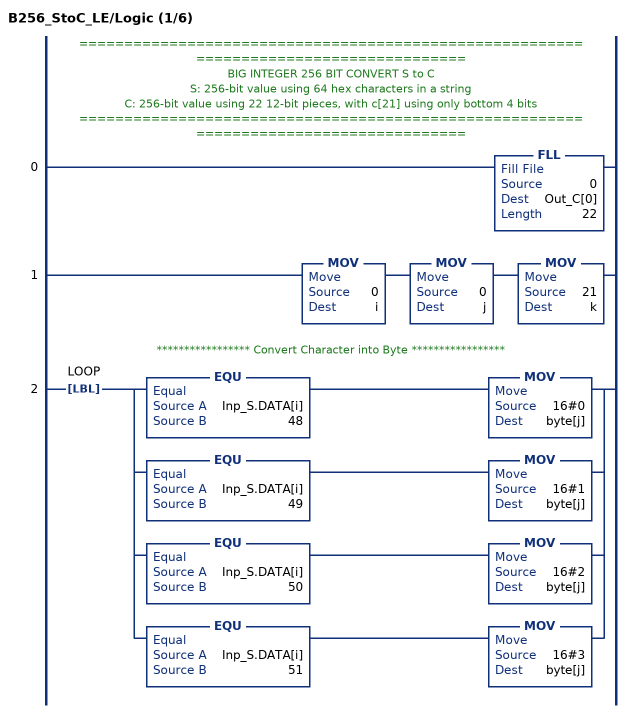
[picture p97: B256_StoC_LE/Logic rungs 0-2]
   // ======================================================================================
   // BIG INTEGER 256 BIT CONVERT S to C
   // S: 256-bit value using 64 hex characters in a string
   // C: 256-bit value using 22 12-bit pieces, with c[21] using only bottom 4 bits
   // ======================================================================================
   0: FLL(0,Out_C[0],22);
   1: MOV(0,i)MOV(0,j)MOV(21,k);
   // ***************** Convert Character into Byte *****************
   2: LBL(LOOP)[EQU(Inp_S.DATA[i],48) MOV(16#0,byte[j]) ,EQU(Inp_S.DATA[i],49) MOV(16#1,byte[j]) ,EQU(Inp_S.DATA[i],50) MOV(16#2,byte[j]) ,EQU(Inp_S.DATA[i],51) MOV(16#3,byte[j]) ];
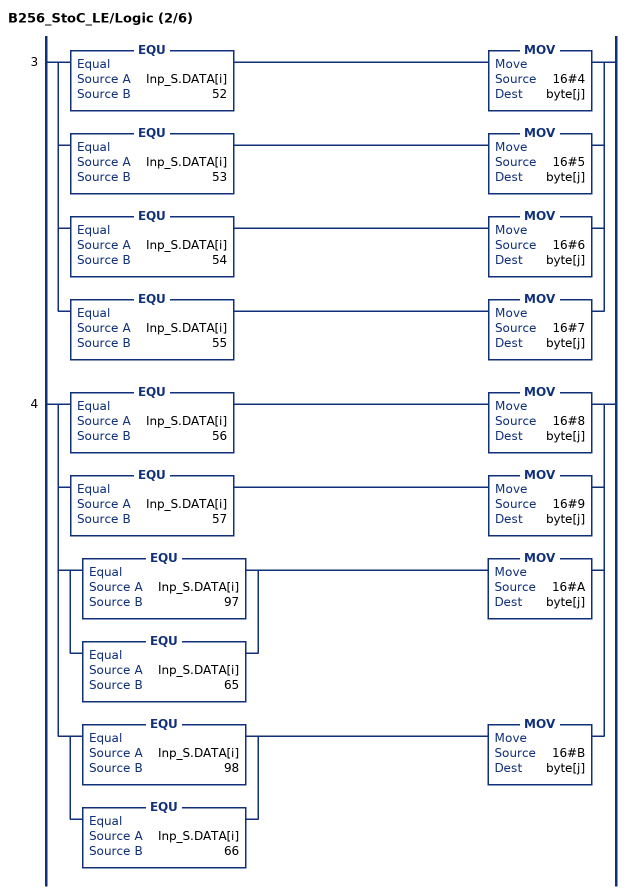
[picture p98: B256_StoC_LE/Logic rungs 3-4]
   3: [EQU(Inp_S.DATA[i],52) MOV(16#4,byte[j]) ,EQU(Inp_S.DATA[i],53) MOV(16#5,byte[j]) ,EQU(Inp_S.DATA[i],54) MOV(16#6,byte[j]) ,EQU(Inp_S.DATA[i],55) MOV(16#7,byte[j]) ];
   4: [EQU(Inp_S.DATA[i],56) MOV(16#8,byte[j]) ,EQU(Inp_S.DATA[i],57) MOV(16#9,byte[j]) ,[EQU(Inp_S.DATA[i],97) ,EQU(Inp_S.DATA[i],65) ] MOV(16#A,byte[j]) ,[EQU(Inp_S.DATA[i],98) ,EQU(Inp_S.DATA[i],66) ] MOV(16#B,byte[j]) ];
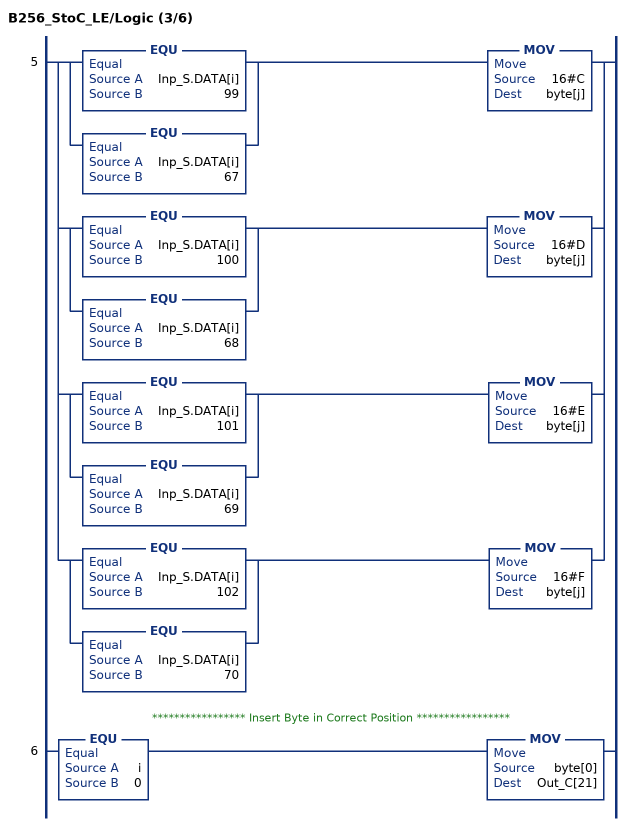
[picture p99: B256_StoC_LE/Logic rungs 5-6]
   5: [[EQU(Inp_S.DATA[i],99) ,EQU(Inp_S.DATA[i],67) ] MOV(16#C,byte[j]) ,[EQU(Inp_S.DATA[i],100) ,EQU(Inp_S.DATA[i],68) ] MOV(16#D,byte[j]) ,[EQU(Inp_S.DATA[i],101) ,EQU(Inp_S.DATA[i],69) ] MOV(16#E,byte[j]) ,[EQU(Inp_S.DATA[i],102) ,EQU(Inp_S.DATA[i],70) ] MOV(16#F,byte[j]) ];
   // ***************** Insert Byte in Correct Position *****************
   6: EQU(i,0)MOV(byte[0],Out_C[21]);
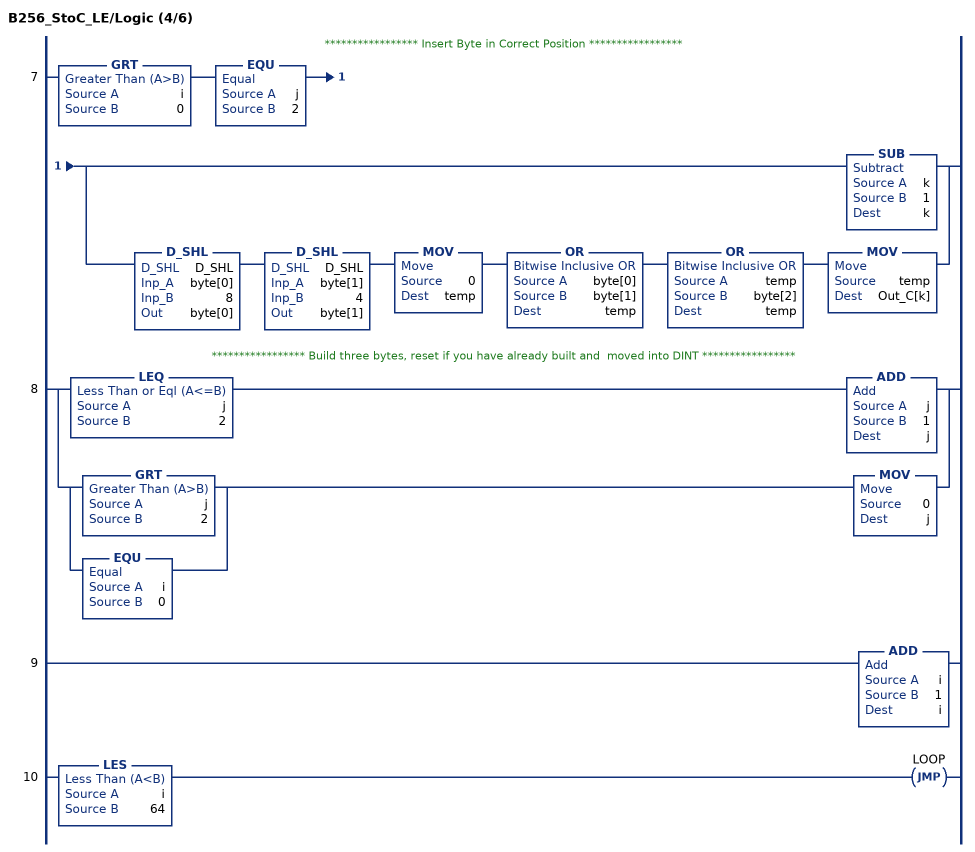
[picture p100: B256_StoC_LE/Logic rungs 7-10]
   // ***************** Insert Byte in Correct Position *****************
   7: GRT(i,0)EQU(j,2)[SUB(k,1,k) ,D_SHL(D_SHL,byte[0],8,byte[0]) D_SHL(D_SHL,byte[1],4,byte[1]) MOV(0,temp) OR(byte[0],byte[1],temp) OR(temp,byte[2],temp) MOV(temp,Out_C[k]) ];
   // ***************** Build three bytes, reset if you have already built and  moved into DINT *****************
   8: [LEQ(j,2) ADD(j,1,j) ,[GRT(j,2) ,EQU(i,0) ] MOV(0,j) ];
   9: ADD(i,1,i);
   10: LES(i,64)JMP(LOOP);
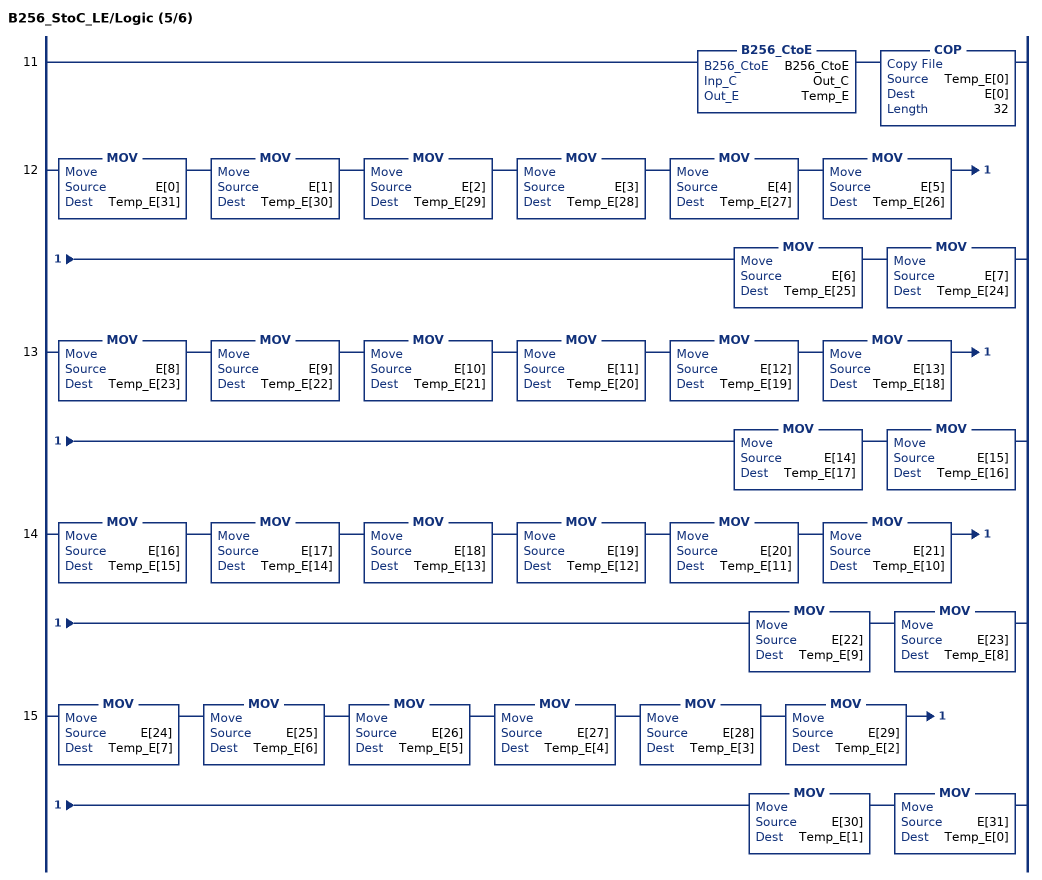
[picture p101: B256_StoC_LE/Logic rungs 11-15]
   11: B256_CtoE(B256_CtoE,Out_C,Temp_E)COP(Temp_E[0],E[0],32);
   12: MOV(E[0],Temp_E[31])MOV(E[1],Temp_E[30])MOV(E[2],Temp_E[29])MOV(E[3],Temp_E[28])MOV(E[4],Temp_E[27])MOV(E[5],Temp_E[26])MOV(E[6],Temp_E[25])MOV(E[7],Temp_E[24]);
   13: MOV(E[8],Temp_E[23])MOV(E[9],Temp_E[22])MOV(E[10],Temp_E[21])MOV(E[11],Temp_E[20])MOV(E[12],Temp_E[19])MOV(E[13],Temp_E[18])MOV(E[14],Temp_E[17])MOV(E[15],Temp_E[16]);
   14: MOV(E[16],Temp_E[15])MOV(E[17],Temp_E[14])MOV(E[18],Temp_E[13])MOV(E[19],Temp_E[12])MOV(E[20],Temp_E[11])MOV(E[21],Temp_E[10])MOV(E[22],Temp_E[9])MOV(E[23],Temp_E[8]);
   15: MOV(E[24],Temp_E[7])MOV(E[25],Temp_E[6])MOV(E[26],Temp_E[5])MOV(E[27],Temp_E[4])MOV(E[28],Temp_E[3])MOV(E[29],Temp_E[2])MOV(E[30],Temp_E[1])MOV(E[31],Temp_E[0]);
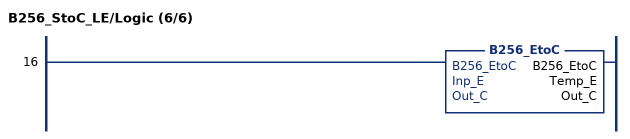
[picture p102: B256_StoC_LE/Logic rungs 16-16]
   16: B256_EtoC(B256_EtoC,Temp_E,Out_C);
END_ROUTINE
END_ADD_ON_INSTRUCTION

ADD_ON_INSTRUCTION B256_DEC   (* revision 1.0 20170916, vendor Kenneth A. Fischer *)
// c1 = --c1
// Revision note:
// Rev1.0: 20170916 - Initial Release
VAR_IN_OUT
   Inp_C : DINT[22]; {required}
END_VAR
VAR
   i : DINT;
END_VAR

ROUTINE Logic   (* ladder *)
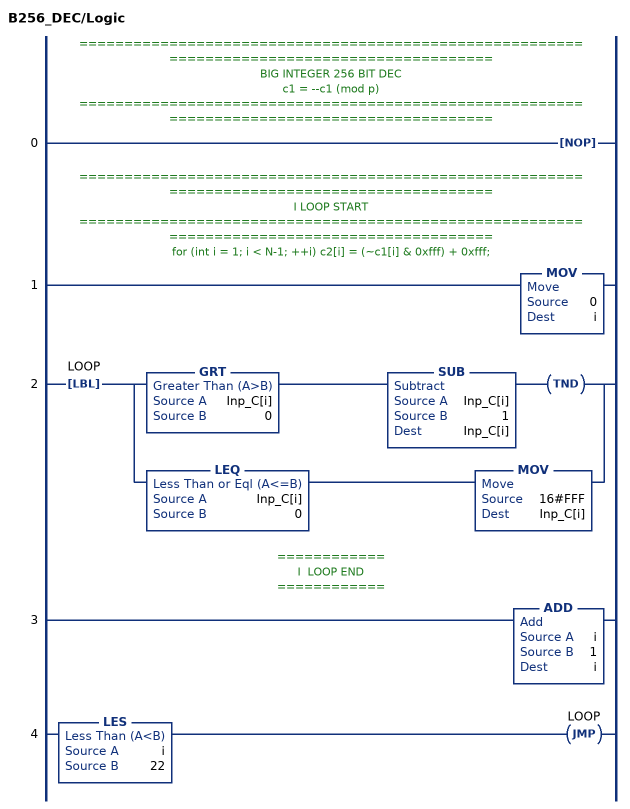
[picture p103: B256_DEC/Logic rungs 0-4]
   // ============================================================================================
   // BIG INTEGER 256 BIT DEC
   // c1 = --c1 (mod p)
   // ============================================================================================
   0: NOP();
   // ============================================================================================
   // I LOOP START
   // ============================================================================================
   // for (int i = 1; i < N-1; ++i) c2[i] = (~c1[i] & 0xfff) + 0xfff;
   1: MOV(0,i);
   2: LBL(LOOP)[GRT(Inp_C[i],0) SUB(Inp_C[i],1,Inp_C[i]) TND() ,LEQ(Inp_C[i],0) MOV(16#FFF,Inp_C[i]) ];
   // ============
   // I  LOOP END
   // ============
   3: ADD(i,1,i);
   4: LES(i,22)JMP(LOOP);
END_ROUTINE
END_ADD_ON_INSTRUCTION

ADD_ON_INSTRUCTION B256_MODPOW   (* revision 1.0 20170916, vendor Kenneth A. Fischer *)
// c2 = c1^e mod (2^255-19)
// Revision note:
// Rev1.0: 20170916 - Initial Release
VAR_IN_OUT
   Temp_C1 : DINT[22]; {required}
   Temp_C2 : DINT[22]; {required}
   Temp_D : DINT[43]; {required}
   Inp_C1 : DINT[22]; {required}   // V
   Inp_E : DINT[32]; {required}
   Out_C2 : DINT[22]; {required}   // U
END_VAR
VAR_OUTPUT
   i : INT; {access Read Only}
END_VAR
VAR_INPUT
   SEQCTRL_RESET : BOOL;   // Resets Point Multiplication if Toggled True
END_VAR
VAR_OUTPUT
   SEQCTRL_DN : BOOL; {access Read Only}   // Complete
   SEQCTRL_STEP : INT; {access Read Only}
END_VAR
VAR
   SEQCTRL_CMD : INT;
   SEQCTRL_DONE : INT;
   SEQCTRL_CMD_TABLE : INT[35];
   SEQCTRL_NEXT_STEP : INT;
   TEMP : INT;
   j : INT;
   b : DINT;
   B256_MUL : B256_MUL;
   B256_SQU : B256_SQU;
END_VAR

ROUTINE Logic   (* ladder *)
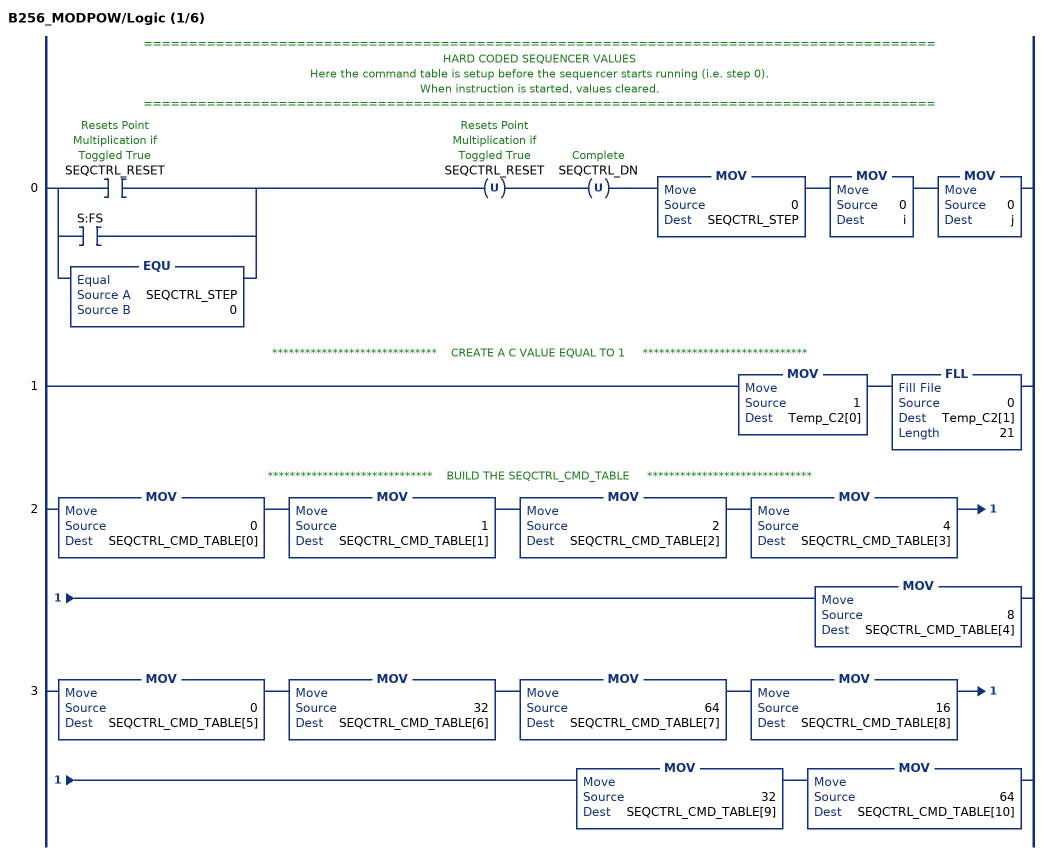
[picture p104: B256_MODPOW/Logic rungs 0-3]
   // ========================================================================================
   // HARD CODED SEQUENCER VALUES
   // Here the command table is setup before the sequencer starts running (i.e. step 0).
   // When instruction is started, values cleared.
   // ========================================================================================
   0: [[XIC(SEQCTRL_RESET) ,XIC(S:FS) ] ,EQU(SEQCTRL_STEP,0) ]OTU(SEQCTRL_RESET)OTU(SEQCTRL_DN)MOV(0,SEQCTRL_STEP)MOV(0,i)MOV(0,j);
   // ******************************    CREATE A C VALUE EQUAL TO 1     ******************************
   1: MOV(1,Temp_C2[0])FLL(0,Temp_C2[1],21);
   // ******************************    BUILD THE SEQCTRL_CMD_TABLE     ******************************
   2: MOV(0,SEQCTRL_CMD_TABLE[0])MOV(1,SEQCTRL_CMD_TABLE[1])MOV(2,SEQCTRL_CMD_TABLE[2])MOV(4,SEQCTRL_CMD_TABLE[3])MOV(8,SEQCTRL_CMD_TABLE[4]);
   3: MOV(0,SEQCTRL_CMD_TABLE[5])MOV(32,SEQCTRL_CMD_TABLE[6])MOV(64,SEQCTRL_CMD_TABLE[7])MOV(16,SEQCTRL_CMD_TABLE[8])MOV(32,SEQCTRL_CMD_TABLE[9])MOV(64,SEQCTRL_CMD_TABLE[10]);
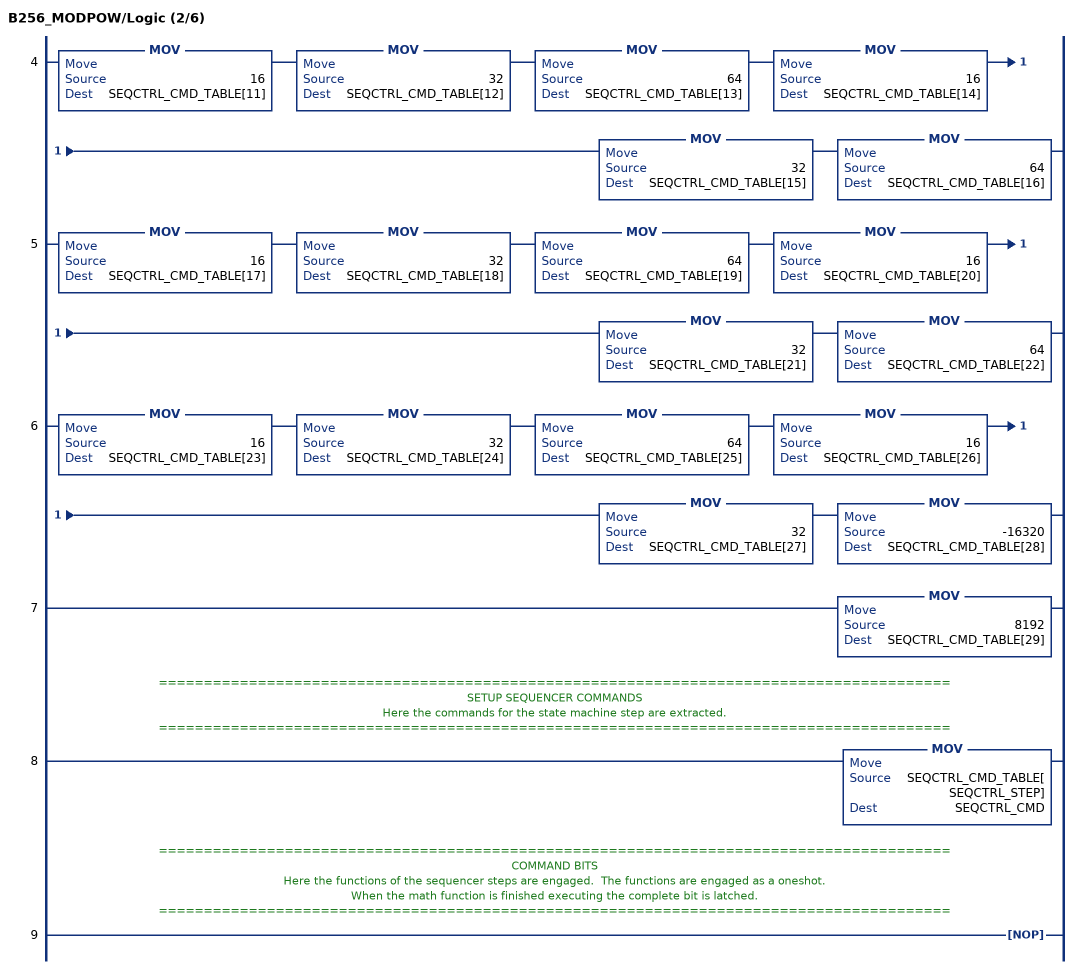
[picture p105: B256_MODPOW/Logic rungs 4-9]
   4: MOV(16,SEQCTRL_CMD_TABLE[11])MOV(32,SEQCTRL_CMD_TABLE[12])MOV(64,SEQCTRL_CMD_TABLE[13])MOV(16,SEQCTRL_CMD_TABLE[14])MOV(32,SEQCTRL_CMD_TABLE[15])MOV(64,SEQCTRL_CMD_TABLE[16]);
   5: MOV(16,SEQCTRL_CMD_TABLE[17])MOV(32,SEQCTRL_CMD_TABLE[18])MOV(64,SEQCTRL_CMD_TABLE[19])MOV(16,SEQCTRL_CMD_TABLE[20])MOV(32,SEQCTRL_CMD_TABLE[21])MOV(64,SEQCTRL_CMD_TABLE[22]);
   6: MOV(16,SEQCTRL_CMD_TABLE[23])MOV(32,SEQCTRL_CMD_TABLE[24])MOV(64,SEQCTRL_CMD_TABLE[25])MOV(16,SEQCTRL_CMD_TABLE[26])MOV(32,SEQCTRL_CMD_TABLE[27])MOV(-16320,SEQCTRL_CMD_TABLE[28]);
   7: MOV(8192,SEQCTRL_CMD_TABLE[29]);
   // ========================================================================================
   // SETUP SEQUENCER COMMANDS
   // Here the commands for the state machine step are extracted.
   // ========================================================================================
   8: MOV(SEQCTRL_CMD_TABLE[SEQCTRL_STEP],SEQCTRL_CMD);
   // ========================================================================================
   // COMMAND BITS
   // Here the functions of the sequencer steps are engaged.  The functions are engaged as a oneshot.
   // When the math function is finished executing the complete bit is latched.
   // ========================================================================================
   9: NOP();
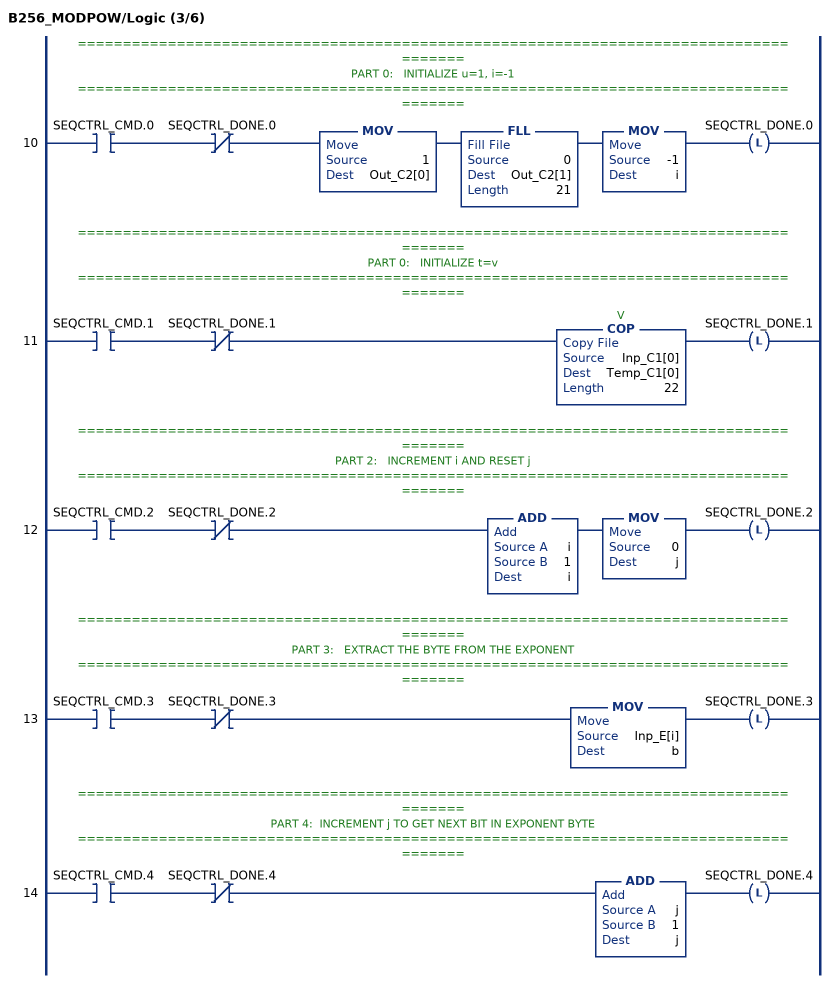
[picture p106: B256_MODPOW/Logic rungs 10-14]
   // ======================================================================================
   // PART 0:   INITIALIZE u=1, i=-1
   // ======================================================================================
   10: XIC(SEQCTRL_CMD.0)XIO(SEQCTRL_DONE.0)MOV(1,Out_C2[0])FLL(0,Out_C2[1],21)MOV(-1,i)OTL(SEQCTRL_DONE.0);
   // ======================================================================================
   // PART 0:   INITIALIZE t=v
   // ======================================================================================
   11: XIC(SEQCTRL_CMD.1)XIO(SEQCTRL_DONE.1)COP(Inp_C1[0],Temp_C1[0],22)OTL(SEQCTRL_DONE.1);
   // ======================================================================================
   // PART 2:   INCREMENT i AND RESET j
   // ======================================================================================
   12: XIC(SEQCTRL_CMD.2)XIO(SEQCTRL_DONE.2)ADD(i,1,i)MOV(0,j)OTL(SEQCTRL_DONE.2);
   // ======================================================================================
   // PART 3:   EXTRACT THE BYTE FROM THE EXPONENT
   // ======================================================================================
   13: XIC(SEQCTRL_CMD.3)XIO(SEQCTRL_DONE.3)MOV(Inp_E[i],b)OTL(SEQCTRL_DONE.3);
   // ======================================================================================
   // PART 4:  INCREMENT j TO GET NEXT BIT IN EXPONENT BYTE
   // ======================================================================================
   14: XIC(SEQCTRL_CMD.4)XIO(SEQCTRL_DONE.4)ADD(j,1,j)OTL(SEQCTRL_DONE.4);
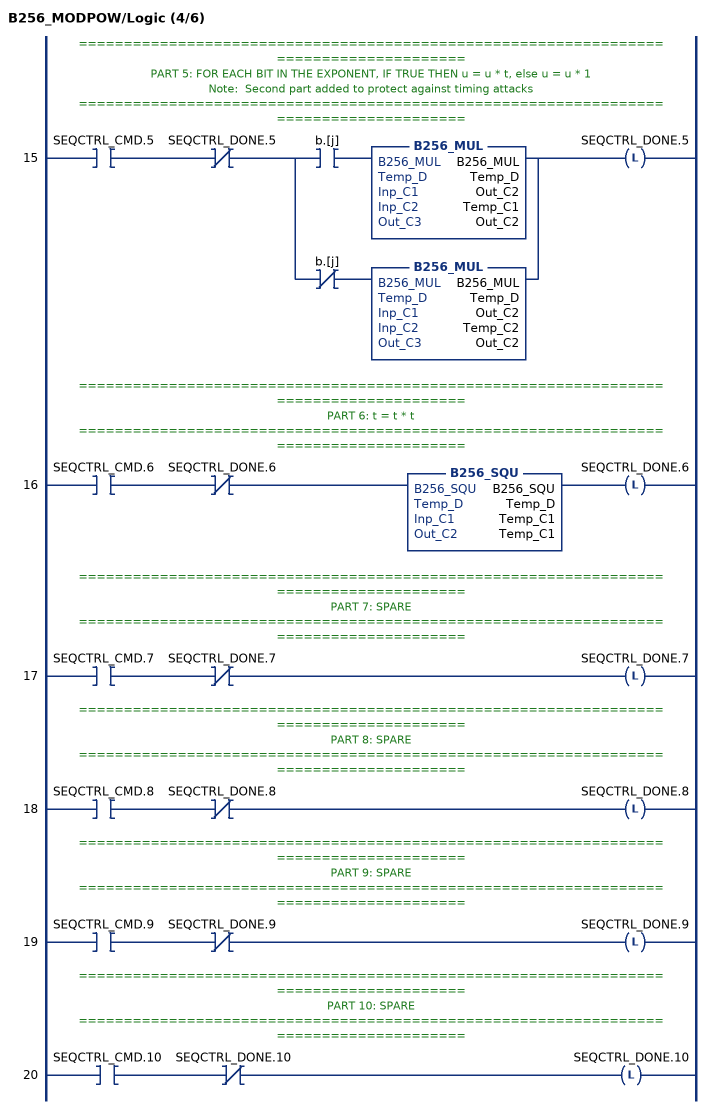
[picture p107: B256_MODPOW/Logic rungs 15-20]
   // ======================================================================================
   // PART 5: FOR EACH BIT IN THE EXPONENT, IF TRUE THEN u = u * t, else u = u * 1
   // Note:  Second part added to protect against timing attacks
   // ======================================================================================
   15: XIC(SEQCTRL_CMD.5)XIO(SEQCTRL_DONE.5)[XIC(b.[j]) B256_MUL(B256_MUL,Temp_D,Out_C2,Temp_C1,Out_C2) ,XIO(b.[j]) B256_MUL(B256_MUL,Temp_D,Out_C2,Temp_C2,Out_C2) ]OTL(SEQCTRL_DONE.5);
   // ======================================================================================
   // PART 6: t = t * t
   // ======================================================================================
   16: XIC(SEQCTRL_CMD.6)XIO(SEQCTRL_DONE.6)B256_SQU(B256_SQU,Temp_D,Temp_C1,Temp_C1)OTL(SEQCTRL_DONE.6);
   // ======================================================================================
   // PART 7: SPARE
   // ======================================================================================
   17: XIC(SEQCTRL_CMD.7)XIO(SEQCTRL_DONE.7)OTL(SEQCTRL_DONE.7);
   // ======================================================================================
   // PART 8: SPARE
   // ======================================================================================
   18: XIC(SEQCTRL_CMD.8)XIO(SEQCTRL_DONE.8)OTL(SEQCTRL_DONE.8);
   // ======================================================================================
   // PART 9: SPARE
   // ======================================================================================
   19: XIC(SEQCTRL_CMD.9)XIO(SEQCTRL_DONE.9)OTL(SEQCTRL_DONE.9);
   // ======================================================================================
   // PART 10: SPARE
   // ======================================================================================
   20: XIC(SEQCTRL_CMD.10)XIO(SEQCTRL_DONE.10)OTL(SEQCTRL_DONE.10);
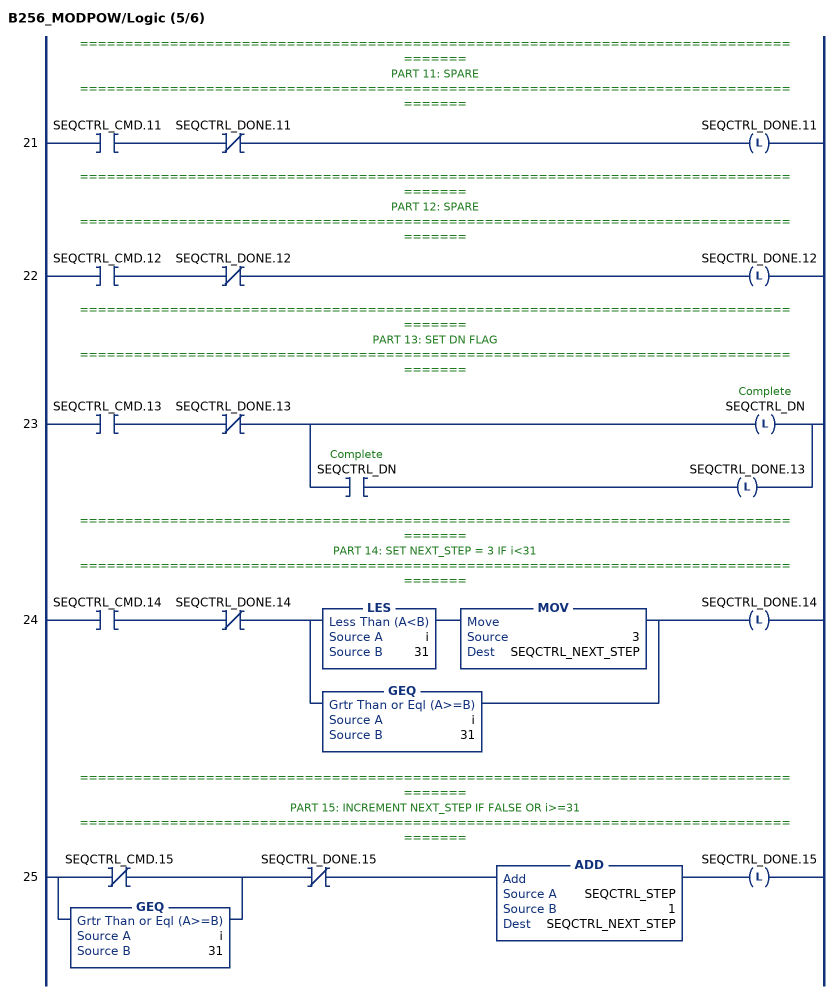
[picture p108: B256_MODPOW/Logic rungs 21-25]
   // ======================================================================================
   // PART 11: SPARE
   // ======================================================================================
   21: XIC(SEQCTRL_CMD.11)XIO(SEQCTRL_DONE.11)OTL(SEQCTRL_DONE.11);
   // ======================================================================================
   // PART 12: SPARE
   // ======================================================================================
   22: XIC(SEQCTRL_CMD.12)XIO(SEQCTRL_DONE.12)OTL(SEQCTRL_DONE.12);
   // ======================================================================================
   // PART 13: SET DN FLAG
   // ======================================================================================
   23: XIC(SEQCTRL_CMD.13)XIO(SEQCTRL_DONE.13)[OTL(SEQCTRL_DN) ,XIC(SEQCTRL_DN) OTL(SEQCTRL_DONE.13) ];
   // ======================================================================================
   // PART 14: SET NEXT_STEP = 3 IF i<31
   // ======================================================================================
   24: XIC(SEQCTRL_CMD.14)XIO(SEQCTRL_DONE.14)[LES(i,31) MOV(3,SEQCTRL_NEXT_STEP) ,GEQ(i,31) ]OTL(SEQCTRL_DONE.14);
   // ======================================================================================
   // PART 15: INCREMENT NEXT_STEP IF FALSE OR i>=31
   // ======================================================================================
   25: [XIO(SEQCTRL_CMD.15) ,GEQ(i,31) ]XIO(SEQCTRL_DONE.15)ADD(SEQCTRL_STEP,1,SEQCTRL_NEXT_STEP)OTL(SEQCTRL_DONE.15);
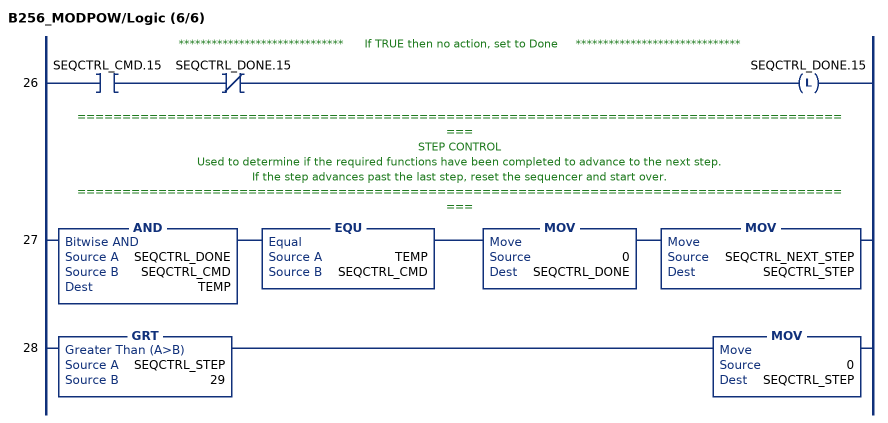
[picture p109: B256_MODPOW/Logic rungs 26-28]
   // ******************************      If TRUE then no action, set to Done     ******************************
   26: XIC(SEQCTRL_CMD.15)XIO(SEQCTRL_DONE.15)OTL(SEQCTRL_DONE.15);
   // ========================================================================================
   // STEP CONTROL
   // Used to determine if the required functions have been completed to advance to the next step.
   // If the step advances past the last step, reset the sequencer and start over.
   // ========================================================================================
   27: AND(SEQCTRL_DONE,SEQCTRL_CMD,TEMP)EQU(TEMP,SEQCTRL_CMD)MOV(0,SEQCTRL_DONE)MOV(SEQCTRL_NEXT_STEP,SEQCTRL_STEP);
   28: GRT(SEQCTRL_STEP,29)MOV(0,SEQCTRL_STEP);
END_ROUTINE
END_ADD_ON_INSTRUCTION
(* Logix 5000 AddOnInstructionDefinition export Ed25519_VERIFY; software revision 30.00; part 6 of 7 *)

ADD_ON_INSTRUCTION B256_NEG   (* revision 1.0 20170916, vendor Kenneth A. Fischer *)
// c2 = -c1 (mod p)
// Revision note:
// Rev1.0: 20170916 - Initial Release
VAR_OUTPUT
   FAIL : BOOL; {access Read Only}   // Indicates negative overflow which should not happen
END_VAR
VAR_IN_OUT
   Inp_C1 : DINT[22]; {required}
   Out_C2 : DINT[22]; {required}
END_VAR
VAR
   s : DINT;
   b : DINT;
   i : DINT;
END_VAR

ROUTINE Logic   (* ladder *)
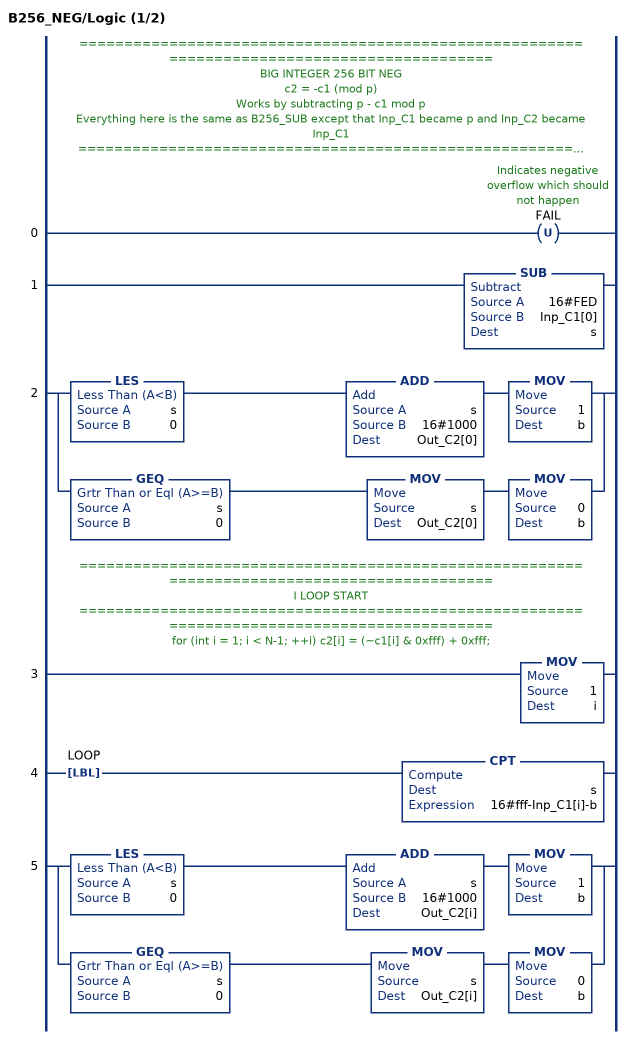
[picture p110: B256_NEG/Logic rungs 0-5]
   // ============================================================================================
   // BIG INTEGER 256 BIT NEG
   // c2 = -c1 (mod p)
   // Works by subtracting p - c1 mod p
   // Everything here is the same as B256_SUB except that Inp_C1 became p and Inp_C2 became Inp_C1
   // ============================================================================================
   0: OTU(FAIL);
   1: SUB(16#FED,Inp_C1[0],s);
   2: [LES(s,0) ADD(s,16#1000,Out_C2[0]) MOV(1,b) ,GEQ(s,0) MOV(s,Out_C2[0]) MOV(0,b) ];
   // ============================================================================================
   // I LOOP START
   // ============================================================================================
   // for (int i = 1; i < N-1; ++i) c2[i] = (~c1[i] & 0xfff) + 0xfff;
   3: MOV(1,i);
   4: LBL(LOOP)CPT(s,16#fff-Inp_C1[i]-b);
   5: [LES(s,0) ADD(s,16#1000,Out_C2[i]) MOV(1,b) ,GEQ(s,0) MOV(s,Out_C2[i]) MOV(0,b) ];
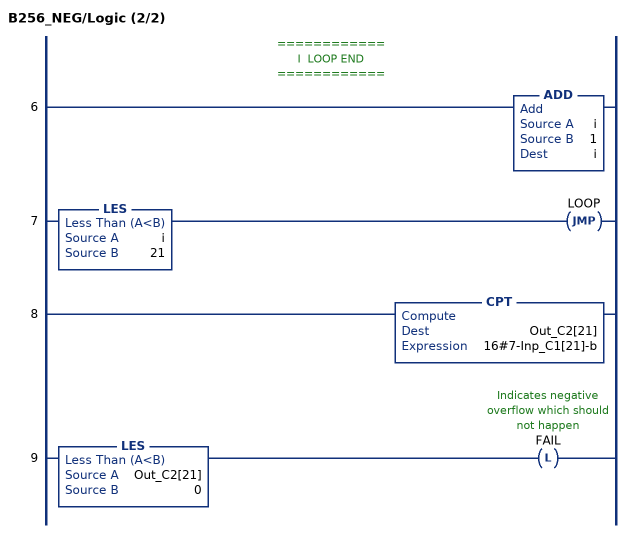
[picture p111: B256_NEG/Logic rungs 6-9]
   // ============
   // I  LOOP END
   // ============
   6: ADD(i,1,i);
   7: LES(i,21)JMP(LOOP);
   8: CPT(Out_C2[21],16#7-Inp_C1[21]-b);
   9: LES(Out_C2[21],0)OTL(FAIL);
END_ROUTINE
END_ADD_ON_INSTRUCTION

ADD_ON_INSTRUCTION POINT_DEC   (* revision 1.0 20170916, vendor Kenneth A. Fischer *)
// Point Decode:
// Decode a string value representing a point (x,y) into POINT data type in extended coordinates pieces
// Requires POINT UDT
// Revision note:
// Rev1.0: 20170916 - Initial Release
VAR_INPUT
   SEQCTRL_RESET : BOOL;   // Resets Point Multiplication if Toggled True
END_VAR
VAR_OUTPUT
   SEQCTRL_DN : BOOL; {access Read Only}   // Complete
   SEQCTRL_STEP : INT; {access Read Only}
   SEQCTRL_SUBSTEP : INT; {access Read Only}
   FAILED : BOOL; {access Read Only}
END_VAR
VAR_IN_OUT
   Temp_C1 : DINT[22]; {required}   // d
   Temp_C2 : DINT[22]; {required}   // m-1
   Temp_C3 : DINT[22]; {required}   // sqrtm1 = 2^((m-1)/4)
   Temp_C4 : DINT[22]; {required}   // u
   Temp_C5 : DINT[22]; {required}   // v
   Temp_C6 : DINT[22]; {required}   // v2
   Temp_C7 : DINT[22]; {required}   // v4
   Temp_C8 : DINT[22]; {required}   // t1
   Temp_C9 : DINT[22]; {required}   // t2
   Temp_C10 : DINT[22]; {required}   // t3
   Temp_C11 : DINT[22]; {required}
   Temp_C12 : DINT[22]; {required}
   Temp_D : DINT[43]; {required}
   Temp_E : DINT[32]; {required}   // m58 = (m-5)/8
   Inp_SLE : STRING; {required}   // Encoded Point as a String
   Out_P : POINT; {required}   // POINT in extended coordinates
END_VAR
VAR
   SEQCTRL_CMD : DINT;
   SEQCTRL_DONE : DINT;
   SEQCTRL_NEXT_STEP : INT;
   SEQCTRL_CMD_TABLE : DINT[40];
   TEMP : DINT;
   B256_StoC_LE : B256_StoC_LE;
   x_0 : BOOL;
   B256_SQU : B256_SQU;
   B256_SUB : B256_SUB;
   B256_MUL : B256_MUL;
   B256_ADD : B256_ADD;
   B256_MODPOW : B256_MODPOW;
   SEQCTRL_ONS : DINT;
   B256_COMPARE : B256_COMPARE;
   B256_NEG : B256_NEG;
   B256_COMPARE1 : B256_COMPARE;
   B256_COMPARE2 : B256_COMPARE;
   B256_ADJ : B256_ADJ;
   B256_DEC : B256_DEC;
END_VAR

ROUTINE Logic   (* ladder *)
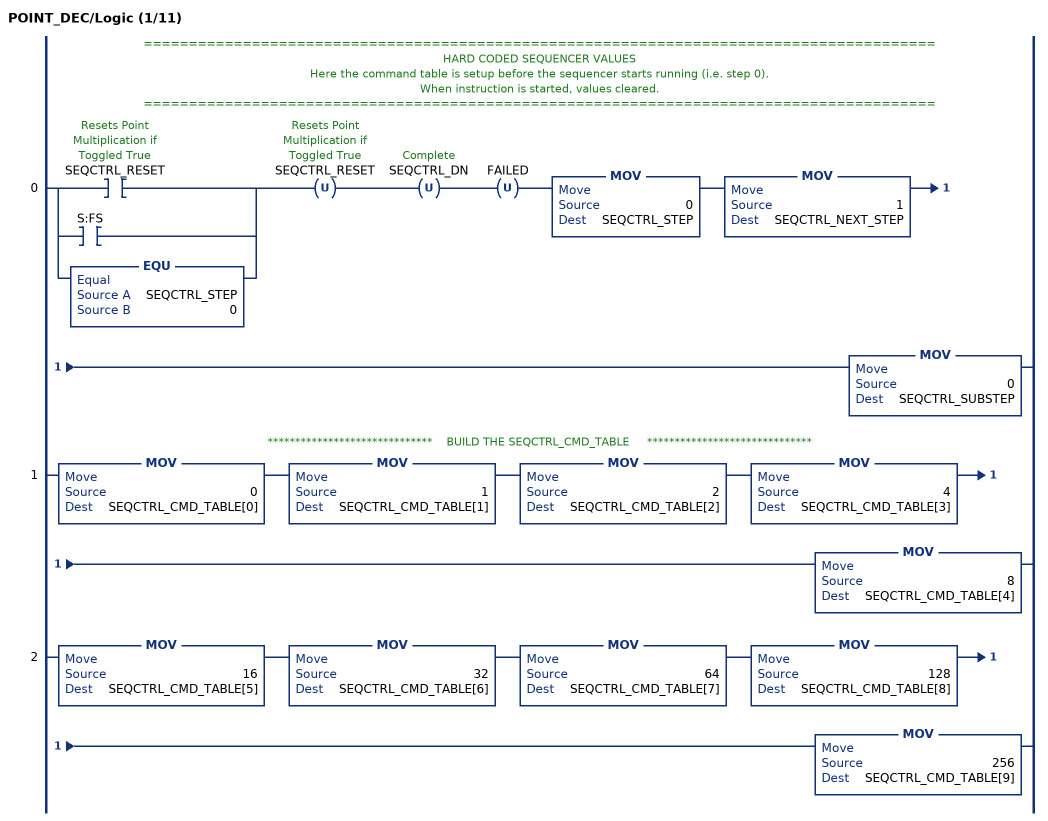
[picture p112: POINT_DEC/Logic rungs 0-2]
   // ========================================================================================
   // HARD CODED SEQUENCER VALUES
   // Here the command table is setup before the sequencer starts running (i.e. step 0).
   // When instruction is started, values cleared.
   // ========================================================================================
   0: [[XIC(SEQCTRL_RESET) ,XIC(S:FS) ] ,EQU(SEQCTRL_STEP,0) ]OTU(SEQCTRL_RESET)OTU(SEQCTRL_DN)OTU(FAILED)MOV(0,SEQCTRL_STEP)MOV(1,SEQCTRL_NEXT_STEP)MOV(0,SEQCTRL_SUBSTEP);
   // ******************************    BUILD THE SEQCTRL_CMD_TABLE     ******************************
   1: MOV(0,SEQCTRL_CMD_TABLE[0])MOV(1,SEQCTRL_CMD_TABLE[1])MOV(2,SEQCTRL_CMD_TABLE[2])MOV(4,SEQCTRL_CMD_TABLE[3])MOV(8,SEQCTRL_CMD_TABLE[4]);
   2: MOV(16,SEQCTRL_CMD_TABLE[5])MOV(32,SEQCTRL_CMD_TABLE[6])MOV(64,SEQCTRL_CMD_TABLE[7])MOV(128,SEQCTRL_CMD_TABLE[8])MOV(256,SEQCTRL_CMD_TABLE[9]);
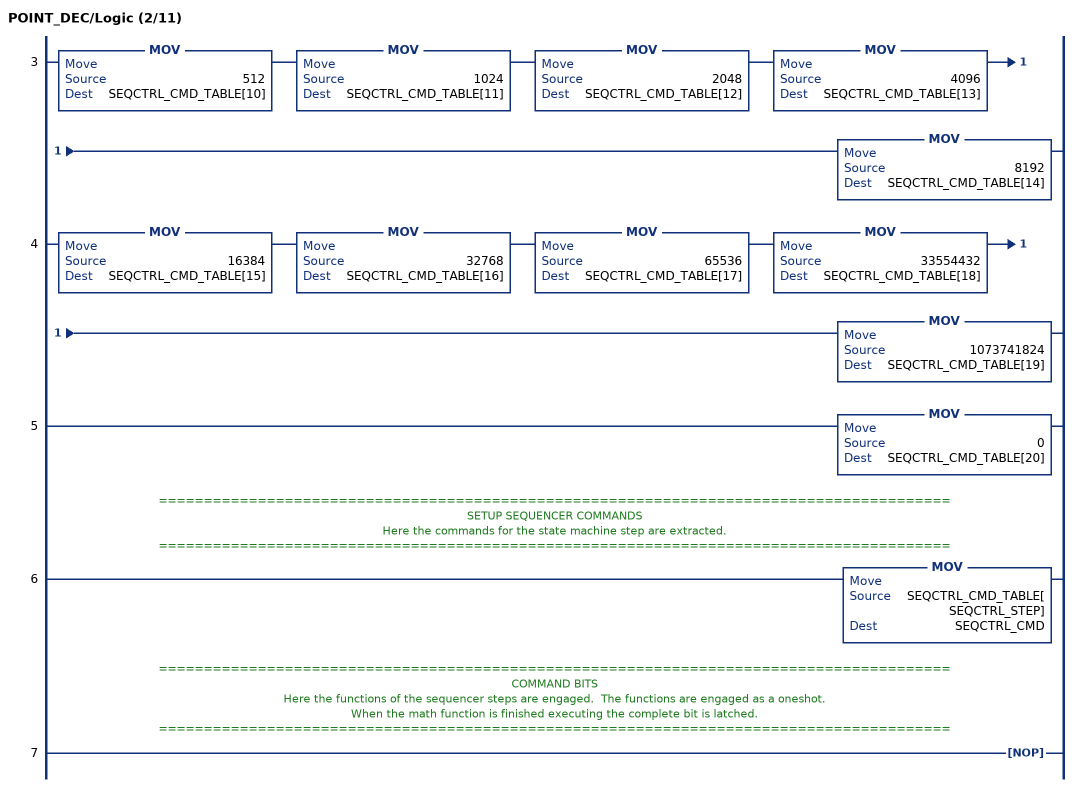
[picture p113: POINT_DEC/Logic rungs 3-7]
   3: MOV(512,SEQCTRL_CMD_TABLE[10])MOV(1024,SEQCTRL_CMD_TABLE[11])MOV(2048,SEQCTRL_CMD_TABLE[12])MOV(4096,SEQCTRL_CMD_TABLE[13])MOV(8192,SEQCTRL_CMD_TABLE[14]);
   4: MOV(16384,SEQCTRL_CMD_TABLE[15])MOV(32768,SEQCTRL_CMD_TABLE[16])MOV(65536,SEQCTRL_CMD_TABLE[17])MOV(33554432,SEQCTRL_CMD_TABLE[18])MOV(1073741824,SEQCTRL_CMD_TABLE[19]);
   5: MOV(0,SEQCTRL_CMD_TABLE[20]);
   // ========================================================================================
   // SETUP SEQUENCER COMMANDS
   // Here the commands for the state machine step are extracted.
   // ========================================================================================
   6: MOV(SEQCTRL_CMD_TABLE[SEQCTRL_STEP],SEQCTRL_CMD);
   // ========================================================================================
   // COMMAND BITS
   // Here the functions of the sequencer steps are engaged.  The functions are engaged as a oneshot.
   // When the math function is finished executing the complete bit is latched.
   // ========================================================================================
   7: NOP();
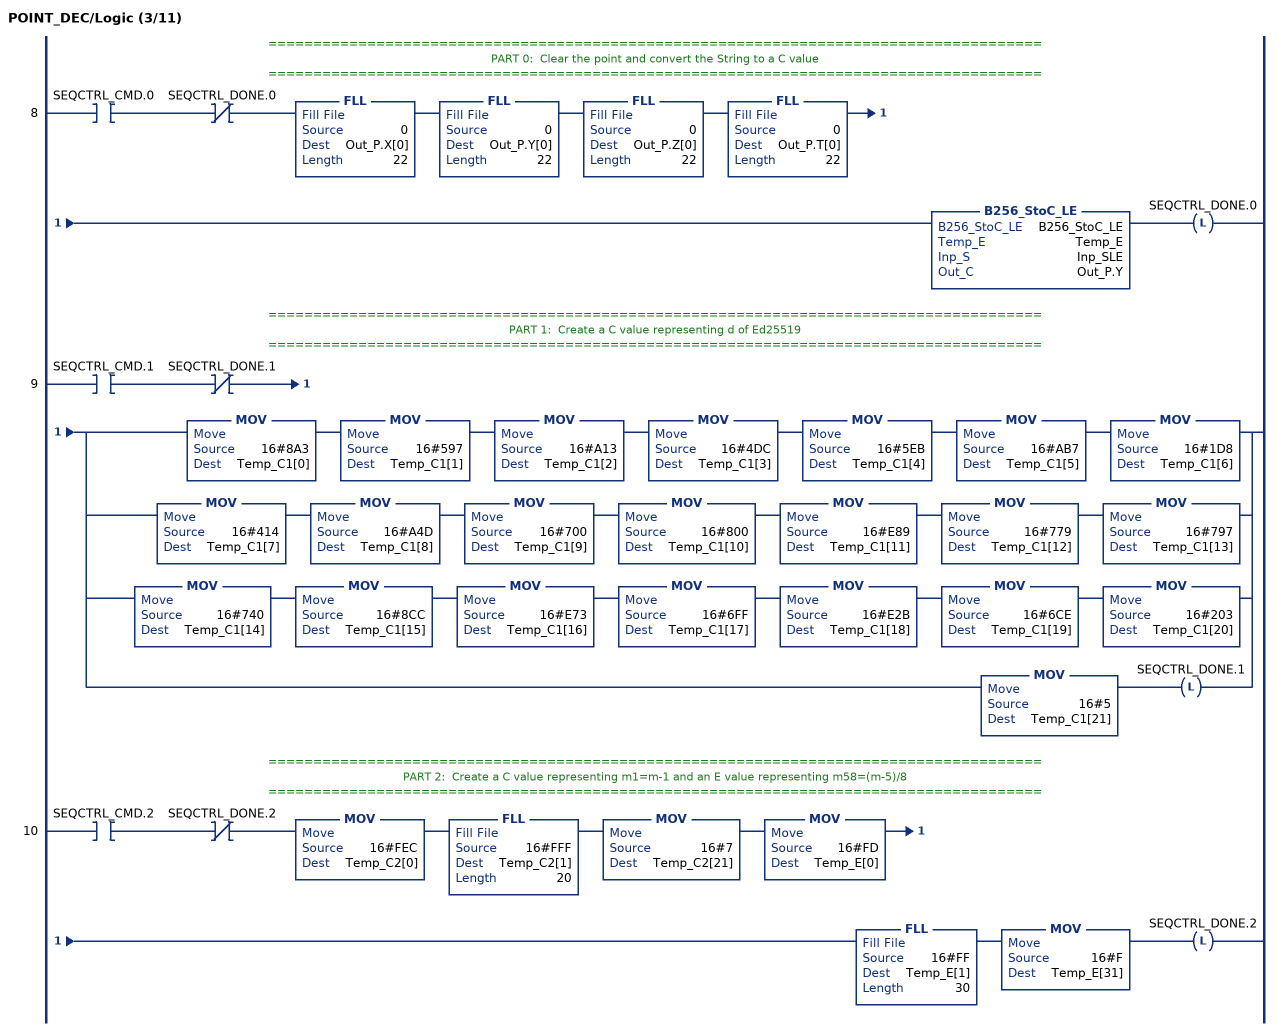
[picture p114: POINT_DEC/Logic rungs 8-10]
   // ======================================================================================
   // PART 0:  Clear the point and convert the String to a C value
   // ======================================================================================
   8: XIC(SEQCTRL_CMD.0)XIO(SEQCTRL_DONE.0)FLL(0,Out_P.X[0],22)FLL(0,Out_P.Y[0],22)FLL(0,Out_P.Z[0],22)FLL(0,Out_P.T[0],22)B256_StoC_LE(B256_StoC_LE,Temp_E,Inp_SLE,Out_P.Y)OTL(SEQCTRL_DONE.0);
   // ======================================================================================
   // PART 1:  Create a C value representing d of Ed25519
   // ======================================================================================
   9: XIC(SEQCTRL_CMD.1)XIO(SEQCTRL_DONE.1)[MOV(16#8A3,Temp_C1[0]) MOV(16#597,Temp_C1[1]) MOV(16#A13,Temp_C1[2]) MOV(16#4DC,Temp_C1[3]) MOV(16#5EB,Temp_C1[4]) MOV(16#AB7,Temp_C1[5]) MOV(16#1D8,Temp_C1[6]) ,MOV(16#414,Temp_C1[7]) MOV(16#A4D,Temp_C1[8]) MOV(16#700,Temp_C1[9]) MOV(16#800,Temp_C1[10]) MOV(16#E89,Temp_C1[11]) MOV(16#779,Temp_C1[12]) MOV(16#797,Temp_C1[13]) ,MOV(16#740,Temp_C1[14]) MOV(16#8CC,Temp_C1[15]) MOV(16#E73,Temp_C1[16]) MOV(16#6FF,Temp_C1[17]) MOV(16#E2B,Temp_C1[18]) MOV(16#6CE,Temp_C1[19]) MOV(16#203,Temp_C1[20]) ,MOV(16#5,Temp_C1[21]) OTL(SEQCTRL_DONE.1) ];
   // ======================================================================================
   // PART 2:  Create a C value representing m1=m-1 and an E value representing m58=(m-5)/8
   // ======================================================================================
   10: XIC(SEQCTRL_CMD.2)XIO(SEQCTRL_DONE.2)MOV(16#FEC,Temp_C2[0])FLL(16#FFF,Temp_C2[1],20)MOV(16#7,Temp_C2[21])MOV(16#FD,Temp_E[0])FLL(16#FF,Temp_E[1],30)MOV(16#F,Temp_E[31])OTL(SEQCTRL_DONE.2);
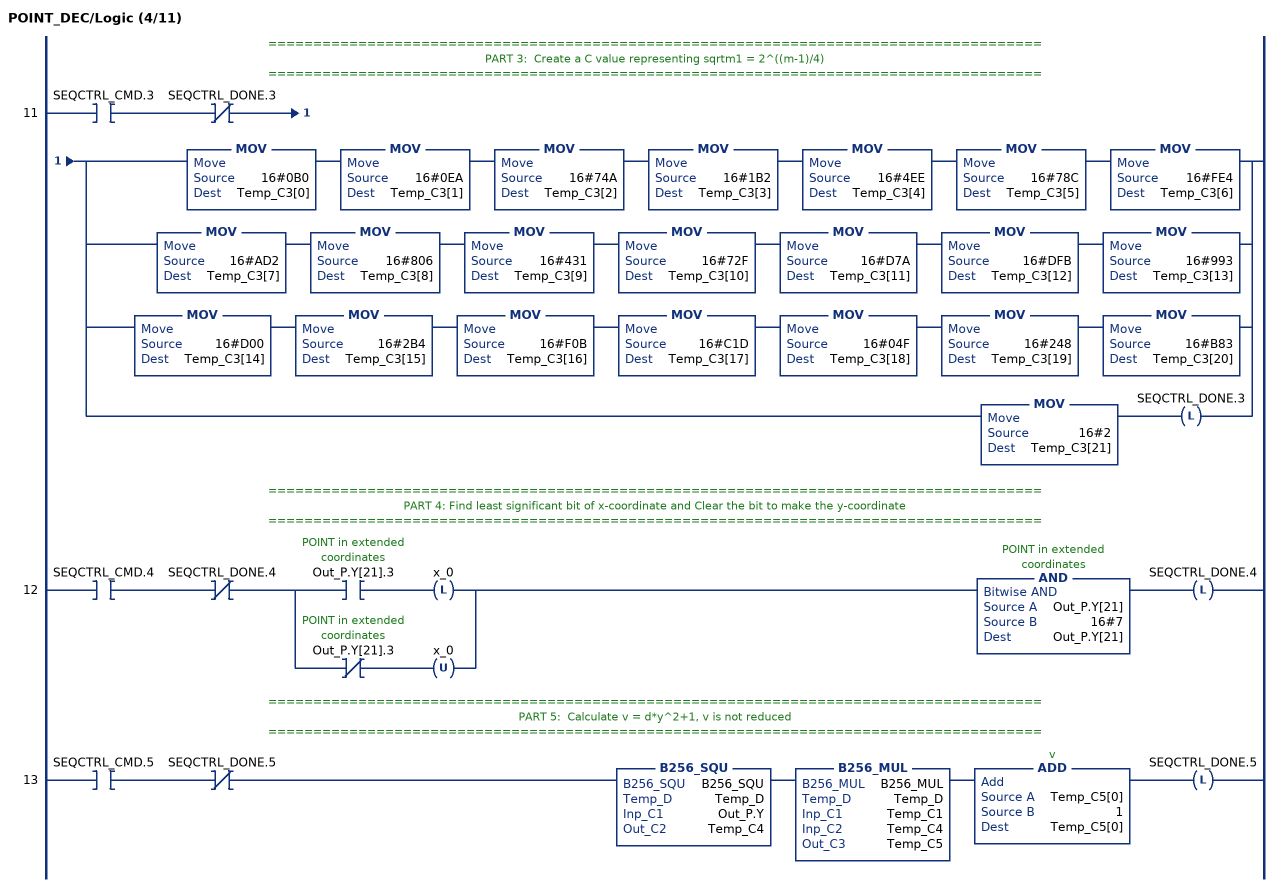
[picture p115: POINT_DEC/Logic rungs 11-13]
   // ======================================================================================
   // PART 3:  Create a C value representing sqrtm1 = 2^((m-1)/4)
   // ======================================================================================
   11: XIC(SEQCTRL_CMD.3)XIO(SEQCTRL_DONE.3)[MOV(16#0B0,Temp_C3[0]) MOV(16#0EA,Temp_C3[1]) MOV(16#74A,Temp_C3[2]) MOV(16#1B2,Temp_C3[3]) MOV(16#4EE,Temp_C3[4]) MOV(16#78C,Temp_C3[5]) MOV(16#FE4,Temp_C3[6]) ,MOV(16#AD2,Temp_C3[7]) MOV(16#806,Temp_C3[8]) MOV(16#431,Temp_C3[9]) MOV(16#72F,Temp_C3[10]) MOV(16#D7A,Temp_C3[11]) MOV(16#DFB,Temp_C3[12]) MOV(16#993,Temp_C3[13]) ,MOV(16#D00,Temp_C3[14]) MOV(16#2B4,Temp_C3[15]) MOV(16#F0B,Temp_C3[16]) MOV(16#C1D,Temp_C3[17]) MOV(16#04F,Temp_C3[18]) MOV(16#248,Temp_C3[19]) MOV(16#B83,Temp_C3[20]) ,MOV(16#2,Temp_C3[21]) OTL(SEQCTRL_DONE.3) ];
   // ======================================================================================
   // PART 4: Find least significant bit of x-coordinate and Clear the bit to make the y-coordinate
   // ======================================================================================
   12: XIC(SEQCTRL_CMD.4)XIO(SEQCTRL_DONE.4)[XIC(Out_P.Y[21].3) OTL(x_0) ,XIO(Out_P.Y[21].3) OTU(x_0) ]AND(Out_P.Y[21],16#7,Out_P.Y[21])OTL(SEQCTRL_DONE.4);
   // ======================================================================================
   // PART 5:  Calculate v = d*y^2+1, v is not reduced
   // ======================================================================================
   13: XIC(SEQCTRL_CMD.5)XIO(SEQCTRL_DONE.5)B256_SQU(B256_SQU,Temp_D,Out_P.Y,Temp_C4)B256_MUL(B256_MUL,Temp_D,Temp_C1,Temp_C4,Temp_C5)ADD(Temp_C5[0],1,Temp_C5[0])OTL(SEQCTRL_DONE.5);
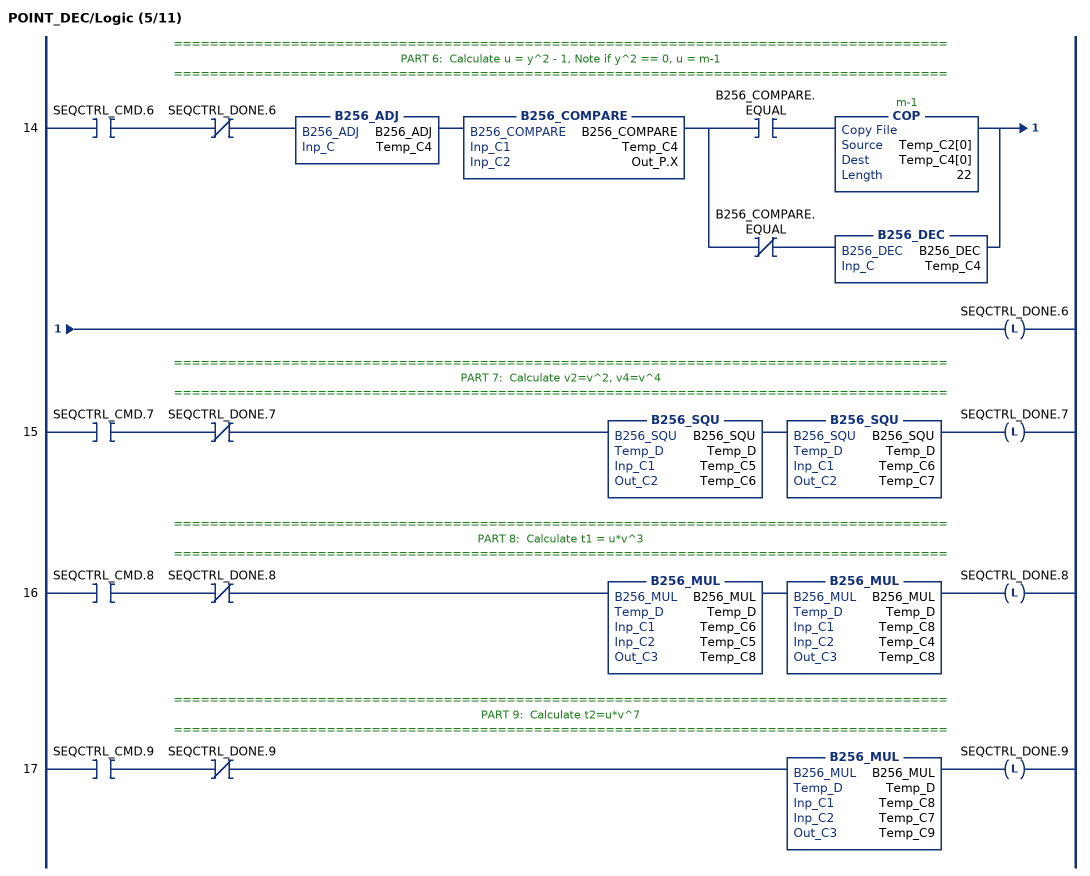
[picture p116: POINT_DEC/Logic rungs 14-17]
   // ======================================================================================
   // PART 6:  Calculate u = y^2 - 1, Note if y^2 == 0, u = m-1
   // ======================================================================================
   14: XIC(SEQCTRL_CMD.6)XIO(SEQCTRL_DONE.6)B256_ADJ(B256_ADJ,Temp_C4)B256_COMPARE(B256_COMPARE,Temp_C4,Out_P.X)[XIC(B256_COMPARE.EQUAL) COP(Temp_C2[0],Temp_C4[0],22) ,XIO(B256_COMPARE.EQUAL) B256_DEC(B256_DEC,Temp_C4) ]OTL(SEQCTRL_DONE.6);
   // ======================================================================================
   // PART 7:  Calculate v2=v^2, v4=v^4
   // ======================================================================================
   15: XIC(SEQCTRL_CMD.7)XIO(SEQCTRL_DONE.7)B256_SQU(B256_SQU,Temp_D,Temp_C5,Temp_C6)B256_SQU(B256_SQU,Temp_D,Temp_C6,Temp_C7)OTL(SEQCTRL_DONE.7);
   // ======================================================================================
   // PART 8:  Calculate t1 = u*v^3
   // ======================================================================================
   16: XIC(SEQCTRL_CMD.8)XIO(SEQCTRL_DONE.8)B256_MUL(B256_MUL,Temp_D,Temp_C6,Temp_C5,Temp_C8)B256_MUL(B256_MUL,Temp_D,Temp_C8,Temp_C4,Temp_C8)OTL(SEQCTRL_DONE.8);
   // ======================================================================================
   // PART 9:  Calculate t2=u*v^7
   // ======================================================================================
   17: XIC(SEQCTRL_CMD.9)XIO(SEQCTRL_DONE.9)B256_MUL(B256_MUL,Temp_D,Temp_C8,Temp_C7,Temp_C9)OTL(SEQCTRL_DONE.9);
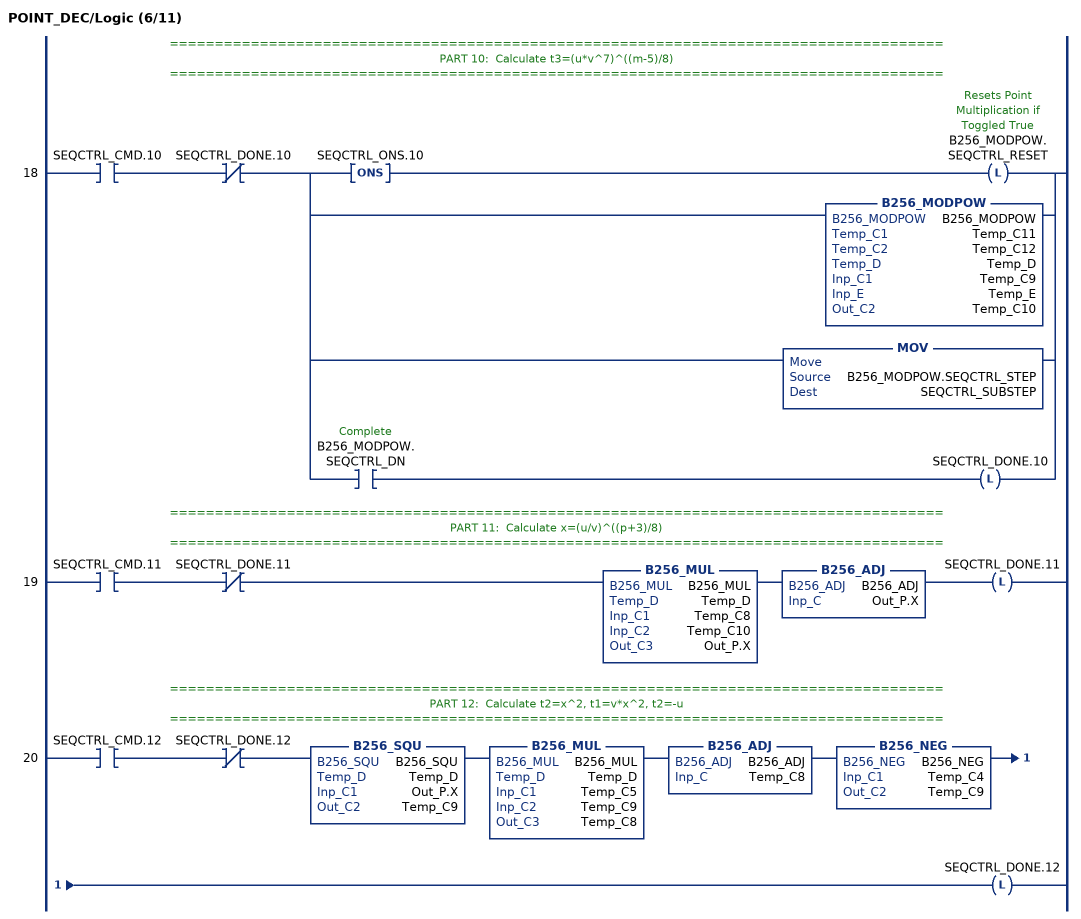
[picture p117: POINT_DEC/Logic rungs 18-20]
   // ======================================================================================
   // PART 10:  Calculate t3=(u*v^7)^((m-5)/8)
   // ======================================================================================
   18: XIC(SEQCTRL_CMD.10)XIO(SEQCTRL_DONE.10)[ONS(SEQCTRL_ONS.10) OTL(B256_MODPOW.SEQCTRL_RESET) ,B256_MODPOW(B256_MODPOW,Temp_C11,Temp_C12,Temp_D,Temp_C9,Temp_E,Temp_C10) ,MOV(B256_MODPOW.SEQCTRL_STEP,SEQCTRL_SUBSTEP) ,XIC(B256_MODPOW.SEQCTRL_DN) OTL(SEQCTRL_DONE.10) ];
   // ======================================================================================
   // PART 11:  Calculate x=(u/v)^((p+3)/8)
   // ======================================================================================
   19: XIC(SEQCTRL_CMD.11)XIO(SEQCTRL_DONE.11)B256_MUL(B256_MUL,Temp_D,Temp_C8,Temp_C10,Out_P.X)B256_ADJ(B256_ADJ,Out_P.X)OTL(SEQCTRL_DONE.11);
   // ======================================================================================
   // PART 12:  Calculate t2=x^2, t1=v*x^2, t2=-u
   // ======================================================================================
   20: XIC(SEQCTRL_CMD.12)XIO(SEQCTRL_DONE.12)B256_SQU(B256_SQU,Temp_D,Out_P.X,Temp_C9)B256_MUL(B256_MUL,Temp_D,Temp_C5,Temp_C9,Temp_C8)B256_ADJ(B256_ADJ,Temp_C8)B256_NEG(B256_NEG,Temp_C4,Temp_C9)OTL(SEQCTRL_DONE.12);
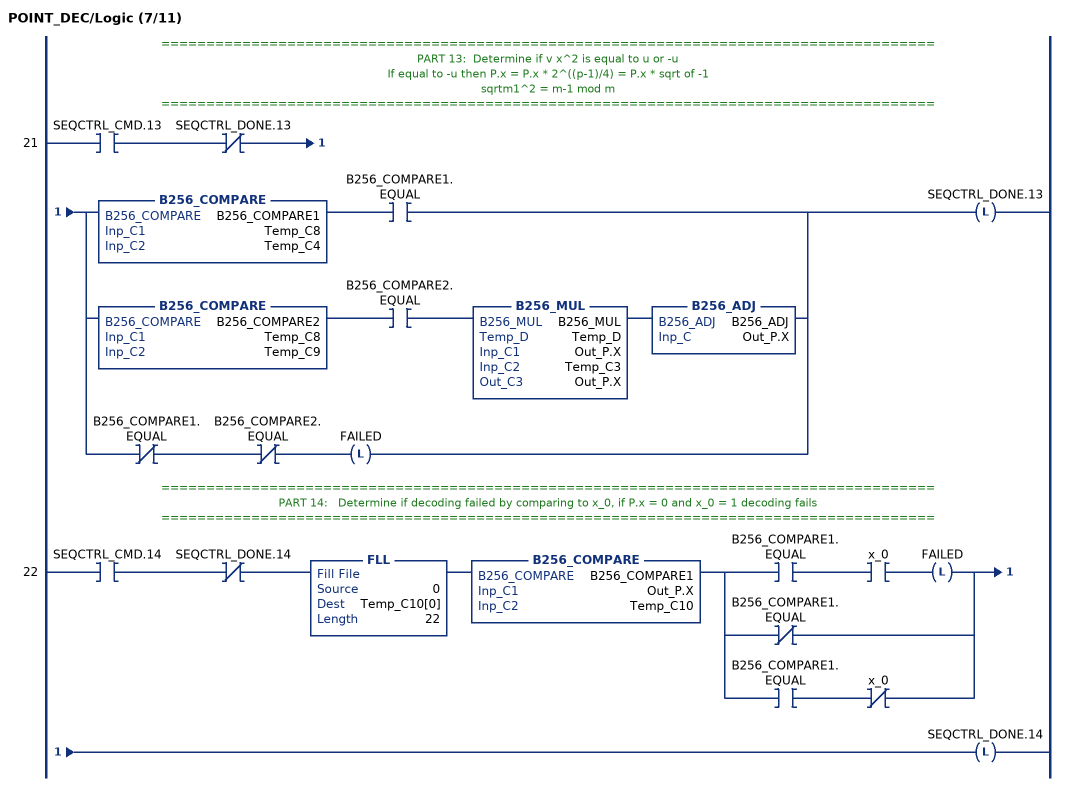
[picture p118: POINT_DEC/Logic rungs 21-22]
   // ======================================================================================
   // PART 13:  Determine if v x^2 is equal to u or -u
   // If equal to -u then P.x = P.x * 2^((p-1)/4) = P.x * sqrt of -1
   // sqrtm1^2 = m-1 mod m
   // ======================================================================================
   21: XIC(SEQCTRL_CMD.13)XIO(SEQCTRL_DONE.13)[B256_COMPARE(B256_COMPARE1,Temp_C8,Temp_C4) XIC(B256_COMPARE1.EQUAL) ,B256_COMPARE(B256_COMPARE2,Temp_C8,Temp_C9) XIC(B256_COMPARE2.EQUAL) B256_MUL(B256_MUL,Temp_D,Out_P.X,Temp_C3,Out_P.X) B256_ADJ(B256_ADJ,Out_P.X) ,XIO(B256_COMPARE1.EQUAL) XIO(B256_COMPARE2.EQUAL) OTL(FAILED) ]OTL(SEQCTRL_DONE.13);
   // ======================================================================================
   // PART 14:   Determine if decoding failed by comparing to x_0, if P.x = 0 and x_0 = 1 decoding fails
   // ======================================================================================
   22: XIC(SEQCTRL_CMD.14)XIO(SEQCTRL_DONE.14)FLL(0,Temp_C10[0],22)B256_COMPARE(B256_COMPARE1,Out_P.X,Temp_C10)[XIC(B256_COMPARE1.EQUAL) XIC(x_0) OTL(FAILED) ,XIO(B256_COMPARE1.EQUAL) ,XIC(B256_COMPARE1.EQUAL) XIO(x_0) ]OTL(SEQCTRL_DONE.14);
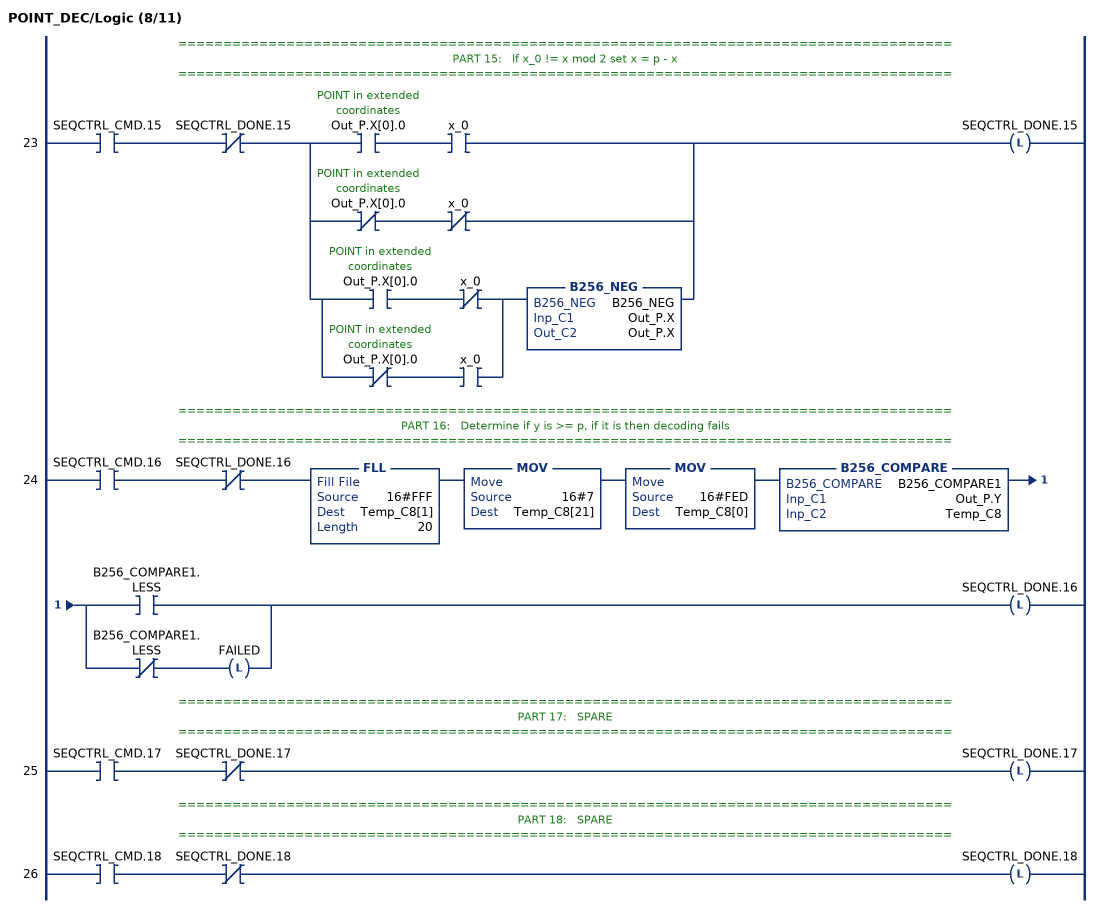
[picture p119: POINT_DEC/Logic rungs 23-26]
   // ======================================================================================
   // PART 15:   If x_0 != x mod 2 set x = p - x
   // ======================================================================================
   23: XIC(SEQCTRL_CMD.15)XIO(SEQCTRL_DONE.15)[XIC(Out_P.X[0].0) XIC(x_0) ,XIO(Out_P.X[0].0) XIO(x_0) ,[XIC(Out_P.X[0].0) XIO(x_0) ,XIO(Out_P.X[0].0) XIC(x_0) ] B256_NEG(B256_NEG,Out_P.X,Out_P.X) ]OTL(SEQCTRL_DONE.15);
   // ======================================================================================
   // PART 16:   Determine if y is >= p, if it is then decoding fails
   // ======================================================================================
   24: XIC(SEQCTRL_CMD.16)XIO(SEQCTRL_DONE.16)FLL(16#FFF,Temp_C8[1],20)MOV(16#7,Temp_C8[21])MOV(16#FED,Temp_C8[0])B256_COMPARE(B256_COMPARE1,Out_P.Y,Temp_C8)[XIC(B256_COMPARE1.LESS) ,XIO(B256_COMPARE1.LESS) OTL(FAILED) ]OTL(SEQCTRL_DONE.16);
   // ======================================================================================
   // PART 17:   SPARE
   // ======================================================================================
   25: XIC(SEQCTRL_CMD.17)XIO(SEQCTRL_DONE.17)OTL(SEQCTRL_DONE.17);
   // ======================================================================================
   // PART 18:   SPARE
   // ======================================================================================
   26: XIC(SEQCTRL_CMD.18)XIO(SEQCTRL_DONE.18)OTL(SEQCTRL_DONE.18);
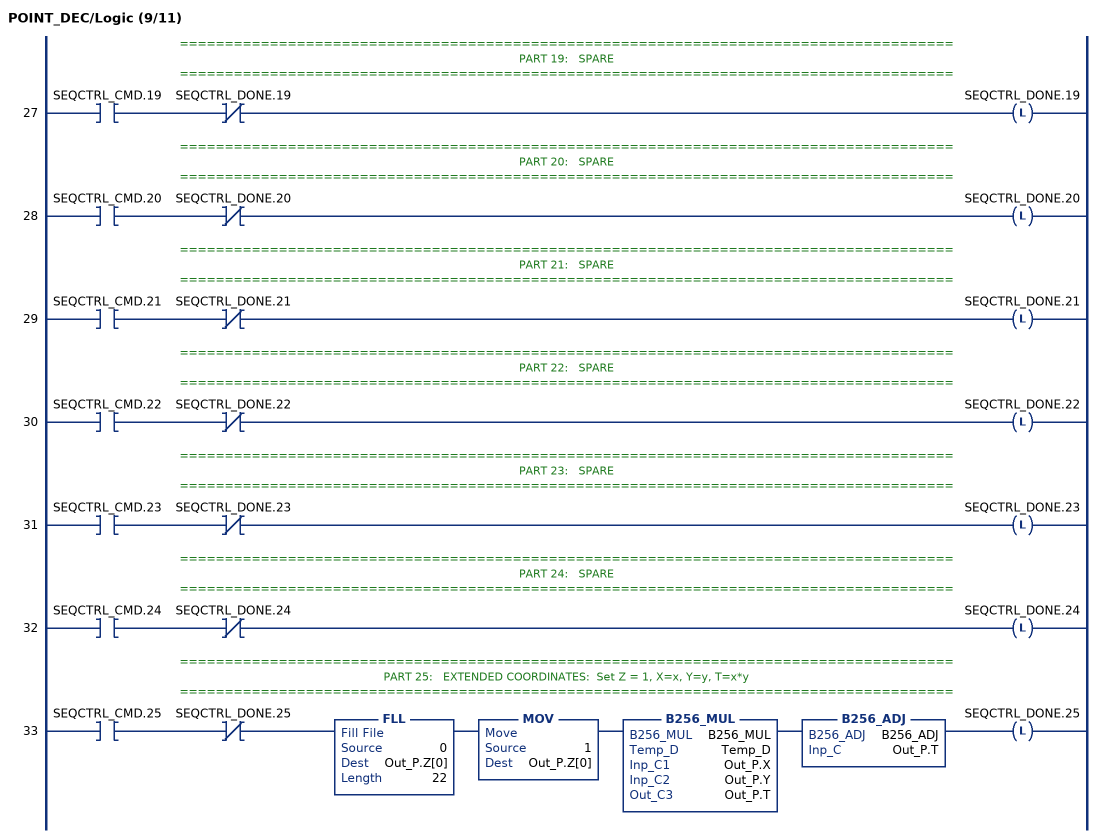
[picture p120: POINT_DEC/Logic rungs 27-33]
   // ======================================================================================
   // PART 19:   SPARE
   // ======================================================================================
   27: XIC(SEQCTRL_CMD.19)XIO(SEQCTRL_DONE.19)OTL(SEQCTRL_DONE.19);
   // ======================================================================================
   // PART 20:   SPARE
   // ======================================================================================
   28: XIC(SEQCTRL_CMD.20)XIO(SEQCTRL_DONE.20)OTL(SEQCTRL_DONE.20);
   // ======================================================================================
   // PART 21:   SPARE
   // ======================================================================================
   29: XIC(SEQCTRL_CMD.21)XIO(SEQCTRL_DONE.21)OTL(SEQCTRL_DONE.21);
   // ======================================================================================
   // PART 22:   SPARE
   // ======================================================================================
   30: XIC(SEQCTRL_CMD.22)XIO(SEQCTRL_DONE.22)OTL(SEQCTRL_DONE.22);
   // ======================================================================================
   // PART 23:   SPARE
   // ======================================================================================
   31: XIC(SEQCTRL_CMD.23)XIO(SEQCTRL_DONE.23)OTL(SEQCTRL_DONE.23);
   // ======================================================================================
   // PART 24:   SPARE
   // ======================================================================================
   32: XIC(SEQCTRL_CMD.24)XIO(SEQCTRL_DONE.24)OTL(SEQCTRL_DONE.24);
   // ======================================================================================
   // PART 25:   EXTENDED COORDINATES:  Set Z = 1, X=x, Y=y, T=x*y
   // ======================================================================================
   33: XIC(SEQCTRL_CMD.25)XIO(SEQCTRL_DONE.25)FLL(0,Out_P.Z[0],22)MOV(1,Out_P.Z[0])B256_MUL(B256_MUL,Temp_D,Out_P.X,Out_P.Y,Out_P.T)B256_ADJ(B256_ADJ,Out_P.T)OTL(SEQCTRL_DONE.25);
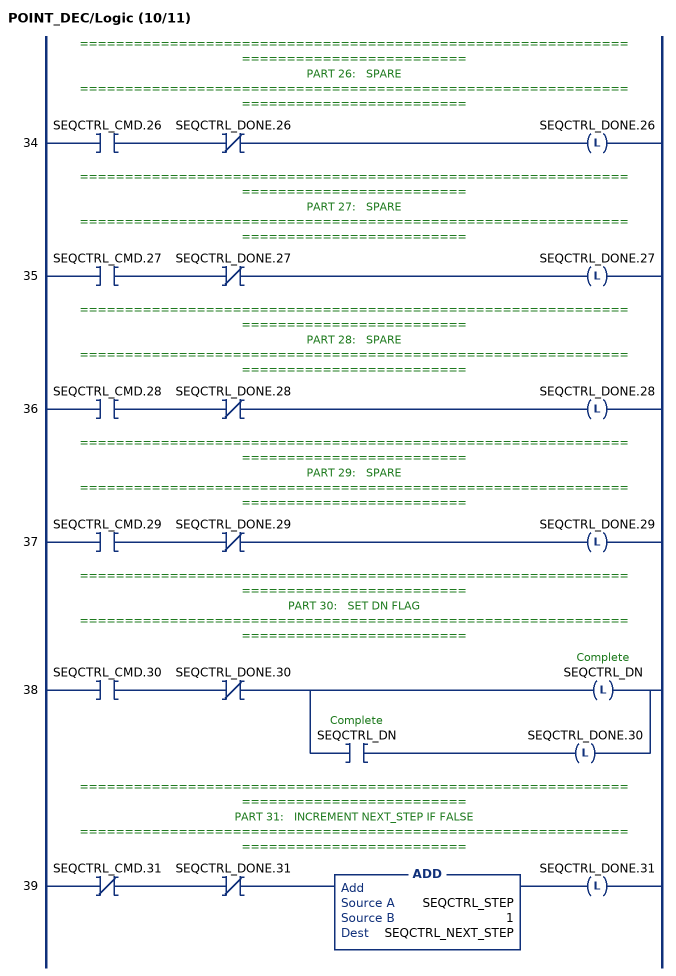
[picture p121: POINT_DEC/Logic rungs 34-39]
   // ======================================================================================
   // PART 26:   SPARE
   // ======================================================================================
   34: XIC(SEQCTRL_CMD.26)XIO(SEQCTRL_DONE.26)OTL(SEQCTRL_DONE.26);
   // ======================================================================================
   // PART 27:   SPARE
   // ======================================================================================
   35: XIC(SEQCTRL_CMD.27)XIO(SEQCTRL_DONE.27)OTL(SEQCTRL_DONE.27);
   // ======================================================================================
   // PART 28:   SPARE
   // ======================================================================================
   36: XIC(SEQCTRL_CMD.28)XIO(SEQCTRL_DONE.28)OTL(SEQCTRL_DONE.28);
   // ======================================================================================
   // PART 29:   SPARE
   // ======================================================================================
   37: XIC(SEQCTRL_CMD.29)XIO(SEQCTRL_DONE.29)OTL(SEQCTRL_DONE.29);
   // ======================================================================================
   // PART 30:   SET DN FLAG
   // ======================================================================================
   38: XIC(SEQCTRL_CMD.30)XIO(SEQCTRL_DONE.30)[OTL(SEQCTRL_DN) ,XIC(SEQCTRL_DN) OTL(SEQCTRL_DONE.30) ];
   // ======================================================================================
   // PART 31:   INCREMENT NEXT_STEP IF FALSE
   // ======================================================================================
   39: XIO(SEQCTRL_CMD.31)XIO(SEQCTRL_DONE.31)ADD(SEQCTRL_STEP,1,SEQCTRL_NEXT_STEP)OTL(SEQCTRL_DONE.31);
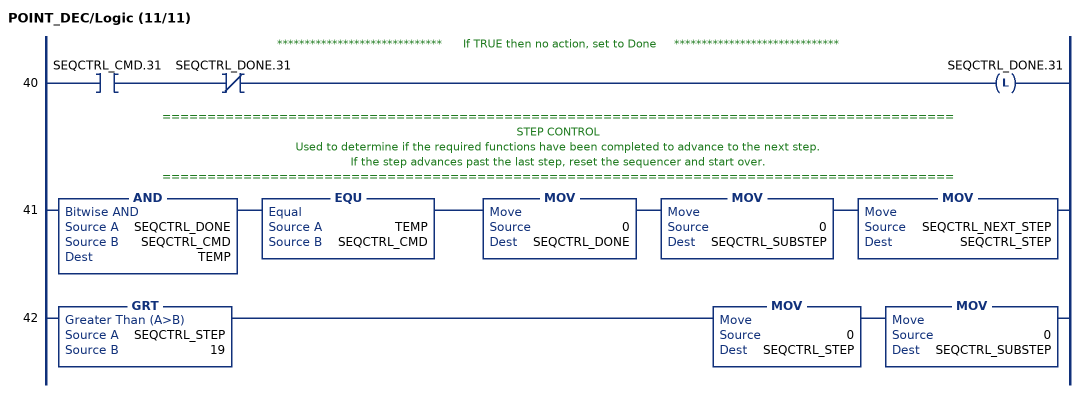
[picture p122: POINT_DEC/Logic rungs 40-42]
   // ******************************      If TRUE then no action, set to Done     ******************************
   40: XIC(SEQCTRL_CMD.31)XIO(SEQCTRL_DONE.31)OTL(SEQCTRL_DONE.31);
   // ========================================================================================
   // STEP CONTROL
   // Used to determine if the required functions have been completed to advance to the next step.
   // If the step advances past the last step, reset the sequencer and start over.
   // ========================================================================================
   41: AND(SEQCTRL_DONE,SEQCTRL_CMD,TEMP)EQU(TEMP,SEQCTRL_CMD)MOV(0,SEQCTRL_DONE)MOV(0,SEQCTRL_SUBSTEP)MOV(SEQCTRL_NEXT_STEP,SEQCTRL_STEP);
   42: GRT(SEQCTRL_STEP,19)MOV(0,SEQCTRL_STEP)MOV(0,SEQCTRL_SUBSTEP);
END_ROUTINE
END_ADD_ON_INSTRUCTION

ADD_ON_INSTRUCTION Ed25519_VERIFY   (* revision 1.0 20170916, vendor Kenneth A. Fischer *)
// Verifies an Ed25519 Signature.
// Revision note:
// Rev1.0: 20170916 - Initial Release
VAR_IN_OUT
   Temp_C1 : DINT[22]; {required}   // Temp C1 value
   Temp_C2 : DINT[22]; {required}   // Temp C2 value
   Temp_C3 : DINT[22]; {required}   // Temp C3 value
   Temp_C4 : DINT[22]; {required}   // Temp C4 value
   Temp_C5 : DINT[22]; {required}   // Temp C5 value
   Temp_C6 : DINT[22]; {required}   // Temp C6 value
   Temp_C7 : DINT[22]; {required}   // Temp C7 value
   Temp_C8 : DINT[22]; {required}   // Temp C8 value
   Temp_C9 : DINT[22]; {required}   // Temp C9 value
   Temp_C10 : DINT[22]; {required}   // Temp C10 value
   Temp_C11 : DINT[22]; {required}   // Temp C11 value
   Temp_C12 : DINT[22]; {required}   // Temp C12 value
   Temp_D1 : DINT[43]; {required}   // Temp D1 value
   Temp_D2 : DINT[43]; {required}   // Temp D2 value
   Temp_E1 : DINT[32]; {required}   // Temp E1 value
   Temp_E2 : DINT[32]; {required}   // Temp E2 value
   Temp_E3 : DINT[32]; {required}   // Temp E3 value
   Temp_L : LINT[4]; {required}   // Temp L value
   Temp_P1 : POINT; {required}
   Temp_P2 : POINT; {required}
   Temp_P3 : POINT; {required}
   Temp_P4 : POINT; {required}
   Temp_MSG : LINT[1600]; {required}   // Temp MSG holder
   Temp_HASH : LINT[8]; {required}   // Temp HASH value
   Inp_Flags : DINT; {required}
   Inp_PubDH : STRING; {required}
   Inp_Ke : STRING; {required}
   Inp_PubKey : STRING; {required}
   Inp_KsID : LINT; {required}
   Inp_KsPrimeID : LINT; {required}
   Inp_Counter : LINT; {required}
   Inp_Sig_R : STRING; {required}
   Inp_Sig_S : STRING; {required}
END_VAR
VAR_OUTPUT
   Out_Status : INT; {access Read Only, visible}
   SEQCTRL_DN : BOOL; {access Read Only}   // Complete
END_VAR
VAR_INPUT
   SEQCTRL_RESET : BOOL;   // Resets Ed25519 Verify if Toggled True
END_VAR
VAR_OUTPUT
   SEQCTRL_STEP : INT; {access Read Only}
   SEQCTRL_SUBSTEP : INT; {access Read Only}
END_VAR
VAR
   SEQCTRL_CMD : DINT;
   SEQCTRL_CMD_TABLE : DINT[70];
   SEQCTRL_DONE : DINT;
   SEQCTRL_NEXT_STEP : INT;
   TEMP : DINT;
   SHA512_SEQ : SHA512_SEQ;
   SEQCTRL_ONS : DINT;
   B512_HtoD : B512_HtoD;
   B256_MODL1 : B256_MODL;
   POINT_MUL1 : POINT_MUL;
   B256_EtoL : B256_EtoL;
   B256_StoC : B256_StoC;
   B256_CtoE : B256_CtoE;
   POINT_DEC1 : POINT_DEC;
   POINT_DEC2 : POINT_DEC;
   POINT_ADD : POINT_ADD;
   B256_StoC_LE : B256_StoC_LE;
   POINT_MUL2 : POINT_MUL;
   EQUAL : BOOL;
   POINT_ENC1 : POINT_ENC;
   POINT_ENC2 : POINT_ENC;
   Wrk_Out : DINT[2];
END_VAR

ROUTINE Logic   (* ladder *)
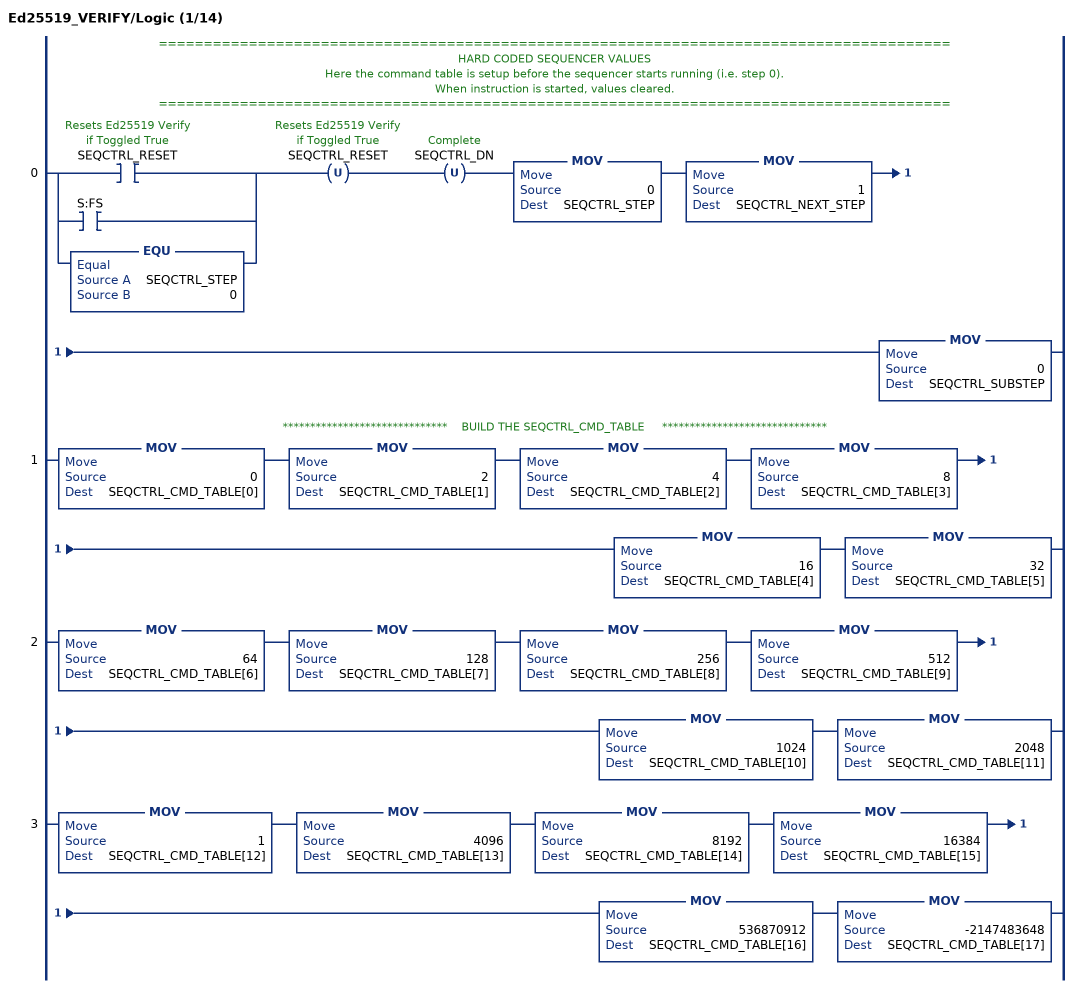
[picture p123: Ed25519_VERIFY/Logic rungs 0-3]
   // ========================================================================================
   // HARD CODED SEQUENCER VALUES
   // Here the command table is setup before the sequencer starts running (i.e. step 0).
   // When instruction is started, values cleared.
   // ========================================================================================
   0: [[XIC(SEQCTRL_RESET) ,XIC(S:FS) ] ,EQU(SEQCTRL_STEP,0) ]OTU(SEQCTRL_RESET)OTU(SEQCTRL_DN)MOV(0,SEQCTRL_STEP)MOV(1,SEQCTRL_NEXT_STEP)MOV(0,SEQCTRL_SUBSTEP);
   // ******************************    BUILD THE SEQCTRL_CMD_TABLE     ******************************
   1: MOV(0,SEQCTRL_CMD_TABLE[0])MOV(2,SEQCTRL_CMD_TABLE[1])MOV(4,SEQCTRL_CMD_TABLE[2])MOV(8,SEQCTRL_CMD_TABLE[3])MOV(16,SEQCTRL_CMD_TABLE[4])MOV(32,SEQCTRL_CMD_TABLE[5]);
   2: MOV(64,SEQCTRL_CMD_TABLE[6])MOV(128,SEQCTRL_CMD_TABLE[7])MOV(256,SEQCTRL_CMD_TABLE[8])MOV(512,SEQCTRL_CMD_TABLE[9])MOV(1024,SEQCTRL_CMD_TABLE[10])MOV(2048,SEQCTRL_CMD_TABLE[11]);
   3: MOV(1,SEQCTRL_CMD_TABLE[12])MOV(4096,SEQCTRL_CMD_TABLE[13])MOV(8192,SEQCTRL_CMD_TABLE[14])MOV(16384,SEQCTRL_CMD_TABLE[15])MOV(536870912,SEQCTRL_CMD_TABLE[16])MOV(-2147483648,SEQCTRL_CMD_TABLE[17]);
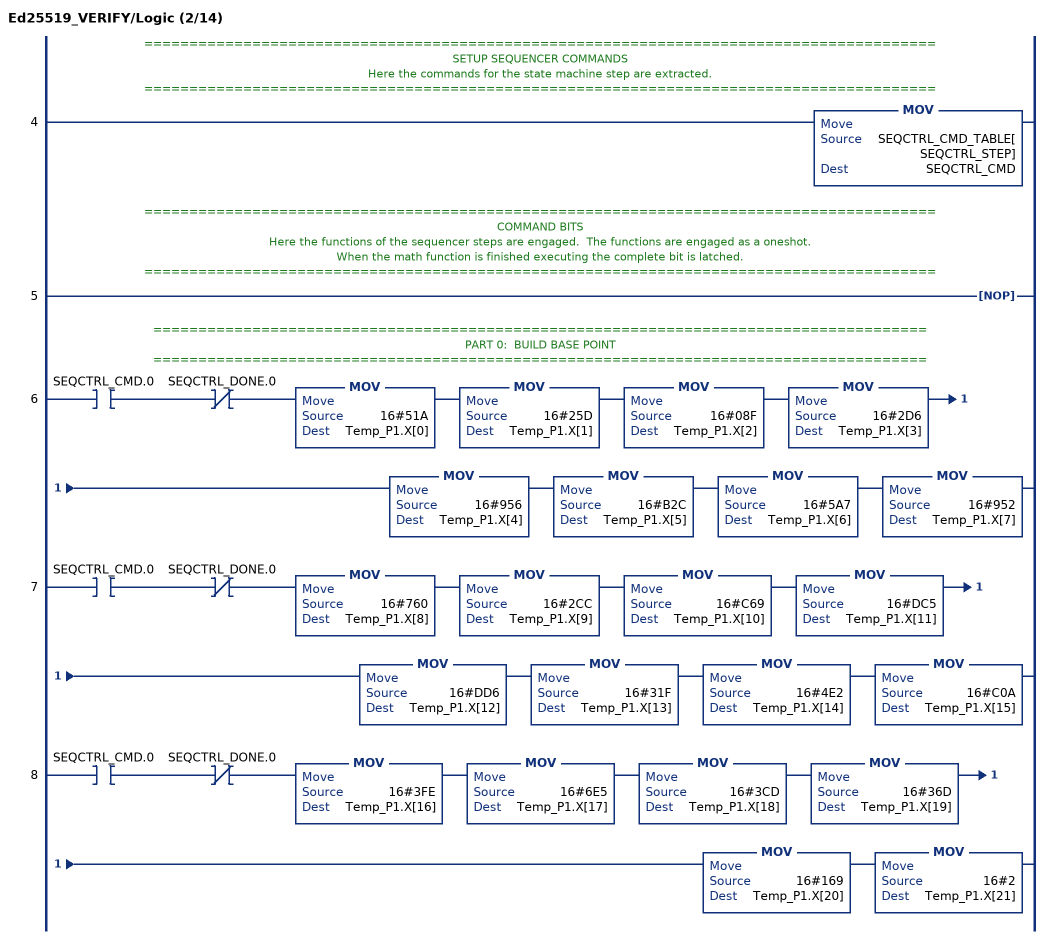
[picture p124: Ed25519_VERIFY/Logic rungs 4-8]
   // ========================================================================================
   // SETUP SEQUENCER COMMANDS
   // Here the commands for the state machine step are extracted.
   // ========================================================================================
   4: MOV(SEQCTRL_CMD_TABLE[SEQCTRL_STEP],SEQCTRL_CMD);
   // ========================================================================================
   // COMMAND BITS
   // Here the functions of the sequencer steps are engaged.  The functions are engaged as a oneshot.
   // When the math function is finished executing the complete bit is latched.
   // ========================================================================================
   5: NOP();
   // ======================================================================================
   // PART 0:  BUILD BASE POINT
   // ======================================================================================
   6: XIC(SEQCTRL_CMD.0)XIO(SEQCTRL_DONE.0)MOV(16#51A,Temp_P1.X[0])MOV(16#25D,Temp_P1.X[1])MOV(16#08F,Temp_P1.X[2])MOV(16#2D6,Temp_P1.X[3])MOV(16#956,Temp_P1.X[4])MOV(16#B2C,Temp_P1.X[5])MOV(16#5A7,Temp_P1.X[6])MOV(16#952,Temp_P1.X[7]);
   7: XIC(SEQCTRL_CMD.0)XIO(SEQCTRL_DONE.0)MOV(16#760,Temp_P1.X[8])MOV(16#2CC,Temp_P1.X[9])MOV(16#C69,Temp_P1.X[10])MOV(16#DC5,Temp_P1.X[11])MOV(16#DD6,Temp_P1.X[12])MOV(16#31F,Temp_P1.X[13])MOV(16#4E2,Temp_P1.X[14])MOV(16#C0A,Temp_P1.X[15]);
   8: XIC(SEQCTRL_CMD.0)XIO(SEQCTRL_DONE.0)MOV(16#3FE,Temp_P1.X[16])MOV(16#6E5,Temp_P1.X[17])MOV(16#3CD,Temp_P1.X[18])MOV(16#36D,Temp_P1.X[19])MOV(16#169,Temp_P1.X[20])MOV(16#2,Temp_P1.X[21]);
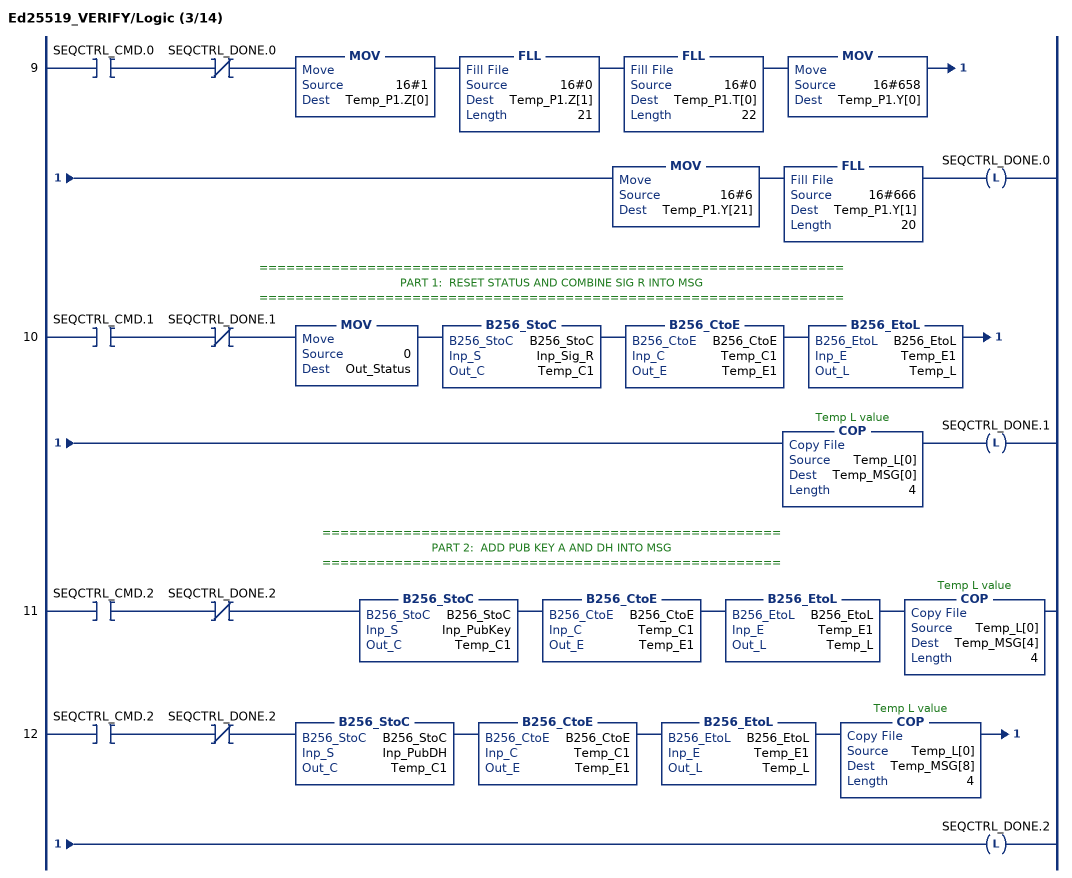
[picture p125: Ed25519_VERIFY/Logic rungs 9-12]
   9: XIC(SEQCTRL_CMD.0)XIO(SEQCTRL_DONE.0)MOV(16#1,Temp_P1.Z[0])FLL(16#0,Temp_P1.Z[1],21)FLL(16#0,Temp_P1.T[0],22)MOV(16#658,Temp_P1.Y[0])MOV(16#6,Temp_P1.Y[21])FLL(16#666,Temp_P1.Y[1],20)OTL(SEQCTRL_DONE.0);
   // =================================================================
   // PART 1:  RESET STATUS AND COMBINE SIG R INTO MSG
   // =================================================================
   10: XIC(SEQCTRL_CMD.1)XIO(SEQCTRL_DONE.1)MOV(0,Out_Status)B256_StoC(B256_StoC,Inp_Sig_R,Temp_C1)B256_CtoE(B256_CtoE,Temp_C1,Temp_E1)B256_EtoL(B256_EtoL,Temp_E1,Temp_L)COP(Temp_L[0],Temp_MSG[0],4)OTL(SEQCTRL_DONE.1);
   // ===================================================
   // PART 2:  ADD PUB KEY A AND DH INTO MSG
   // ===================================================
   11: XIC(SEQCTRL_CMD.2)XIO(SEQCTRL_DONE.2)B256_StoC(B256_StoC,Inp_PubKey,Temp_C1)B256_CtoE(B256_CtoE,Temp_C1,Temp_E1)B256_EtoL(B256_EtoL,Temp_E1,Temp_L)COP(Temp_L[0],Temp_MSG[4],4);
   12: XIC(SEQCTRL_CMD.2)XIO(SEQCTRL_DONE.2)B256_StoC(B256_StoC,Inp_PubDH,Temp_C1)B256_CtoE(B256_CtoE,Temp_C1,Temp_E1)B256_EtoL(B256_EtoL,Temp_E1,Temp_L)COP(Temp_L[0],Temp_MSG[8],4)OTL(SEQCTRL_DONE.2);
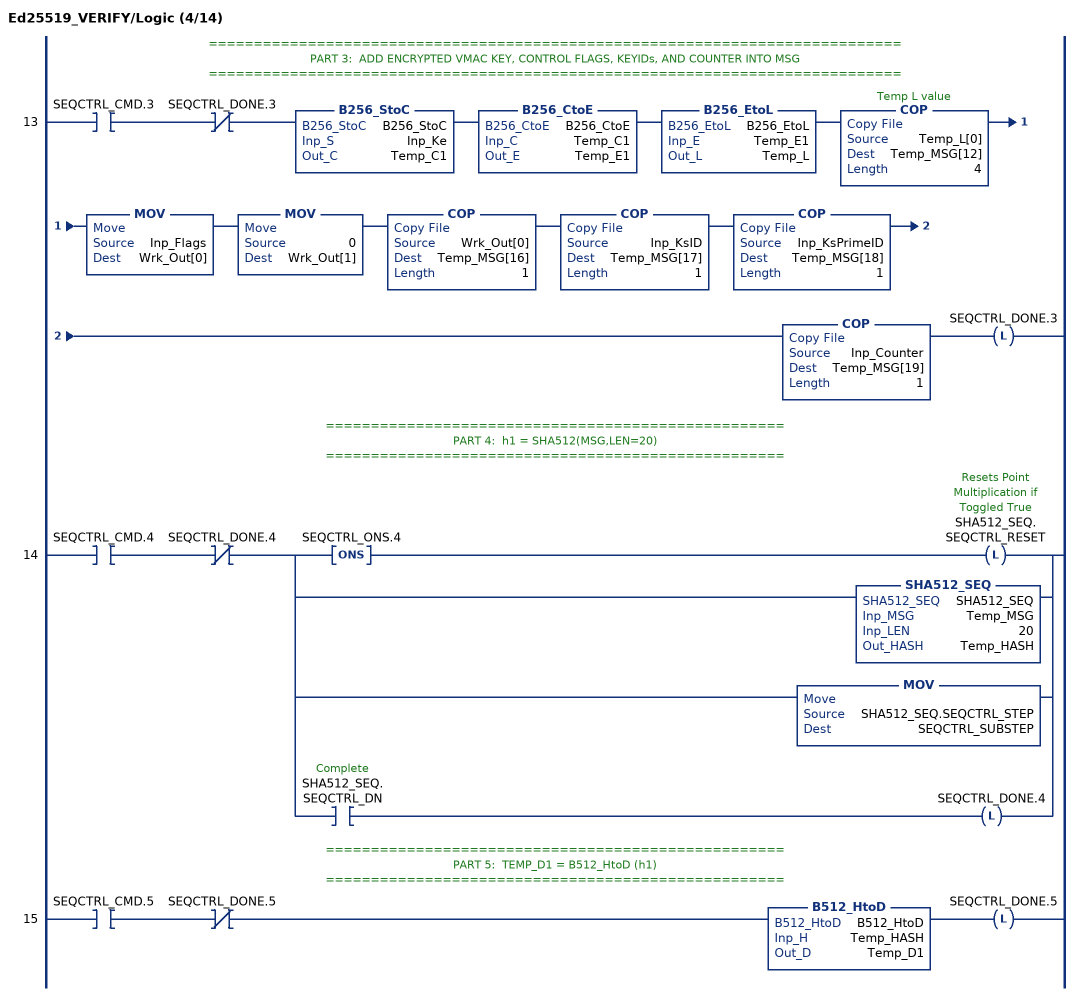
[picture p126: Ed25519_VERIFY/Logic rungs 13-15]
   // =============================================================================
   // PART 3:  ADD ENCRYPTED VMAC KEY, CONTROL FLAGS, KEYIDs, AND COUNTER INTO MSG
   // =============================================================================
   13: XIC(SEQCTRL_CMD.3)XIO(SEQCTRL_DONE.3)B256_StoC(B256_StoC,Inp_Ke,Temp_C1)B256_CtoE(B256_CtoE,Temp_C1,Temp_E1)B256_EtoL(B256_EtoL,Temp_E1,Temp_L)COP(Temp_L[0],Temp_MSG[12],4)MOV(Inp_Flags,Wrk_Out[0])MOV(0,Wrk_Out[1])COP(Wrk_Out[0],Temp_MSG[16],1)COP(Inp_KsID,Temp_MSG[17],1)COP(Inp_KsPrimeID,Temp_MSG[18],1)COP(Inp_Counter,Temp_MSG[19],1)OTL(SEQCTRL_DONE.3);
   // ===================================================
   // PART 4:  h1 = SHA512(MSG,LEN=20)
   // ===================================================
   14: XIC(SEQCTRL_CMD.4)XIO(SEQCTRL_DONE.4)[ONS(SEQCTRL_ONS.4) OTL(SHA512_SEQ.SEQCTRL_RESET) ,SHA512_SEQ(SHA512_SEQ,Temp_MSG,20,Temp_HASH) ,MOV(SHA512_SEQ.SEQCTRL_STEP,SEQCTRL_SUBSTEP) ,XIC(SHA512_SEQ.SEQCTRL_DN) OTL(SEQCTRL_DONE.4) ];
   // ===================================================
   // PART 5:  TEMP_D1 = B512_HtoD (h1)
   // ===================================================
   15: XIC(SEQCTRL_CMD.5)XIO(SEQCTRL_DONE.5)B512_HtoD(B512_HtoD,Temp_HASH,Temp_D1)OTL(SEQCTRL_DONE.5);
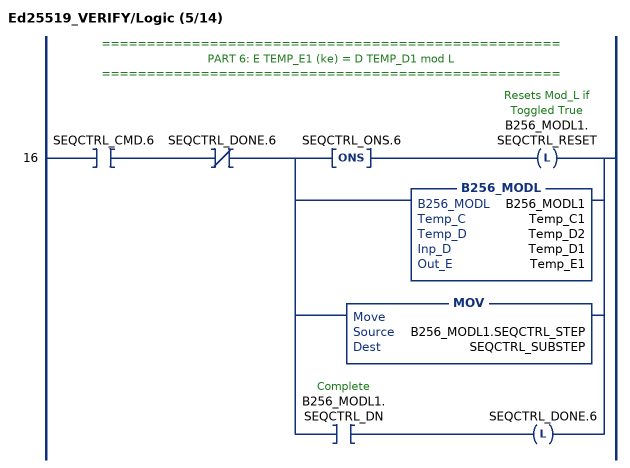
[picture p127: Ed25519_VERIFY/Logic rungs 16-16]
   // ===================================================
   // PART 6: E TEMP_E1 (ke) = D TEMP_D1 mod L
   // ===================================================
   16: XIC(SEQCTRL_CMD.6)XIO(SEQCTRL_DONE.6)[ONS(SEQCTRL_ONS.6) OTL(B256_MODL1.SEQCTRL_RESET) ,B256_MODL(B256_MODL1,Temp_C1,Temp_D2,Temp_D1,Temp_E1) ,MOV(B256_MODL1.SEQCTRL_STEP,SEQCTRL_SUBSTEP) ,XIC(B256_MODL1.SEQCTRL_DN) OTL(SEQCTRL_DONE.6) ];
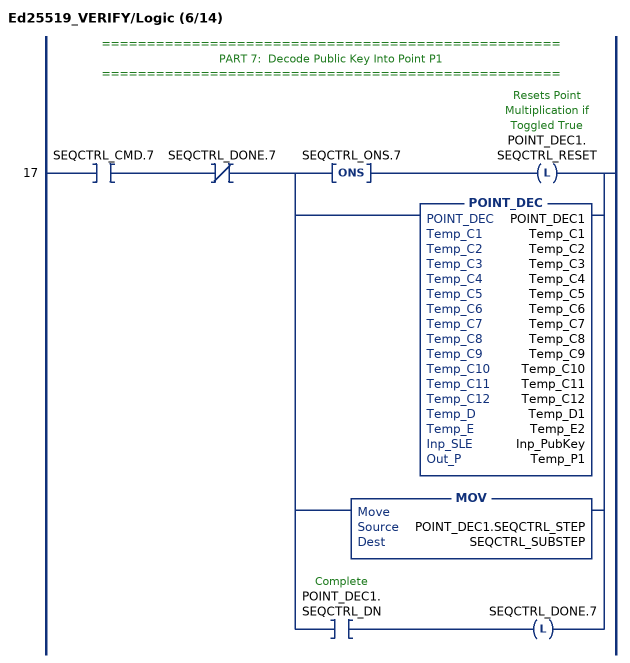
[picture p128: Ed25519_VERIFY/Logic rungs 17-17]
   // ===================================================
   // PART 7:  Decode Public Key Into Point P1
   // ===================================================
   17: XIC(SEQCTRL_CMD.7)XIO(SEQCTRL_DONE.7)[ONS(SEQCTRL_ONS.7) OTL(POINT_DEC1.SEQCTRL_RESET) ,POINT_DEC(POINT_DEC1,Temp_C1,Temp_C2,Temp_C3,Temp_C4,Temp_C5,Temp_C6,Temp_C7,Temp_C8,Temp_C9,Temp_C10,Temp_C11,Temp_C12,Temp_D1,Temp_E2,Inp_PubKey,Temp_P1) ,MOV(POINT_DEC1.SEQCTRL_STEP,SEQCTRL_SUBSTEP) ,XIC(POINT_DEC1.SEQCTRL_DN) OTL(SEQCTRL_DONE.7) ];
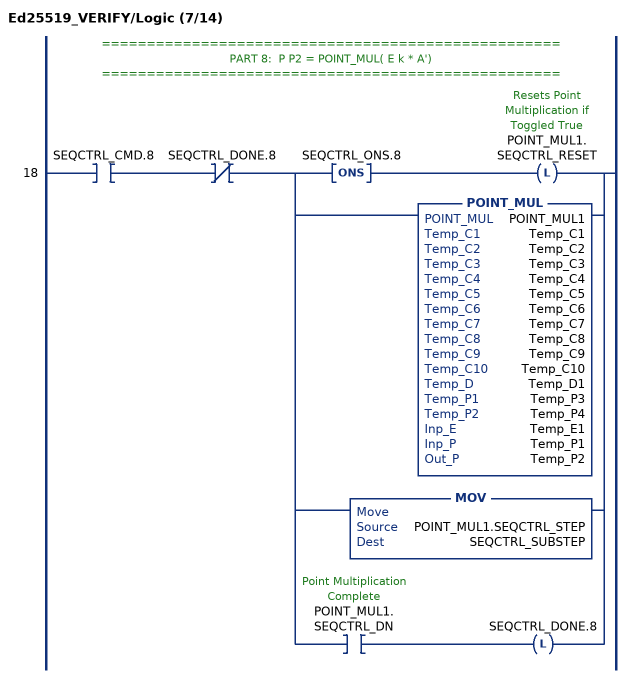
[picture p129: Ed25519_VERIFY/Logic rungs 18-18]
   // ===================================================
   // PART 8:  P P2 = POINT_MUL( E k * A')
   // ===================================================
   18: XIC(SEQCTRL_CMD.8)XIO(SEQCTRL_DONE.8)[ONS(SEQCTRL_ONS.8) OTL(POINT_MUL1.SEQCTRL_RESET) ,POINT_MUL(POINT_MUL1,Temp_C1,Temp_C2,Temp_C3,Temp_C4,Temp_C5,Temp_C6,Temp_C7,Temp_C8,Temp_C9,Temp_C10,Temp_D1,Temp_P3,Temp_P4,Temp_E1,Temp_P1,Temp_P2) ,MOV(POINT_MUL1.SEQCTRL_STEP,SEQCTRL_SUBSTEP) ,XIC(POINT_MUL1.SEQCTRL_DN) OTL(SEQCTRL_DONE.8) ];
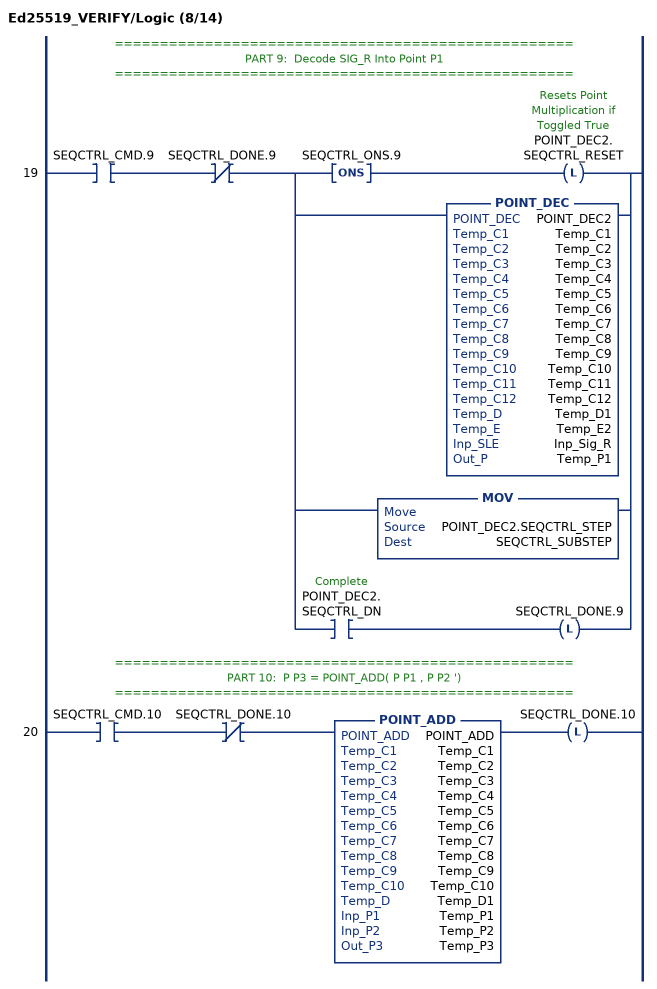
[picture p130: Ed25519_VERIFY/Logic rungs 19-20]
   // ===================================================
   // PART 9:  Decode SIG_R Into Point P1
   // ===================================================
   19: XIC(SEQCTRL_CMD.9)XIO(SEQCTRL_DONE.9)[ONS(SEQCTRL_ONS.9) OTL(POINT_DEC2.SEQCTRL_RESET) ,POINT_DEC(POINT_DEC2,Temp_C1,Temp_C2,Temp_C3,Temp_C4,Temp_C5,Temp_C6,Temp_C7,Temp_C8,Temp_C9,Temp_C10,Temp_C11,Temp_C12,Temp_D1,Temp_E2,Inp_Sig_R,Temp_P1) ,MOV(POINT_DEC2.SEQCTRL_STEP,SEQCTRL_SUBSTEP) ,XIC(POINT_DEC2.SEQCTRL_DN) OTL(SEQCTRL_DONE.9) ];
   // ===================================================
   // PART 10:  P P3 = POINT_ADD( P P1 , P P2 ')
   // ===================================================
   20: XIC(SEQCTRL_CMD.10)XIO(SEQCTRL_DONE.10)POINT_ADD(POINT_ADD,Temp_C1,Temp_C2,Temp_C3,Temp_C4,Temp_C5,Temp_C6,Temp_C7,Temp_C8,Temp_C9,Temp_C10,Temp_D1,Temp_P1,Temp_P2,Temp_P3)OTL(SEQCTRL_DONE.10);
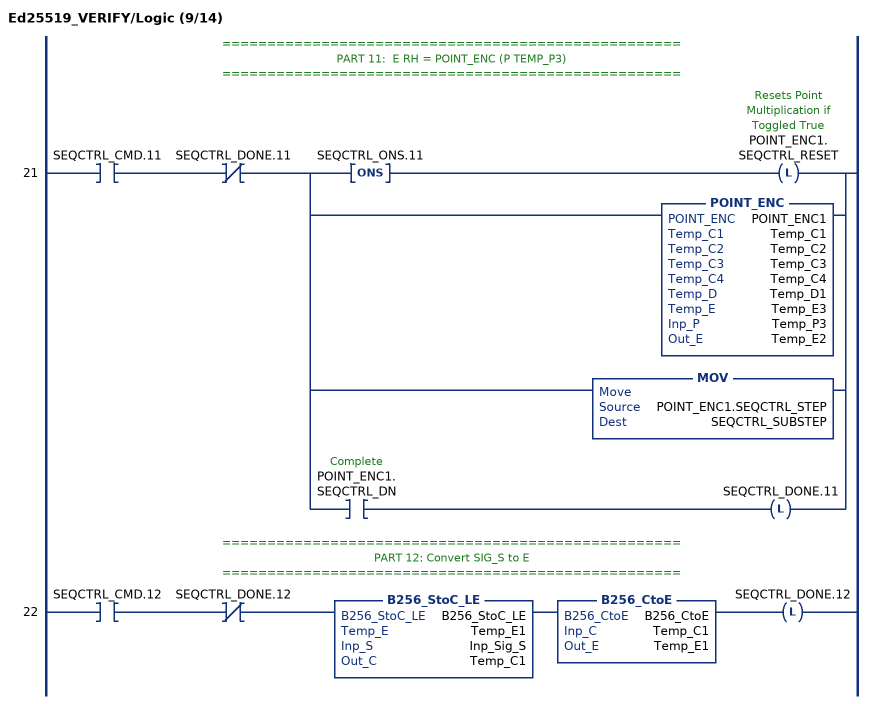
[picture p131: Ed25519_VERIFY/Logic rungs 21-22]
   // ===================================================
   // PART 11:  E RH = POINT_ENC (P TEMP_P3)
   // ===================================================
   21: XIC(SEQCTRL_CMD.11)XIO(SEQCTRL_DONE.11)[ONS(SEQCTRL_ONS.11) OTL(POINT_ENC1.SEQCTRL_RESET) ,POINT_ENC(POINT_ENC1,Temp_C1,Temp_C2,Temp_C3,Temp_C4,Temp_D1,Temp_E3,Temp_P3,Temp_E2) ,MOV(POINT_ENC1.SEQCTRL_STEP,SEQCTRL_SUBSTEP) ,XIC(POINT_ENC1.SEQCTRL_DN) OTL(SEQCTRL_DONE.11) ];
   // ===================================================
   // PART 12: Convert SIG_S to E
   // ===================================================
   22: XIC(SEQCTRL_CMD.12)XIO(SEQCTRL_DONE.12)B256_StoC_LE(B256_StoC_LE,Temp_E1,Inp_Sig_S,Temp_C1)B256_CtoE(B256_CtoE,Temp_C1,Temp_E1)OTL(SEQCTRL_DONE.12);
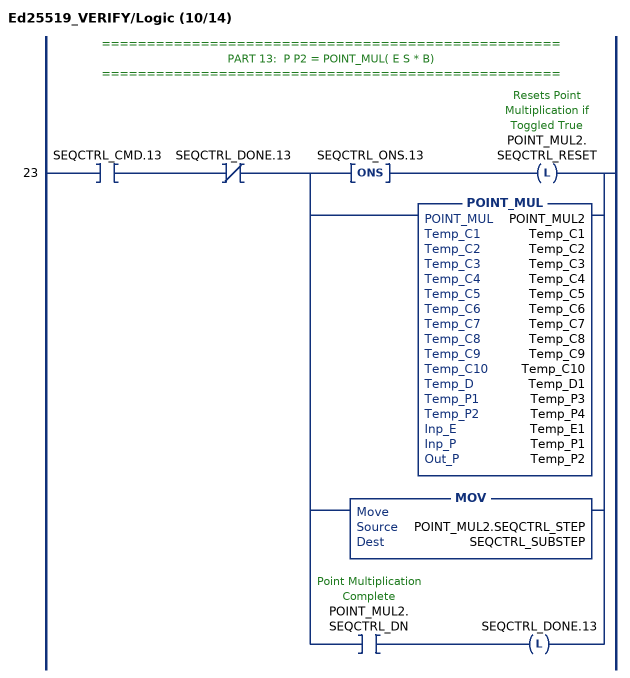
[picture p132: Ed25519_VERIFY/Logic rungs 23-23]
   // ===================================================
   // PART 13:  P P2 = POINT_MUL( E S * B)
   // ===================================================
   23: XIC(SEQCTRL_CMD.13)XIO(SEQCTRL_DONE.13)[ONS(SEQCTRL_ONS.13) OTL(POINT_MUL2.SEQCTRL_RESET) ,POINT_MUL(POINT_MUL2,Temp_C1,Temp_C2,Temp_C3,Temp_C4,Temp_C5,Temp_C6,Temp_C7,Temp_C8,Temp_C9,Temp_C10,Temp_D1,Temp_P3,Temp_P4,Temp_E1,Temp_P1,Temp_P2) ,MOV(POINT_MUL2.SEQCTRL_STEP,SEQCTRL_SUBSTEP) ,XIC(POINT_MUL2.SEQCTRL_DN) OTL(SEQCTRL_DONE.13) ];
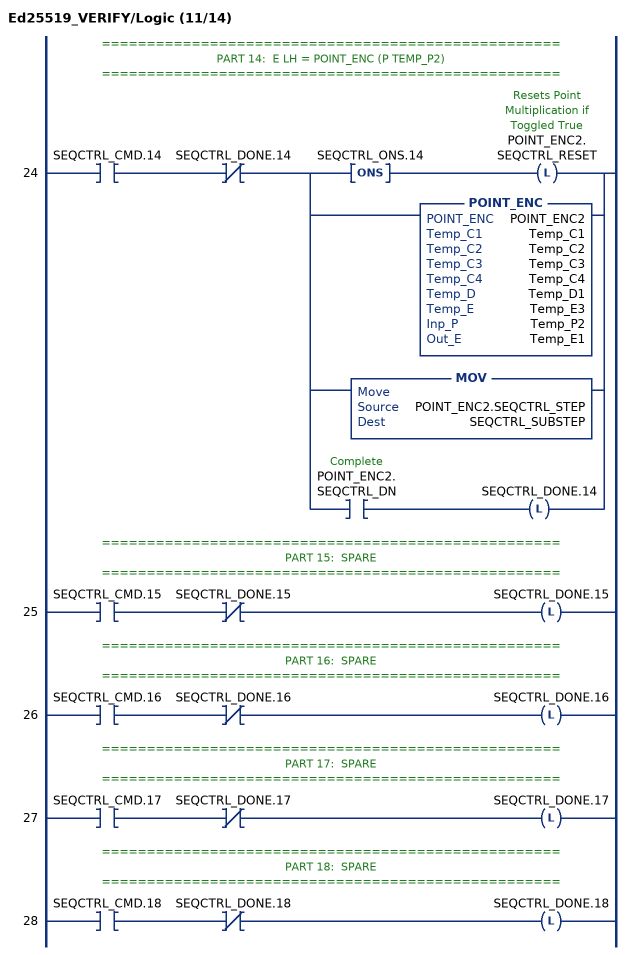
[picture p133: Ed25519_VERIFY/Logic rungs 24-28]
   // ===================================================
   // PART 14:  E LH = POINT_ENC (P TEMP_P2)
   // ===================================================
   24: XIC(SEQCTRL_CMD.14)XIO(SEQCTRL_DONE.14)[ONS(SEQCTRL_ONS.14) OTL(POINT_ENC2.SEQCTRL_RESET) ,POINT_ENC(POINT_ENC2,Temp_C1,Temp_C2,Temp_C3,Temp_C4,Temp_D1,Temp_E3,Temp_P2,Temp_E1) ,MOV(POINT_ENC2.SEQCTRL_STEP,SEQCTRL_SUBSTEP) ,XIC(POINT_ENC2.SEQCTRL_DN) OTL(SEQCTRL_DONE.14) ];
   // ===================================================
   // PART 15:  SPARE
   // ===================================================
   25: XIC(SEQCTRL_CMD.15)XIO(SEQCTRL_DONE.15)OTL(SEQCTRL_DONE.15);
   // ===================================================
   // PART 16:  SPARE
   // ===================================================
   26: XIC(SEQCTRL_CMD.16)XIO(SEQCTRL_DONE.16)OTL(SEQCTRL_DONE.16);
   // ===================================================
   // PART 17:  SPARE
   // ===================================================
   27: XIC(SEQCTRL_CMD.17)XIO(SEQCTRL_DONE.17)OTL(SEQCTRL_DONE.17);
   // ===================================================
   // PART 18:  SPARE
   // ===================================================
   28: XIC(SEQCTRL_CMD.18)XIO(SEQCTRL_DONE.18)OTL(SEQCTRL_DONE.18);
(* Logix 5000 AddOnInstructionDefinition export Ed25519_VERIFY; software revision 30.00; part 7 of 7 *)
(* tags used below, declared in another part *)
   Temp_E1 : DINT[32];   // Temp E1 value
   Temp_E2 : DINT[32];   // Temp E2 value
   Out_Status : INT;
   SEQCTRL_DN : BOOL;   // Complete
   SEQCTRL_STEP : INT;
   SEQCTRL_SUBSTEP : INT;
   SEQCTRL_CMD : DINT;
   SEQCTRL_DONE : DINT;
   SEQCTRL_NEXT_STEP : INT;
   TEMP : DINT;
   POINT_DEC1 : POINT_DEC;
   POINT_DEC2 : POINT_DEC;
   EQUAL : BOOL;
(* Ed25519_VERIFY, continued *)

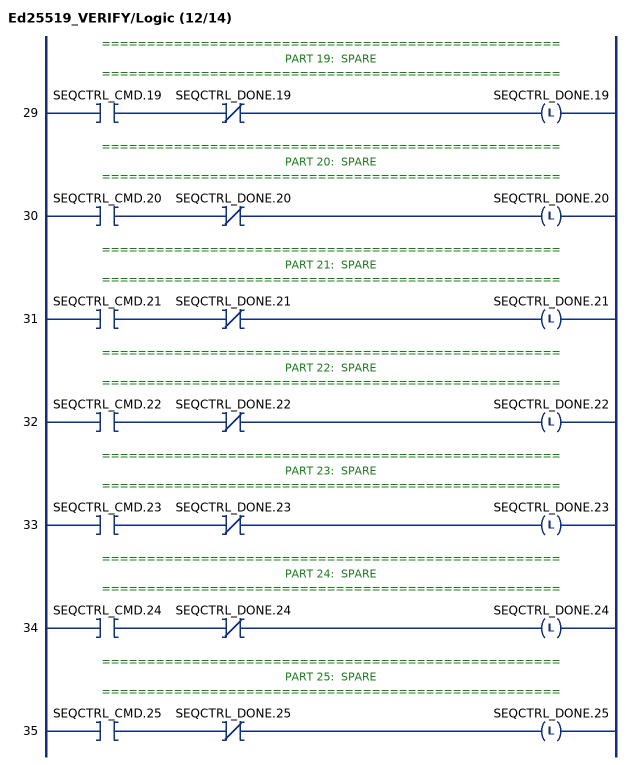
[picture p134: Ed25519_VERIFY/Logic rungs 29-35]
   // ===================================================
   // PART 19:  SPARE
   // ===================================================
   29: XIC(SEQCTRL_CMD.19)XIO(SEQCTRL_DONE.19)OTL(SEQCTRL_DONE.19);
   // ===================================================
   // PART 20:  SPARE
   // ===================================================
   30: XIC(SEQCTRL_CMD.20)XIO(SEQCTRL_DONE.20)OTL(SEQCTRL_DONE.20);
   // ===================================================
   // PART 21:  SPARE
   // ===================================================
   31: XIC(SEQCTRL_CMD.21)XIO(SEQCTRL_DONE.21)OTL(SEQCTRL_DONE.21);
   // ===================================================
   // PART 22:  SPARE
   // ===================================================
   32: XIC(SEQCTRL_CMD.22)XIO(SEQCTRL_DONE.22)OTL(SEQCTRL_DONE.22);
   // ===================================================
   // PART 23:  SPARE
   // ===================================================
   33: XIC(SEQCTRL_CMD.23)XIO(SEQCTRL_DONE.23)OTL(SEQCTRL_DONE.23);
   // ===================================================
   // PART 24:  SPARE
   // ===================================================
   34: XIC(SEQCTRL_CMD.24)XIO(SEQCTRL_DONE.24)OTL(SEQCTRL_DONE.24);
   // ===================================================
   // PART 25:  SPARE
   // ===================================================
   35: XIC(SEQCTRL_CMD.25)XIO(SEQCTRL_DONE.25)OTL(SEQCTRL_DONE.25);
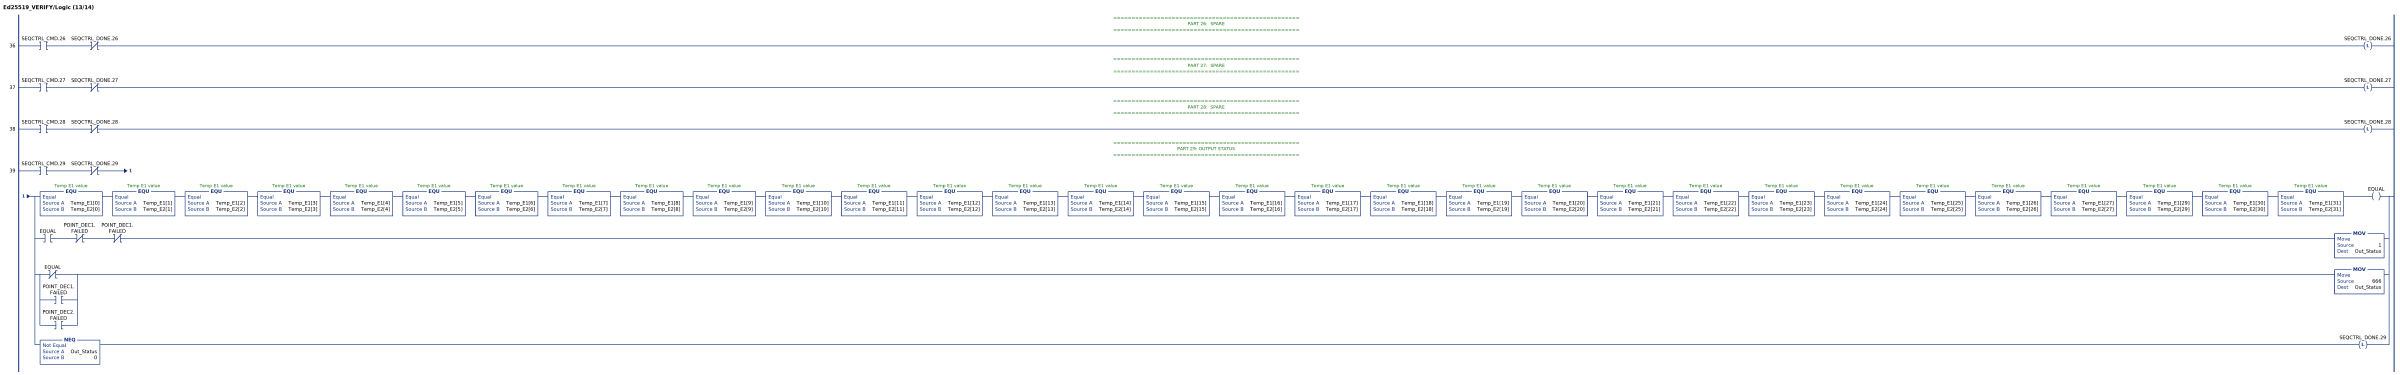
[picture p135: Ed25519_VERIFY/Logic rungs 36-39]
   // ===================================================
   // PART 26:  SPARE
   // ===================================================
   36: XIC(SEQCTRL_CMD.26)XIO(SEQCTRL_DONE.26)OTL(SEQCTRL_DONE.26);
   // ===================================================
   // PART 27:  SPARE
   // ===================================================
   37: XIC(SEQCTRL_CMD.27)XIO(SEQCTRL_DONE.27)OTL(SEQCTRL_DONE.27);
   // ===================================================
   // PART 28:  SPARE
   // ===================================================
   38: XIC(SEQCTRL_CMD.28)XIO(SEQCTRL_DONE.28)OTL(SEQCTRL_DONE.28);
   // ===================================================
   // PART 29: OUTPUT STATUS
   // ===================================================
   39: XIC(SEQCTRL_CMD.29)XIO(SEQCTRL_DONE.29)[EQU(Temp_E1[0],Temp_E2[0]) EQU(Temp_E1[1],Temp_E2[1]) EQU(Temp_E1[2],Temp_E2[2]) EQU(Temp_E1[3],Temp_E2[3]) EQU(Temp_E1[4],Temp_E2[4]) EQU(Temp_E1[5],Temp_E2[5]) EQU(Temp_E1[6],Temp_E2[6]) EQU(Temp_E1[7],Temp_E2[7]) EQU(Temp_E1[8],Temp_E2[8]) EQU(Temp_E1[9],Temp_E2[9]) EQU(Temp_E1[10],Temp_E2[10]) EQU(Temp_E1[11],Temp_E2[11]) EQU(Temp_E1[12],Temp_E2[12]) EQU(Temp_E1[13],Temp_E2[13]) EQU(Temp_E1[14],Temp_E2[14]) EQU(Temp_E1[15],Temp_E2[15]) EQU(Temp_E1[16],Temp_E2[16]) EQU(Temp_E1[17],Temp_E2[17]) EQU(Temp_E1[18],Temp_E2[18]) EQU(Temp_E1[19],Temp_E2[19]) EQU(Temp_E1[20],Temp_E2[20]) EQU(Temp_E1[21],Temp_E2[21]) EQU(Temp_E1[22],Temp_E2[22]) EQU(Temp_E1[23],Temp_E2[23]) EQU(Temp_E1[24],Temp_E2[24]) EQU(Temp_E1[25],Temp_E2[25]) EQU(Temp_E1[26],Temp_E2[26]) EQU(Temp_E1[27],Temp_E2[27]) EQU(Temp_E1[29],Temp_E2[29]) EQU(Temp_E1[30],Temp_E2[30]) EQU(Temp_E1[31],Temp_E2[31]) OTE(EQUAL) ,XIC(EQUAL) XIO(POINT_DEC1.FAILED) XIO(POINT_DEC1.FAILED) MOV(1,Out_Status) ,[XIO(EQUAL) ,XIC(POINT_DEC1.FAILED) ,XIC(POINT_DEC2.FAILED) ] MOV(666,Out_Status) ,NEQ(Out_Status,0) OTL(SEQCTRL_DONE.29) ];
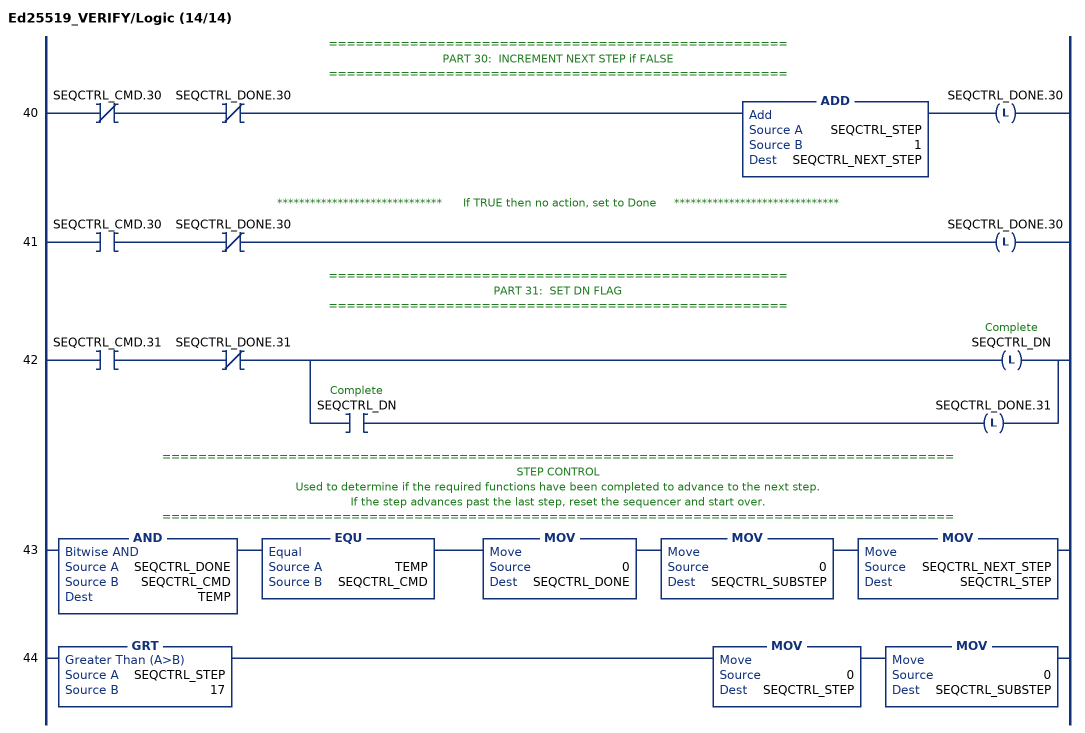
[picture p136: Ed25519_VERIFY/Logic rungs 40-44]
   // ===================================================
   // PART 30:  INCREMENT NEXT STEP if FALSE
   // ===================================================
   40: XIO(SEQCTRL_CMD.30)XIO(SEQCTRL_DONE.30)ADD(SEQCTRL_STEP,1,SEQCTRL_NEXT_STEP)OTL(SEQCTRL_DONE.30);
   // ******************************      If TRUE then no action, set to Done     ******************************
   41: XIC(SEQCTRL_CMD.30)XIO(SEQCTRL_DONE.30)OTL(SEQCTRL_DONE.30);
   // ===================================================
   // PART 31:  SET DN FLAG
   // ===================================================
   42: XIC(SEQCTRL_CMD.31)XIO(SEQCTRL_DONE.31)[OTL(SEQCTRL_DN) ,XIC(SEQCTRL_DN) OTL(SEQCTRL_DONE.31) ];
   // ========================================================================================
   // STEP CONTROL
   // Used to determine if the required functions have been completed to advance to the next step.
   // If the step advances past the last step, reset the sequencer and start over.
   // ========================================================================================
   43: AND(SEQCTRL_DONE,SEQCTRL_CMD,TEMP)EQU(TEMP,SEQCTRL_CMD)MOV(0,SEQCTRL_DONE)MOV(0,SEQCTRL_SUBSTEP)MOV(SEQCTRL_NEXT_STEP,SEQCTRL_STEP);
   44: GRT(SEQCTRL_STEP,17)MOV(0,SEQCTRL_STEP)MOV(0,SEQCTRL_SUBSTEP);
END_ROUTINE
END_ADD_ON_INSTRUCTION
